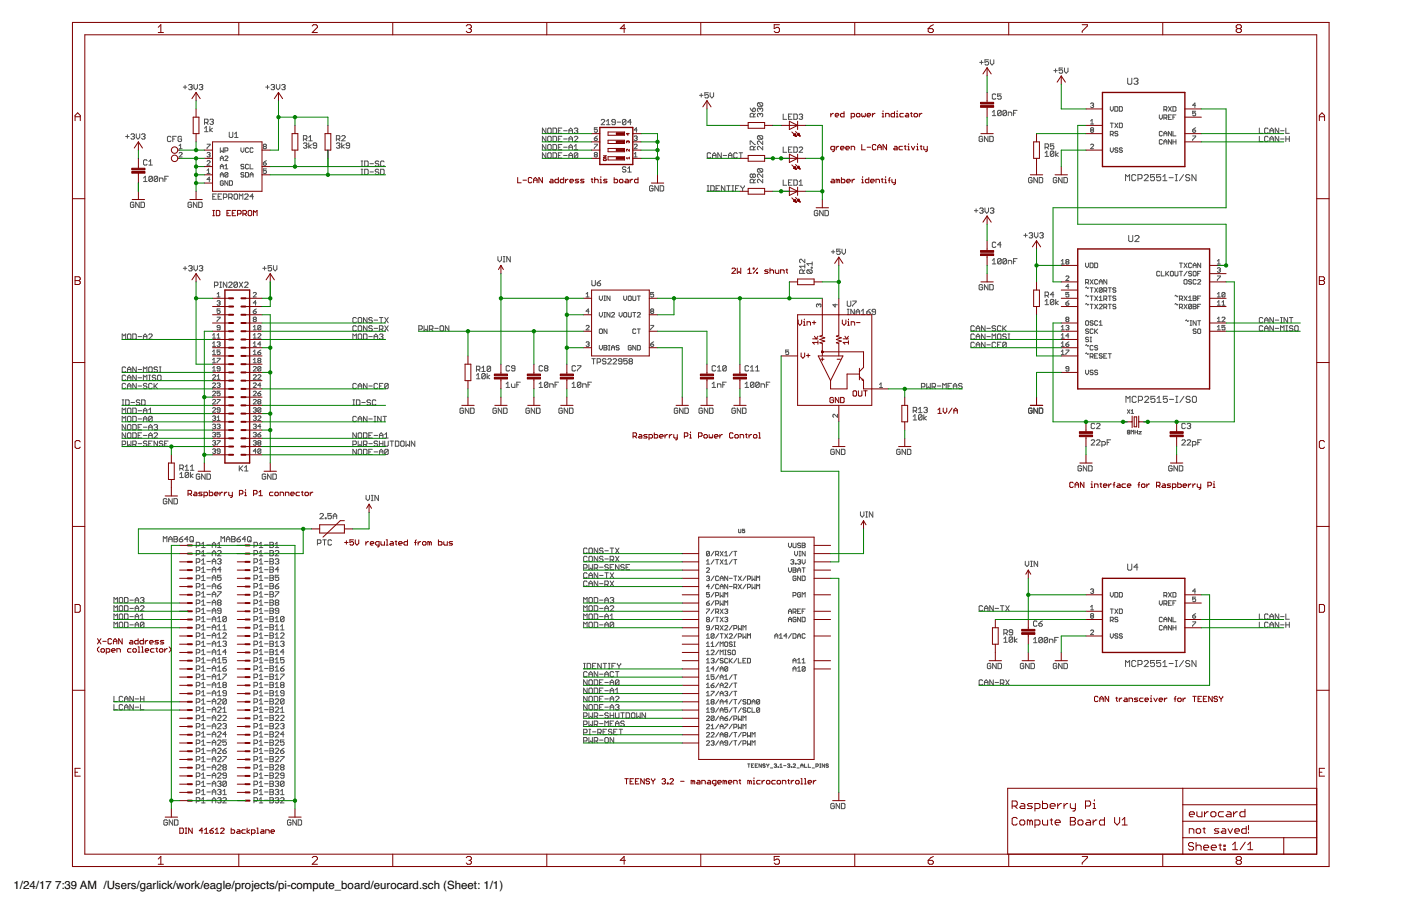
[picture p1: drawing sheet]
<svg xmlns="http://www.w3.org/2000/svg" width="432mm" height="279mm" viewBox="0 0 432 279" stroke-linecap="round" stroke-linejoin="round" font-family="sans-serif">
<defs><g id="words">
<g font-size="3.5">
<text x="4.2" y="274.2">1/24/17</text>
<text x="17" y="274.2">7:39 AM /Users/garlick/work/eagle/projects/pi-compute_board/eurocard.sch (Sheet: 1/1)</text>
</g>
</g></defs>
<g fill="none" stroke="#505050" stroke-width=".31">
<path d="M301.9 19.2h1.1M302.5 18.7v1.1M304.7 18.4h-1.1v.8l.5-.2 .6 .2v.6l-.3 .2h-.6l-.2-.2M305.2 18.4v1.1l.6 .5 .5-.5v-1.1M56.5 26.9h1.1M57 26.3v1.1M58.1 26.3l.3-.2h.5l.3 .2-.3 .6M58.7 26.9h.2M58.9 26.9l.3 .2-.3 .6h-.5l-.3-.3M59.8 26.1v1l.5 .6 .6-.6v-1M61.4 26.3l.3-.2h.5l.3 .2-.3 .6M62 26.9h.2"/>
<path d="M62.2 26.9l.3 .2-.3 .6h-.5l-.3-.3M63 39.5l.6-.5v1.6M63 37.8h.9l.2-.3v-.5l-.2-.3h-.9v1.7M63.6 37.8l.5 .6M64.7 39v1.6M64.7 37l.3-.3h.5l.3 .3-.3 .5M65.2 37.5h.3M65.5 39.5l-.8 .6 .8 .5M65.5 37.5l.3 .3-.3 .6h-.5l-.3-.3M81.9 26.9h1.1M82.4 26.3v1.1M83.5 26.3l.3-.2h.5l.3 .2-.3 .6"/>
<path d="M84.1 26.9h.2M84.3 26.9l.3 .2-.3 .6h-.5l-.3-.3M85.2 26.1v1l.5 .6 .6-.6v-1M86.8 26.3l.3-.2h.5l.3 .2-.3 .6M87.4 26.9h.2M87.6 26.9l.3 .2-.3 .6h-.5l-.3-.3M168.3 39.5v1.6l-1.1-1.6v1.6M168.8 39.8l.3-.3h.5l.3 .3v1.1l-.3 .2h-.5l-.3-.2zM170.4 39.5h.9l.2 .3v1.1l-.2 .2h-.9zM173.2 39.5h-1.1v1.6h1.1M177 39.8l.3-.3h.5l.3 .3-.3 .5M184.1 39.4h-.9v.7l.4-.2 .5 .2-.2 .7-.7-.2"/>
<path d="M185.3 37.1l.2-.3h.6l.3 .3v.3l-1.1 1.1h1.1M186.9 38.5h1.1M186.9 37.4l.6-.6v1.7M189.7 37.7h-.9l-.2-.3 .2-.6h.6l.3 .3v1.1l-.3 .3h-.6l-.2-.3M190.2 37.7h1.1M192.9 37.1v1.1l-.3 .3h-.5l-.3-.3M192.9 37.1l-.3-.3h-.5l-.3 .3v1.1M192.9 37.1l-1.1 1.1M194.6 37.7h-1.1l.8-.9v1.7M215.6 29.4h1.1M216.1 28.9v1.1M218.3 28.6h-1.1v.8l.6-.3 .5 .3v.6l-.3 .2h-.5l-.3-.2"/>
<path d="M218.9 28.6v1.1l.5 .5 .5-.5v-1.1M231.2 33.3l.8 1.1M232 33.6l.3-.3 .5 .3v.5l-.2 .3h-.6zM232.3 36v-.8l-.3-.2h-.5l-.3 .2v.8h1.6M232.8 35l-.5 .5M233.7 31.7l-.3 .3v.5l.3 .3h1.1M233.7 31.7h1.1l.3 .3v.5l-.3 .3M233.7 31.7l1.1 1.1M234.3 35.2l-.3-.2-.6 .2v.6l.3 .2M234.3 33.6l-.3-.3-.6 .3v.5l.3 .3M234.3 35.2l.2-.2 .6 .2v.6l-.3 .2M234.3 33.6v.3"/>
<path d="M234.3 35.2v.3M234.3 33.6l.2-.3 .6 .3v.5l-.3 .3M241.4 35.2v1.6h1.1M243 36h.6M244.1 35.2h-1.1v1.6h1.1M244.7 35.2h.8l.2 .3v1.1l-.2 .2h-.8zM246.3 35.5l.3-.3h.5l.3 .3-.3 .5M246.8 36h.3M247.1 36l.3 .3-.3 .5h-.5l-.3-.2M305.8 34.6l.6-.6v1.7M305.8 35.7h1.1M306.9 29.2l-.3-.2h-.5l-.3 .2v1.1l.3 .3h.5l.3-.3"/>
<path d="M308.6 29h-1.1v.8l.8-.3 .3 .3v.5l-.3 .3h-.6l-.2-.3M308.6 34.3l-.3-.3h-.6l-.2 .3v1.1M308.6 34.3v1.1l-.3 .3h-.6l-.2-.3M308.6 34.3l-1.1 1.1M310.2 34.3l-.3-.3h-.5l-.3 .3v1.1M310.2 34.3v1.1l-.3 .3h-.5l-.3-.3M310.2 34.3l-1.1 1.1M310.7 35.7v-1.1h.9l.2 .3v.8M312.4 34.9h.5M313.5 34h-1.1v1.7M324.8 21.8h1.1M325.3 21.2v1.1"/>
<path d="M327.5 21h-1.1v.8l.6-.3 .5 .3v.5l-.2 .3h-.6l-.3-.3M328.1 21v1.1l.5 .5 .6-.5v-1.1M336.1 32l.7-.2 .3 .2-.3 .5M336.1 37.3l.5-.4v1.3M336.1 38.2h1M336.6 32.5h.2M336.8 32.5l.3 .2-.3 .5-.7-.3M342.2 32.9v.9l.5 .5 .4-.5v-.9M342.2 38h.9M342.7 38v1.4M343.6 32.9h.7l.2 .2v1l-.2 .2h-.7zM343.6 38l.9 1.4"/>
<path d="M344.5 38l-.9 1.4M345 38h.7l.2 .2v.9l-.2 .3h-.7zM345 32.9h.7l.2 .2v1l-.2 .2h-.7zM347.6 24.1v1.6l.3 .3h.6l.3-.3v-1.6M349.5 24.4l.3-.3h.6l.3 .3-.3 .7M350.1 25.1h.3M350.4 25.1l.3 .3-.3 .6h-.6l-.3-.3M357.3 35.4v1l.5 .4 .4-.4v-1M358.7 33.8h.7l.2-.2-.2-.7h-.7v1.4M358.7 36.4h.7l.2-.3-.2-.7h-.7v1.4M359.2 33.8l.4 .5M359.2 36.4l.4 .4"/>
<path d="M360.1 32.9l.9 1.4M360.1 36.1h.5M361 35.4h-.9v1.4h.9M361 32.9l-.9 1.4M361.5 32.9h.7l.2 .2v1l-.2 .2h-.7zM361.5 36.1h.5M362.4 35.4h-.9v1.4M368.5 34.3h-.9v.7l.7-.2 .2 .7-.2 .2-.7-.2M368.5 32.5h-.9l.7-.7v1.4M368.5 39.4l-.9 .7M388.1 39.5v1.6h1.1M390.8 39.8l-.2-.3h-.6l-.2 .3v1.1l.2 .2h.6l.2-.2"/>
<path d="M394.1 39.5v1.6l-1.1-1.6v1.6M396.3 39.5v1.6h1.1M38.7 42.1h1.1M39.3 41.6v1M40.3 41.6l.3-.3h.6l.2 .3-.2 .5M40.9 42.1h.3M41.2 42.1l.2 .3-.2 .5h-.6l-.3-.3M42 41.3v1.1l.5 .5 .6-.5v-1.1M43.6 41.6l.3-.3h.5l.3 .3-.3 .5M44.2 42.1h.2M44.2 54.9l.6-.5v1.6M44.2 56h1.1"/>
<path d="M44.4 42.1l.3 .3-.3 .5h-.5l-.3-.3M45.3 49.6l-.2-.3h-.6l-.3 .3v1l.3 .3h.6l.2-.3M45.9 50.9h1.1M45.9 49.8l.5-.5v1.6M47 54.6v1.1l-.3 .3h-.5l-.3-.3M47 54.6l-.3-.2h-.5l-.3 .2v1.1M47 54.6l-1.1 1.1M48.6 54.6v1.1l-.3 .3h-.5l-.3-.3M48.6 54.6l-.3-.2h-.5l-.3 .2v1.1M48.6 54.6l-1.1 1.1M49.1 56v-1.1h.9l.2 .3v.8M50.8 55.2h.5"/>
<path d="M51.9 54.4h-1.1v1.6M52.7 42.3l-.3-.3h-.5l-.3 .3v1.1l.3 .3h.5l.3-.3M53.3 42.9h.5M54.3 42h-1v1.7M55.2 47.2l.2-.2 .7 .2-.9 1.2h.9M55.2 45.9h.9M55.2 44.9l.5-.4v1.4M56 42.3l-.3-.3h-.5l-.3 .3v1.1l.3 .3h.5l.3-.3v-.5h-.6M63 40.6h1.1M63.8 44.5h.9l-.9 1.4M63.8 47.2l.7-.2 .2 .2-.2 .5M63.8 49.8l.3-.2 .6 .2-.9 1.1h.9"/>
<path d="M63.8 53.5h.9M63.8 52.6l.5-.5v1.4M64.3 47.7h.2M64.5 47.7l.2 .2-.2 .5-.7-.2M64.7 55.3h-.9l.7-.7v1.4M66.7 59.8h-1.1v1.6h1.1M67.9 45.6v1.4l.5-.5 .4 .5v-1.4M67.9 49.5v-.9l.5-.5 .4 .5v.9M67.9 52.1v-1l.5-.4 .4 .4v1M67.9 54.6v-.9l.5-.5 .4 .5v.9M67.9 51.4h.9M67.9 53.9h.9"/>
<path d="M67.9 48.8h.9M68.3 59.8h-1.1v1.6h1.1M68.8 56l-.2-.2-.7 .2v.9l.2 .2 .7-.2v-.4h-.4M69.3 51.1l.5-.4v1.4M69.3 46.5h.7l.2-.7-.2-.2h-.7v1.4M69.3 48.4l.2-.3 .7 .3-.9 1.1h.9M69.3 52.1h.9M70.2 53.4l-.7-.2-.2 .2v1M70.2 55.8v1.3l-.9-1.3v1.3M70.2 53.4v1l-.2 .2-.7-.2M70.2 53.4l-.9 1M70.7 40.8v1.3l.2 .3h.6l.3-.3v-1.3"/>
<path d="M70.7 55.8h.7l.2 .2v.9l-.2 .2h-.7zM72.3 42.4h1.1M72.3 41.3l.5-.5v1.6M72.4 59.8h.5l.3 .3v1.1l-.3 .2h-.5l-.3-.2v-1.1zM74.3 45.6v.9l.4 .5 .5-.5v-.9M75.2 50.9l-.7-.2-.2 .4 .7 .3 .2 .4-.2 .3-.7-.3M75.2 53.4l-.7-.2-.2 .5 .7 .2 .2 .5-.2 .2-.7-.2M75.7 53.2h.7l.2 .2v1l-.2 .2h-.7zM76.6 45.8l-.2-.2-.7 .2v1l.2 .2 .7-.2M76.6 50.9l-.2-.2-.7 .2v.9l.2 .3 .7-.3M77.1 50.7v1.4h.9M77.1 54.6v-.9l.4-.5 .5 .5v.9"/>
<path d="M77.1 53.9h.9M78 45.8l-.2-.2-.7 .2v1l.2 .2 .7-.2M81.2 50.2h.7l.2 .5-.7 .2zM81.4 45.2h.5M81.4 45.2l-.2-.3 .2-.4 .7 .2-.2 .5M81.4 45.2l-.2 .2 .2 .5 .7-.3-.2-.4M82.1 52.1h-.9v.7l.4-.2 .5 .2v.5l-.2 .2-.7-.2M82.1 49.6l-.9 .6M93.5 44.3l.3-.2h.5l.3 .2-.3 .6M93.5 42.9h.8l.3-.3v-.5l-.3-.3h-.8v1.6M94.1 44.9h.2M94.1 42.9l.5 .5"/>
<path d="M94.3 44.9l.3 .3-.3 .5h-.5l-.3-.3M95.2 44.1v1.6M95.2 42.4l.5-.6v1.6M95.2 43.4h1M96 44.6l-.8 .6 .8 .5M97.6 44.9h-.8l-.3-.3 .3-.5h.5l.3 .2v1.1l-.3 .3h-.5l-.3-.3M103.7 44.3l.2-.2h.6l.3 .2-.3 .6M103.7 42.9h.8l.3-.3v-.5l-.3-.3h-.8v1.6M104.2 44.9h.3M104.2 42.9l.6 .5M104.5 44.9l.3 .3-.3 .5h-.6l-.2-.3M105.3 44.1v1.6"/>
<path d="M105.3 42.1l.3-.3h.5l.3 .3v.3l-1.1 1h1.1M106.1 44.6l-.8 .6 .8 .5M107.8 44.9h-.8l-.3-.3 .3-.5h.5l.3 .2v1.1l-.3 .3h-.5l-.3-.3M111.3 53.8h.5M111.3 51.3h.5M111.3 49.7h.5M111.3 52.2h.5M111.6 49.7v1.6M111.6 52.2v1.6M112.4 52.2h.8l.3 .3v1.1l-.3 .2h-.8zM112.4 49.7h.8l.3 .2v1.1l-.3 .3h-.8zM114 50.5h1.1"/>
<path d="M114 53h1.1M116.8 52.5l-.3-.3h-.6l-.2 .5 .2 .3h.6l.3 .6-.3 .2h-.6l-.2-.2M116.8 49.9l-.3-.2h-.6l-.2 .5 .2 .3h.6l.3 .5-.3 .3h-.6l-.2-.3M117.3 52.2h.8l.3 .3v1.1l-.3 .2h-.8zM118.4 49.9l-.3-.2h-.5l-.3 .2v1.1l.3 .3h.5l.3-.3M168.3 42v1.7l-1.1-1.7v1.7M168.3 44.6v1.6l-1.1-1.6v1.6M168.3 47.1v1.6l-1.1-1.6v1.6M168.8 44.9l.3-.3h.5l.3 .3v1l-.3 .3h-.5l-.3-.3zM169.1 42h.5l.3 .3v1.1l-.3 .3h-.5l-.3-.3v-1.1zM169.1 47.1h.5l.3 .3v1.1l-.3 .2h-.5l-.3-.2v-1.1zM170.4 42h.9l.2 .3v1.1l-.2 .3h-.9z"/>
<path d="M170.4 44.6h.9l.2 .3v1l-.2 .3h-.9zM170.4 47.1h.9l.2 .3v1.1l-.2 .2h-.9zM172.1 42.9h.5M172.1 40.3h.5M172.1 45.4h.5M172.1 47.9h.5M173.2 42h-1.1v1.7h1.1M173.2 44.6h-1.1v1.6h1.1M173.2 47.1h-1.1v1.6h1.1M173.7 42.9h1.1M173.7 40.3h1.1M173.7 45.4h1.1"/>
<path d="M173.7 47.9h1.1M175.3 42.9h1.1M175.3 40.3h1.1M175.3 41.1v-1.1l.6-.5 .5 .5v1.1M175.3 43.7v-1.1l.6-.6 .5 .6v1.1M175.3 46.2v-1.1l.6-.5 .5 .5v1.1M175.3 48.7v-1l.6-.6 .5 .6v1M175.3 45.4h1.1M175.3 47.9h1.1M177 42.3l.3-.3h.5l.3 .3v.3l-1.1 1.1h1.1M177 46.2h1.1M177 45.1l.5-.5v1.6"/>
<path d="M177.5 40.3h.3M177.8 40.3l.3 .3-.3 .5h-.5l-.3-.2M178.1 47.4l-.3-.3h-.5l-.3 .3v1.1M178.1 47.4l-1.1 1.1M178.1 47.4v1.1l-.3 .2h-.5l-.3-.2M183.2 42.6h.7l.2 .5-.7 .2zM183.2 44.5h.9l-.9 1.4M183.4 47.7l-.2 .2 .2 .5 .7-.2-.2-.5M183.4 47.7l-.2-.2 .2-.5 .7 .2-.2 .5M183.4 47.7h.5M184.1 41.9l-.9 .7M192.9 51.7l-.3-.3h-.5l-.3 .3 .3 .6h.5l.3 .2-.3 .6h-.5l-.3-.3"/>
<path d="M193.5 53.1h1.1M193.5 52l.5-.6v1.7M195.5 44.7l.2-.2 .7 .2-.9 1.2h.9M195.5 48.4h.9M195.5 42.2l.7-.3 .2 .3-.2 .4M195.5 47.5l.4-.5v1.4M195.9 42.6h.3M196.2 42.6l.2 .3-.2 .4-.7-.2M196.4 40.1h-.9l.7-.7v1.4M201.3 57.6l-.3-.3h-.6l-.2 .3v1l.2 .3h.6l.3-.3v-.5h-.6M202.9 57.3v1.6l-1.1-1.6v1.6M203.5 57.3h.8l.3 .3v1l-.3 .3h-.8z"/>
<path d="M218 57.3h.5M218 58.9h.5M218.2 57.3v1.6M219.1 57.3h.8l.2 .3v1l-.2 .3h-.8zM219.1 47.4l-.3-.3h-.6l-.2 .3v1.1l.2 .2h.6l.3-.2M219.6 48.7v-1l.5-.6 .6 .6v1M219.6 47.9h1.1M220.7 58.1h.5M221.8 57.3h-1.1v1.6h1.1M222.3 47.1v1.6l-1.1-1.6v1.6M222.9 47.9h1.1M223.4 57.3v1.6l-1.1-1.6v1.6"/>
<path d="M224 57.3h1M224.5 48.7v-1l.5-.6 .6 .6v1M224.5 47.9h1.1M224.5 57.3v1.6M225.6 57.3h.5M225.6 58.9h.5M225.9 57.3v1.6M226.7 58.1h.5M227.2 47.4l-.2-.3h-.6l-.3 .3v1.1l.3 .2h.6l.2-.2M227.8 57.3h-1.1v1.6M227.8 47.1h1.1M228.3 47.1v1.6"/>
<path d="M228.3 57.3l.6 .8M228.9 58.1v.8M229.4 57.3l-.5 .8M231.2 44.6v-1.1l1.6 1.1M232 53.9l-.3-.2-.5 .2v.6l.3 .2 .5-.2M232 53.9l.3-.2 .5 .2v.6l-.2 .2-.6-.2M232 53.9v.6M232.3 56.4v-.8l-.3-.3h-.5l-.3 .3v.8h1.6M232.3 46.2v-.8l-.3-.3h-.5l-.3 .3v.8h1.6M232.8 45.1l-.5 .6M232.8 55.3l-.5 .5M233.7 41.8l-.3 .3v.6l.3 .2h1.1"/>
<path d="M233.7 52l-.3 .3v.5l.3 .3h1.1M233.7 41.8h1.1l.3 .3v.6l-.3 .2M233.7 52h1.1l.3 .3v.5l-.3 .3M233.7 41.8l1.1 1.1M233.7 52l1.1 1.1M235.1 43.5v1.1l-1.1-1.1-.6 .3v.5l.3 .3M235.1 45.1v1.1l-1.1-1.1-.6 .3v.5l.3 .3M235.1 53.7v1l-1.1-1-.6 .2v.6l.3 .2M235.1 55.3v1.1l-1.1-1.1-.6 .3v.5l.3 .3M241.4 45.3v1.7h1.1M241.4 55.5v1.6h1.1M243 56.3h.6"/>
<path d="M243 46.2h.6M244.1 45.3h-1.1v1.7h1.1M244.1 55.5h-1.1v1.6h1.1M244.7 45.3h.8l.2 .3v1.1l-.2 .3h-.8zM244.7 55.5h.8l.2 .3v1.1l-.2 .2h-.8zM246.3 45.6l.3-.3h.5l.3 .3v.3l-1.1 1.1h1.1M246.3 57.1h1.1M246.3 56l.5-.5v1.6M302.9 42.3l-.3-.3h-.6l-.2 .3v1.1l.2 .3h.6l.3-.3v-.5h-.6M304.5 42v1.7l-1.1-1.7v1.7M305.1 42h.8l.2 .3v1.1l-.2 .3h-.8zM318.1 55l-.3-.3h-.5l-.3 .3v1.1l.3 .3h.5l.3-.3v-.5h-.5"/>
<path d="M319.7 54.7v1.7l-1.1-1.7v1.7M320.3 54.7h.8l.3 .3v1.1l-.3 .3h-.8zM322.1 47.2l.5-.6v1.6M322.1 48.2h1.1M322.1 45.4h.8l.3-.2v-.6l-.3-.2h-.8v1.6M322.6 45.4l.6 .6M324.8 44.4h-1.1v.8l.8-.3 .3 .3v.5l-.3 .3h-.5l-.3-.3M324.8 46.9l-.3-.3h-.5l-.3 .3v1.1M324.8 46.9v1.1l-.3 .2h-.5l-.3-.2M324.8 46.9l-1.1 1.1M325.4 46.6v1.6M325.7 55l-.3-.3h-.5l-.3 .3v1.1l.3 .3h.5l.3-.3v-.5h-.5"/>
<path d="M326.2 47.2l-.8 .5 .8 .5M327.3 54.7v1.7l-1-1.7v1.7M327.9 54.7h.8l.3 .3v1.1l-.3 .3h-.8zM336.1 44.7l.3-.2 .7 .2-1 1.2h1M336.4 40.1l-.3-.2 .3-.5 .7 .2-.3 .5M336.4 40.1l-.3 .2 .3 .5 .7-.2-.3-.5M336.4 40.1h.4M342.2 45.6v.9l.5 .5 .4-.5v-.9M342.2 41.4h.7l.2-.2-.2-.7h-.7v1.4M342.7 41.4l.4 .5M344.5 45.8l-.2-.2-.7 .2 .2 .5 .7 .2-.2 .5-.7-.2M344.5 40.7l-.2-.2-.7 .2 .2 .5 .7 .2-.2 .5-.7-.2"/>
<path d="M345.9 45.8l-.2-.2-.7 .2 .2 .5 .7 .2-.2 .5-.7-.2M346.9 55.7v-1.9l.6 .7 .6-.7v1.9M350.1 54.2l-.3-.4h-.7l-.3 .4v1.2l.3 .3h.7l.3-.3M350.7 55.1h1l.3-.3v-.6l-.3-.4h-1v1.9M352.7 54.2l.3-.4h.6l.3 .4v.3l-1.2 1.2h1.2M355.8 53.8h-1.2v1l.9-.3 .3 .3v.6l-.3 .3h-.6l-.3-.3M357.7 53.8h-1.2v1l.9-.3 .3 .3v.6l-.3 .3h-.6l-.3-.3M358.2 43.3l-.2-.2-.7 .2v.9l.2 .2 .7-.2M358.2 40.7l-.2-.2-.7 .2v1l.2 .2 .7-.2M358.4 55.7h1.3M358.4 54.5l.6-.7v1.9M358.7 41.2h.9"/>
<path d="M358.7 41.9v-.9l.5-.5 .4 .5v.9M358.7 44.4v-.9l.5-.4 .4 .4v.9M358.7 43.8h.9M360.3 54.8h1.3M361 40.5v1.4l-.9-1.4v1.4M361 43.1v1.3l-.9-1.3v1.3M361.5 40.5v1.4h.9M361.5 43.1v1.3M361.5 43.8h.9M362.2 53.8h.7M362.2 55.7h.7M362.4 43.1v1.3"/>
<path d="M362.6 53.8v1.9M364.8 53.8l-1.3 1.9M366.7 54.2l-.3-.4h-.6l-.4 .7 .4 .3h.6l.3 .6-.3 .3h-.6l-.4-.3M367.6 41.9h.9l-.9 1.4M367.6 40.1h.7l.2 .5-.7 .2zM368.6 53.8v1.9l-1.2-1.9v1.9M388.1 42v1.7h1.1M390.8 42.3l-.2-.3h-.6l-.2 .3v1.1l.2 .3h.6l.2-.3M391.4 42.9h1.1M391.4 43.7v-1.1l.5-.6 .6 .6v1.1M391.4 41.1v-1.1l.5-.5 .6 .5v1.1M391.4 40.3h1.1"/>
<path d="M394.1 42v1.7l-1.1-1.7v1.7M394.7 42.9h1.1M394.7 40.3h1.1M396.3 42.9h1.1M396.3 42v1.7M397.4 42v1.7M41.3 62.6l-.3-.2h-.6l-.2 .2v1.1l.2 .3h.6l.3-.3v-.5h-.6M42.9 62.4v1.6l-1.1-1.6v1.6M43.5 62.4h.8l.2 .2v1.1l-.2 .3h-.8zM59.1 62.6l-.3-.2h-.6l-.2 .2v1.1l.2 .3h.6l.3-.3v-.5h-.6M60.7 62.4v1.6l-1.1-1.6v1.6M61.2 62.4h.9l.2 .2v1.1l-.2 .3h-.9z"/>
<path d="M65.6 60.6h.5M67.2 60.6h.6M68.9 60.9h.8l.2-.3v-.5l-.2-.3h-.8v1.6M70.5 60.9h.8l.3-.3v-.5l-.3-.3h-.8v1.6M71 60.9l.6 .5M73.8 61.4v-1.6l.5 .6 .5-.6v1.6M75.4 60.1l.3-.3h.5l.3 .3v.3l-1.1 1h1.1M78.1 60.6h-1.1l.9-.8v1.6M153.5 79.1v1.1l.5 .6 .5-.6v-1.1M155.1 79.1h.5M155.4 79.1v1.7M157.3 79.1v1.7l-1.1-1.7v1.7"/>
<path d="M248.1 79.9v1.1l-1.1-1.1h-.3l-.3 .3v.6l.3 .2M252.1 65.2l-.3-.3h-.6l-.2 .3v1.1l.2 .2h.6l.3-.2v-.6h-.6M253.7 64.9v1.6l-1.1-1.6v1.6M254.3 64.9h.8l.2 .3v1.1l-.2 .2h-.8zM256.2 77.7h1.1M256.8 77.1v1.1M259 76.8h-1.1v.9l.5-.3 .6 .3v.5l-.3 .3h-.6l-.2-.3M259.5 76.8v1.1l.6 .6 .5-.6v-1.1M300.3 65h1.1M300.8 64.4v1.1M301.9 64.4l.3-.3h.5l.3 .3-.3 .6M302.5 65h.2"/>
<path d="M302.7 65l.3 .2-.3 .6h-.5l-.3-.3M303.6 64.1v1.1l.5 .6 .6-.6v-1.1M305.2 64.4l.3-.3h.5l.3 .3-.3 .6M305.8 65h.2M306 65l.3 .2-.3 .6h-.5l-.3-.3M306.9 75l-.3-.3h-.5l-.3 .3v1l.3 .3h.5l.3-.3M308.6 75.5h-1.1l.8-.8v1.6M313.5 79.8h-1.1v1.6M315.6 72.6h1M316.1 72v1.1M317.2 72l.3-.2h.5l.3 .2-.3 .6M317.7 72.6h.3"/>
<path d="M318 72.6l.3 .2-.3 .6h-.5l-.3-.3M318.8 71.8v1l.6 .6 .5-.6v-1M320.5 72l.2-.2h.6l.2 .2-.2 .6M321 72.6h.3M321.3 72.6l.2 .2-.2 .6h-.6l-.2-.3M347.9 72.6v1.6l.3 .3h.6l.3-.3v-1.6M349.8 72.9l.3-.3h.6l.3 .3v.4l-1.2 1.2h1.2M56.5 82.7h1.1M57 82.2v1.1M58.1 82.2l.3-.3h.5l.3 .3-.3 .5M58.7 82.7h.2M58.9 82.7l.3 .3-.3 .5h-.5l-.3-.2"/>
<path d="M59.8 81.9v1.1l.5 .5 .6-.5v-1.1M61.4 82.2l.3-.3h.5l.3 .3-.3 .5M62 82.7h.2M62.2 82.7l.3 .3-.3 .5h-.5l-.3-.2M66.1 88.1h.8l.3-.3v-.5l-.3-.3h-.8v1.6M66.9 93l.7-.3 .2 .3-.2 .4M66.9 90.7l.5-.5v1.4M66.9 91.6h.9M66.9 97.8h.9l-.9 1.4M67.4 93.4h.2M67.6 93.4l.2 .3-.2 .4-.7-.2M67.7 87h.6"/>
<path d="M67.7 88.6h.6M67.8 95.3h-.9v.7l.5-.3 .4 .3-.2 .7-.7-.3M68 87v1.6M69.9 87v1.6l-1.1-1.6v1.6M70.5 87.3l.2-.3h.6l.2 .3v.2l-1 1.1h1M73.2 87.3l-.3-.3h-.5l-.3 .3v1M73.2 87.3v1l-.3 .3h-.5l-.3-.3M73.2 87.3l-1.1 1M73.7 87l1.1 1.6M74.8 87l-1.1 1.6M75.4 87.3l.2-.3h.6l.3 .3v.2l-1.1 1.1h1.1M78.1 90.4l.2-.2 .7 .2-.9 1.2h.9"/>
<path d="M78.1 96h.7l.2 .4-.7 .3zM78.3 98.5l-.2-.2 .2-.5 .7 .2-.2 .5M78.3 98.5l-.2 .2 .2 .5 .7-.2-.2-.5M78.3 98.5h.5M79 93.4h-.9l.7-.7v1.4M79 95.3l-.9 .7M81 82.7h1.1M81.5 82.2v1.1M83.7 81.9h-1.1v.8l.6-.2 .5 .2v.6l-.3 .2h-.5l-.3-.2M84.3 81.9v1.1l.5 .5 .5-.5v-1.1M109.8 98.2l-.2-.3h-.6l-.2 .3v1.1l.2 .2h.6l.2-.2M110.4 98.2l.3-.3h.5l.3 .3v1.1l-.3 .2h-.5l-.3-.2z"/>
<path d="M113.1 97.9v1.6l-1.1-1.6v1.6M114.7 98.2l-.2-.3h-.6l-.2 .3 .2 .5h.6l.2 .3-.2 .5h-.6l-.2-.2M115.3 98.7h1.1M116.9 97.9h1.1M117.5 97.9v1.6M118.6 97.9l1.1 1.6M119.7 97.9l-1.1 1.6M155.1 80.8h.5M180.6 91.6h1M180.6 90.7l.5-.5v1.4M181.6 96h-1l.7-.7v1.4M182.4 86.5v1.3l.3 .3h.5l.3-.3v-1.3"/>
<path d="M184 87.3h.8l.3 .5-.3 .3h-.5l-.3-.3zM184.7 91.3v.9l.5 .5 .5-.5v-.9M184.7 96.4v.9l.5 .5 .5-.5v-.9M185.1 86.5l-1.1 .8M186.1 92.7h.5M186.1 97.8h.5M186.1 91.3h.5M186.1 96.4h.5M186.4 91.3v1.4M186.4 96.4v1.4M188 91.3v1.4l-.9-1.4v1.4M188 96.4v1.4l-.9-1.4v1.4"/>
<path d="M188.5 96.6l.2-.2 .7 .2-.9 1.2h.9M190.8 96.4v.9l.5 .5 .4-.5v-.9M192.2 91.3v.9l.5 .5 .4-.5v-.9M192.4 96.4l.7 .2v.9l-.2 .3-.7-.3v-.9zM193.6 91.5l.3-.2 .7 .2v1l-.3 .2-.7-.2zM193.6 96.4v1.1l.3 .3 .7-.3v-1.1M195 91.3v1.2l.3 .2 .7-.2v-1.2M195 96.4h1M195.5 96.4v1.4M196.4 96.6l.3-.2 .7 .2-1 1.2h1M196.4 91.3h1M196.9 91.3v1.4"/>
<path d="M200.8 96l-.3-.3 .3-.4 .7 .2-.3 .5M200.8 96l-.3 .2 .3 .5 .7-.3-.3-.4M200.8 96h.4M201.5 90.2h-1v.7l.7-.2 .3 .7-.3 .2-.7-.2M247.5 84.3v-.8l-.3-.3h-.5l-.3 .3v.8h1.7M248.1 83.2l-.6 .6M248.1 82.1h-1.7l.6 .6M248.1 81.6v1.1M249 83.2l-.3 .3v.5l.3 .3h1M249 83.2h1l.3 .3v.5l-.3 .3M249 83.2l1 1.1M250 82.4h.3v.3h-.3z"/>
<path d="M250.3 80.8v1.1M250.3 81.3h-1.6l.5 .6M252.3 94l.3-.3 .4 .3-.2 .7M252.3 94l-.2-.3-.5 .3 .3 .7M252.3 94v.2M257.4 93.7v1l-.7-.7h1.4M261.1 97h.6M261.1 95.4h.6M261.1 92.8v1.4l.3 .3h.6l.2-.3v-1.4M261.4 95.4v1.6M262.8 92.8h1.1l-1.1 1.7M263.3 95.4v1.6l-1.1-1.6v1.6"/>
<path d="M263.9 97v-1.1l.5-.5 .5 .5v1.1M263.9 96.2h1M265.5 97h1.1M265.5 95.9l.5-.5v1.6M267.1 96.2h.8l.3 .5-.3 .3h-.5l-.3-.3zM268.2 95.4l-1.1 .8M269.9 96.2h-.9l-.2-.3 .2-.5h.6l.3 .3v1l-.3 .3h-.6l-.2-.3M302.9 88l-.3-.2h-.6l-.2 .2v1.1l.2 .3h.6l.3-.3v-.5h-.6M304.5 87.8v1.6l-1.1-1.6v1.6M305.1 87.8h.8l.2 .2v1.1l-.2 .3h-.8zM305.8 80.3l.6-.5v1.6M305.8 81.4h1.1"/>
<path d="M308.6 80v1.1l-.3 .3h-.6l-.2-.3M308.6 80l-.3-.2h-.6l-.2 .2v1.1M308.6 80l-1.1 1.1M310.2 80v1.1l-.3 .3h-.5l-.3-.3M310.2 80l-.3-.2h-.5l-.3 .2v1.1M310.2 80l-1.1 1.1M310.7 81.4v-1.1h.9l.2 .3v.8M312.4 80.6h.5M322.1 92.9l.5-.6v1.7M322.1 94h1.1M322.1 91.1h.8l.3-.2v-.6l-.3-.2h-.8v1.6M322.6 91.1l.6 .6"/>
<path d="M324.8 92.6v1.1l-.3 .3h-.5l-.3-.3M324.8 92.6l-.3-.3h-.5l-.3 .3v1.1M324.8 92.6l-1.1 1.1M324.8 90.9h-1.1l.8-.8v1.6M325.4 92.3v1.7M326.2 92.9l-.8 .5 .8 .6M327.1 80.5l.5-.5v1.4M327.1 81.4h.9M328.5 93.4h.7l.2 .5-.7 .2zM328.5 85.3l.2-.2 .7 .2-.9 1.2h.9M328.7 98.5l-.2 .2 .2 .5 .7-.2-.2-.5M328.7 98.5l-.2-.2 .2-.5 .7 .2-.2 .5"/>
<path d="M328.7 80.7h.5M328.7 98.5h.5M328.7 80.7l-.2 .3 .2 .4 .7-.2-.2-.5M328.7 80.7l-.2-.2 .2-.5 .7 .3-.2 .4M329.4 90.2h-.9v.7l.7-.2 .2 .7-.2 .2-.7-.2M329.4 88.3h-.9l.7-.6v1.3M329.4 92.7l-.9 .7M334.6 88.8l.2-.3 .5 .5 .2-.2M334.6 81.1v1l.4 .4 .5-.4v-1M334.6 87.1h.7l.2-.2-.2-.7h-.7v1.4M334.6 91.3l.2-.2 .5 .4 .2-.2M334.6 93.8l.2-.2 .5 .5 .2-.3"/>
<path d="M334.8 98.9l.7 .2v1l-.2 .2-.7-.2v-1zM335 87.1l.5 .5M336 81.1h.7l.2 .3v.9l-.2 .2h-.7zM336 86.2l.9 1.4M336 88.8h.9M336 91.3h.9M336 93.8h.9M336.4 88.8v1.3M336.4 91.3v1.4M336.4 93.8v1.4M336.9 99.1l-.2-.2-.7 .2 .2 .5 .7 .2-.2 .5-.7-.2M336.9 86.2l-.9 1.4"/>
<path d="M337.4 81.1h.7l.2 .3v.9l-.2 .2h-.7zM337.4 88.8l.9 1.3M337.4 91.3l.9 1.4M337.4 93.8l.9 1.4M338.3 86.4l-.2-.2-.7 .2v1l.2 .2 .7-.2M338.3 99.1l-.2-.2-.7 .2v1l.2 .2 .7-.2M338.3 88.8l-.9 1.3M338.3 91.3l-.9 1.4M338.3 93.8l-.9 1.4M338.8 92.7h.9M338.8 94.1l.2-.3 .7 .3-.9 1.1h.9M338.8 87.6v-.9l.5-.5 .4 .5v.9"/>
<path d="M338.8 86.9h.9M338.8 91.8l.5-.5v1.4M338.8 99.4l.5-.5v1.4M339.7 89l-.2-.2-.7 .2v.9M339.7 89v.9l-.2 .2-.7-.2M339.7 89l-.9 .9M340.2 92.2h.7l.2-.7-.2-.2h-.7v1.4M340.2 89.7h.7l.2-.7-.2-.2h-.7v1.3M340.2 94.8h.7l.2-.7-.2-.3h-.7v1.4M340.7 89.7l.4 .4M340.7 92.2l.4 .5M340.7 94.8l.4 .4"/>
<path d="M341.1 86.2v1.4l-.9-1.4v1.4M341.6 88.8h.9M341.6 91.3h.9M341.6 93.8h.9M342.1 88.8v1.3M342.1 91.3v1.4M342.1 93.8v1.4M343.9 91.5l-.2-.2-.7 .2 .2 .5 .7 .2-.2 .5-.7-.2M343.9 94.1l-.2-.3-.7 .3 .2 .4 .7 .3-.2 .4-.7-.2M343.9 89l-.2-.2-.7 .2 .2 .5 .7 .2-.2 .4-.7-.2M357.4 83.9l-.2-.2-.7 .2v1l.2 .2 .7-.2M357.9 83.7v1.4h.9"/>
<path d="M359.3 83.7v1.4M359.5 84.4l.7 .7M360.2 83.7l-.9 .9M360.7 83.9l.3-.2 .7 .2v1l-.3 .2-.7-.2zM362.1 93.8l.3-.2 .4 .5 .3-.3M362.1 83.7v1.2l.3 .2 .7-.2v-1.2M362.1 91.3l.3-.2 .4 .4 .3-.2M363.5 81.1h.9M363.5 92.2h.7l.2-.7-.2-.2h-.7v1.4M363.5 94.8h.7l.2-.7-.2-.3h-.7v1.4M363.5 83.7h.9M364 81.1v1.4"/>
<path d="M364 83.7v1.4M364 92.2l.4 .5M364 94.8l.4 .4M364.9 86.4l.3-.2 .7 .2v1l-.3 .2-.7-.2zM364.9 81.1l1 1.4M364.9 91.3l1 1.4M364.9 93.8l1 1.4M365.4 98.9l.2-.2 .5 .4 .2-.2M365.9 81.1l-1 1.4M365.9 83.7l-1 1.4M365.9 91.3l-1 1.4M365.9 93.8l-1 1.4"/>
<path d="M366.3 92.7h1M366.3 91.8l.5-.5v1.4M366.8 98.9h.5M367 98.9v1.4M367.3 81.4l-.3-.3-.7 .3v.9l.3 .2 .7-.2M367.3 94.1v.9l-.3 .2-.7-.2M367.3 86.4l-.7-.2-.3 .5 .7 .2 .3 .5-.3 .2-.7-.2M367.3 94.1l-.7-.3-.3 .3v.9M367.3 83.9l-.3-.2-.7 .2 .3 .5h.4l.3 .5-.3 .2-.7-.2M367.3 94.1l-1 .9M367.7 91.3h.7l.3 .2-.3 .5 .3 .5-.3 .2h-.7zM367.7 93.8h.7l.3 .3-.3 .4 .3 .5-.3 .2h-.7z"/>
<path d="M367.7 92h.7M367.7 94.5h.7M367.7 82.5v-.9l.5-.5 .5 .5v.9M367.7 83.9l.3-.2 .7 .2v1l-.3 .2-.7-.2zM367.7 81.9h1M368.7 86.4l-.3-.2-.7 .2v1l.3 .2 .7-.2M368.7 98.9v1.4l-1-1.4v1.4M369.1 86.4l.3-.2 .7 .2-1 1.2h1M369.1 92h.5M369.1 94.5h.5M369.1 98.9h1M369.1 84.4h.5"/>
<path d="M369.6 98.9v1.4M370.1 81.1v1.4l-1-1.4v1.4M370.1 83.7h-1v1.4M370.1 91.3h-1v1.4M370.1 93.8h-1v1.4M375.2 98.3l.5-.5v1.4M375.2 91.6h.9M375.2 94.1h.9M375.2 99.2h.9M375.2 81.4h.9M375.2 85.1h.9l-.9 1.4M375.2 80.5l.5-.5v1.4"/>
<path d="M375.2 90.7l.5-.5v1.4M375.2 93.2l.5-.5v1.4M375.2 82.8l.7-.2 .2 .2-.2 .5M375.7 83.3h.2M375.9 83.3l.2 .2-.2 .5-.7-.3M376.6 94.1h.9M376.6 98l.3-.2 .6 .2-.9 1.2h.9M376.6 93.2l.5-.5v1.4M377.5 90.4v1l-.2 .2-.7-.2M377.5 90.4l-.2-.2-.7 .2v1M377.5 90.4l-.9 1M389.2 98.2l-.3-.3h-.5l-.3 .3v1.1l.3 .2h.5l.3-.2"/>
<path d="M389.8 99.5v-1l.5-.6 .5 .6v1M389.8 98.7h1M392.5 97.9v1.6l-1.1-1.6v1.6M393 98.7h1.1M394.7 97.9h.5M394.7 99.5h.5M394.9 97.9v1.6M396.9 97.9v1.6l-1.1-1.6v1.6M397.4 97.9h1.1M397.9 97.9v1.6M37.7 104.6v-1.6l.5 .5 .5-.5v1.6M38.7 113.4l-.2-.2h-.6l-.2 .2v1.1l.2 .3h.6l.2-.3"/>
<path d="M38.7 118.5l-.2-.3h-.6l-.2 .3v1.1l.2 .3h.6l.2-.3M38.7 116l-.2-.3h-.6l-.2 .3v1.1l.2 .2h.6l.2-.2M39.3 103.3l.3-.3h.5l.3 .3v1.1l-.3 .2h-.5l-.3-.2zM39.3 114.8v-1.1l.5-.5 .6 .5v1.1M39.3 117.3v-1.1l.5-.5 .6 .5v1.1M39.3 119.9v-1.1l.5-.6 .6 .6v1.1M39.3 119h1.1M39.3 114h1.1M39.3 116.5h1.1M40.9 103h.8l.3 .3v1.1l-.3 .2h-.8zM42 113.2v1.6l-1.1-1.6v1.6M42 115.7v1.6l-1.1-1.6v1.6"/>
<path d="M42 118.2v1.7l-1.1-1.7v1.7M42.6 119h1M42.6 103.8h1M42.6 114h1M42.6 116.5h1M44.2 104.6v-1.1l.5-.5 .6 .5v1.1M44.2 114.8v-1.6l.5 .5 .6-.5v1.6M44.2 117.3v-1.6l.5 .5 .6-.5v1.6M44.2 103.8h1.1M45.3 118.5l-.3-.3h-.5l-.3 .3 .3 .5h.5l.3 .3-.3 .6h-.5l-.3-.3M45.8 103.3l.3-.3h.6l.2 .3v.2l-1.1 1.1h1.1M45.8 115.7h.6"/>
<path d="M45.8 117.3h.6M46.1 113.2h.6l.2 .2v1.1l-.2 .3h-.6l-.3-.3v-1.1zM46.1 115.7v1.6M46.9 118.5l-.2-.3h-.6l-.3 .3v1.1l.3 .3h.6l.2-.3M47.5 118.2v1.7M47.7 119l.9 .9M48 116l-.3-.3h-.5l-.3 .5 .3 .3h.5l.3 .6-.3 .2h-.5l-.3-.2M48.6 116l.2-.3h.6l.2 .3v1.1l-.2 .2h-.6l-.2-.2zM48.6 113.4l-.3-.2h-.6l-.2 .5 .2 .3h.6l.3 .5-.3 .3h-.6l-.2-.3M48.6 118.2l-1.1 1.1M49.1 113.2h.5M49.1 114.8h.5"/>
<path d="M49.4 113.2v1.6M65.5 118.3l.2-.2 .7 .2-.9 1.2h.9M65.5 103.4l.5-.5v1.4M65.5 105.9l.5-.5v1.4M65.5 108.4l.5-.5v1.5M65.5 111l.5-.5v1.4M65.5 113.5l.5-.5v1.4M65.5 104.3h.9M65.5 106.8h.9M65.5 109.4h.9M65.5 111.9h.9M65.5 114.4h.9"/>
<path d="M65.5 115.8l.2-.2 .7 .2-.9 1.2h.9M66.9 103.4l.5-.5v1.4M66.9 116l.5-.4v1.4M66.9 105.6l.7-.2 .2 .2-.2 .5M66.9 110.5h.9l-.9 1.4M66.9 118.3l.7-.2 .2 .2-.2 .5M66.9 104.3h.9M66.9 117h.9M67.4 106.1h.2M67.4 118.8h.2M67.6 118.8l.2 .2-.2 .5-.7-.2M67.6 106.1l.2 .3-.2 .4-.7-.2"/>
<path d="M67.8 101h-.7l-.2-.2 .2-.4 .7 .2v.9l-.2 .2-.7-.2M67.8 107.9h-.9v.7l.5-.2 .4 .2-.2 .8-.7-.3M67.8 113.7h-.7l-.2-.2 .2-.5 .7 .3v.9l-.2 .2-.7-.2M78.1 118.3l.2-.2 .7 .2-.9 1.2h.9M78.1 113.3l.2-.3 .7 .3-.9 1.1h.9M78.1 115.8l.2-.2 .7 .2-.9 1.2h.9M78.1 101.7h.9M78.1 100.8l.4-.4v1.3M78.1 103.4l.4-.5v1.4M78.1 105.9l.4-.5v1.4M78.1 108.4l.4-.5v1.5M78.1 111l.4-.5v1.4"/>
<path d="M78.1 104.3h.9M78.1 106.8h.9M78.1 109.4h.9M78.1 111.9h.9M79.5 108.6h.7l.2 .5-.7 .3zM79.5 103.1l.2-.2 .7 .2-.9 1.2h.9M79.5 115.8l.2-.2 .7 .2-.9 1.2h.9M79.7 111.2l-.2-.2 .2-.5 .7 .2-.2 .5M79.7 111.2l-.2 .2 .2 .5 .7-.2-.2-.5M79.7 111.2h.5M80.4 100.6v.9l-.2 .2-.7-.2M80.4 100.6l-.7-.2-.2 .2v.9"/>
<path d="M80.4 113.3l-.7-.3-.2 .3v.9M80.4 113.3v.9l-.2 .2-.7-.2M80.4 100.6l-.9 .9M80.4 106.1h-.9l.7-.7v1.4M80.4 118.8h-.9l.7-.7v1.4M80.4 107.9l-.9 .7M80.4 113.3l-.9 .9M108.8 104.6v-1.6l.5 .5 .5-.5v1.6M109.8 118.5l-.2-.3h-.6l-.2 .3v1.1l.2 .3h.6l.2-.3M109.8 100.7l-.2-.2h-.6l-.2 .2v1.1l.2 .3h.6l.2-.3M110.4 103.3l.3-.3h.5l.3 .3v1.1l-.3 .2h-.5l-.3-.2zM110.4 119.9v-1.1l.5-.6 .6 .6v1.1"/>
<path d="M110.4 119h1.1M110.7 100.5h.5l.3 .2v1.1l-.3 .3h-.5l-.3-.3v-1.1zM112 103h.8l.3 .3v1.1l-.3 .2h-.8zM113.1 100.5v1.6l-1.1-1.6v1.6M113.1 118.2v1.7l-1.1-1.7v1.7M113.7 119h1M113.7 103.8h1M114.7 100.7l-.2-.2h-.6l-.2 .2 .2 .6h.6l.2 .2-.2 .6h-.6l-.2-.3M115.3 104.6v-1.1l.5-.5 .6 .5v1.1M115.3 101.3h1.1M115.3 103.8h1.1M116.4 118.5l-.3-.3h-.5l-.3 .3v1.1l.3 .3h.5l.3-.3"/>
<path d="M116.9 119h.6M116.9 101.5h.9l.2-.2v-.6l-.2-.2h-.9v1.6M116.9 103.3l.3-.3h.6l.2 .3-.2 .5M117.5 103.8h.3M117.5 101.5l.5 .6M117.8 103.8l.2 .3-.2 .5h-.6l-.3-.2M118 118.2h-1.1v1.7h1.1M118.6 100.5l1.1 1.6M119.7 118.5l-.3-.3h-.5l-.3 .3v1.1M119.7 118.5l-1.1 1.1M119.7 118.5v1.1l-.3 .3h-.5l-.3-.3M119.7 100.5l-1.1 1.6"/>
<path d="M129.1 101.5h.8l.3-.2v-.6l-.3-.2h-.8v1.6M130.7 100.5v1.6l.6-.6 .5 .6v-1.6M132.4 101.5h.8l.2-.2v-.6l-.2-.2h-.8v1.6M132.9 101.5l.5 .6M134 101.3h1.1M135.6 100.7l.3-.2h.5l.3 .2v1.1l-.3 .3h-.5l-.3-.3zM138.3 100.5v1.6l-1-1.6v1.6M146.9 115.7l.5-.5v1.6M146.9 116.8h1M146.9 114h.8l.2-.3v-.5l-.2-.3h-.8v1.7M147.4 114l.5 .6M148.5 113.5l.5-.6v1.7"/>
<path d="M148.5 114.6h1.1M149.6 115.5v1l-.3 .3h-.5l-.3-.3M149.6 115.5l-.3-.3h-.5l-.3 .3v1M149.6 115.5l-1.1 1M150.1 115.2v1.6M150.9 115.7l-.8 .6 .8 .5M151.2 113.2v1.1l-.3 .3h-.5l-.3-.3M151.2 113.2l-.3-.3h-.5l-.3 .3v1.1M151.2 113.2l-1.1 1.1M156 119.5h1.1M156 118.4l.5-.5v1.6M157.1 113.1l-.3-.3h-.5l-.3 .3v1l.3 .3h.5l.3-.3"/>
<path d="M157.6 118.4v.8l.3 .3h.8v-1.1M158.7 113.6h-.8l-.3-.3 .3-.5h.6l.2 .3v1l-.2 .3h-.6l-.3-.3M159.3 118.7h.5M160.4 117.9h-1.1v1.6M166.2 119.5h1M166.2 118.4l.5-.5v1.6M167.2 113.1l-.2-.3h-.6l-.2 .3v1l.2 .3h.6l.2-.3M168.1 113.6l-.3-.3 .3-.5h.5l.3 .3-.3 .5M168.1 113.6l-.3 .3 .3 .5h.5l.3-.3-.3-.5M168.1 113.6h.5M168.9 118.1l-.3-.2h-.5l-.3 .2v1.1M168.9 118.1v1.1l-.3 .3h-.5l-.3-.3"/>
<path d="M168.9 118.1l-1.1 1.1M169.4 119.5v-1.1h.8l.3 .3v.8M171.1 118.7h.5M172.1 117.9h-1v1.6M176.3 118.4l.5-.5v1.6M176.3 119.5h1.1M177.4 113.1l-.3-.3h-.5l-.3 .3v1l.3 .3h.5l.3-.3M177.9 112.8h1.1l-1.1 1.6M179 118.1v1.1l-.2 .3h-.6l-.3-.3M179 118.1l-.2-.2h-.6l-.3 .2v1.1M179 118.1l-1.1 1.1M179.6 119.5v-1.1h.8l.3 .3v.8"/>
<path d="M180.6 105.6l.7-.2 .3 .2-.3 .5M180.6 100.6l.3-.2 .7 .2-1 1.1h1M181.1 106.1h.2M181.2 118.7h.6M181.3 106.1l.3 .3-.3 .4-.7-.2M182.3 117.9h-1.1v1.6M182.4 110.6h1.1M182.9 110.6v1.6M184 111.7h.8l.3-.3v-.5l-.3-.3h-.8v1.6M184.7 101.7l.3-.2 .7 .2v.9l-.3 .2-.7-.2zM184.7 106.5v1l.5 .4 .5-.4v-1M186.1 106.5h.7l.3 .3-.3 .4 .3 .5-.3 .2h-.7z"/>
<path d="M186.1 107.2h.7M186.8 110.9l-.3-.3h-.6l-.2 .3 .2 .5h.6l.3 .3-.3 .5h-.6l-.2-.2M187.1 101.5v1.3l-1-1.3v1.3M187.3 110.9l.3-.3h.5l.3 .3v.2l-1.1 1.1h1.1M187.5 107.9h.5M187.5 106.5h.5M187.8 106.5v1.4M188.5 107.2h.9M188.5 107.9v-.9l.4-.5 .5 .5v.9M189 110.9l.2-.3h.6l.2 .3v.2l-1 1.1h1M190.8 106.8l-.7-.3-.2 .5 .7 .2 .2 .5-.2 .2-.7-.2M191.7 111.4h-.8l-.3-.3 .3-.5h.5l.3 .3v1.1l-.3 .2h-.5l-.3-.2"/>
<path d="M193.3 110.6h-1.1v.8l.6-.3 .5 .3v.6l-.3 .2h-.5l-.3-.2M194.1 111.4l-.2-.3 .2-.5h.6l.2 .3-.2 .5M194.1 111.4h.6M194.1 111.4l-.2 .3 .2 .5h.6l.2-.2-.2-.6M194.6 106.8l-.3-.3-.7 .3v.9l.7 .2 .3-.7h-.5M196 101.7l-.3-.2-.7 .2v.9l.3 .2 .7-.2M196 106.5v1.4l-1-1.4v1.4M196.4 106.5h.7l.3 .3v.9l-.3 .2h-.7zM196.4 101.5h1M196.9 101.5v1.3M200.5 100.4h1l-1 1.3M200.5 106.1h.7l.3 .5-.7 .2z"/>
<path d="M201.5 105.4l-1 .7M219.5 119.5h1.1M219.5 118.4l.5-.5v1.6M220.6 113.1l-.3-.3h-.5l-.3 .3v1l.3 .3h.5l.3-.3M221.1 119.5v-1.1h.8l.3 .3v.8M221.1 113.3l.6-.5v1.6M221.1 114.4h1.1M222.8 118.7h.5M223.8 117.9h-1v1.6M223.8 113.1l-.2-.3h-.6l-.2 .3v1M223.8 113.1v1l-.2 .3h-.6l-.2-.3M223.8 113.1l-1 1"/>
<path d="M229.6 119.5h1.1M229.6 118.4l.6-.5v1.6M230.7 113.1l-.2-.3h-.6l-.3 .3v1l.3 .3h.6l.2-.3M231.3 114.4h1.1M231.3 113.3l.5-.5v1.6M232.4 118.1v1.1l-.3 .3h-.5l-.3-.3M232.4 118.1l-.3-.2h-.5l-.3 .2v1.1M232.4 118.1l-1.1 1.1M232.9 113.3l.6-.5v1.6M232.9 114.4h1.1M234 118.1v1.1l-.3 .3h-.5l-.3-.3M234 118.1l-.3-.2h-.5l-.3 .2v1.1"/>
<path d="M234 118.1l-1.1 1.1M234.5 119.5v-1.1h.9l.2 .3v.8M236.2 118.7h.5M237.3 117.9h-1.1v1.6M243.1 107.9h-1v.7l.5-.2 .5 .2-.3 .8-.7-.3M271.1 118.6l.4-.5v1.4M271.1 119.5h.9M284 119.3h.8l.3-.3v-.5l-.3-.3h-.8v1.7M285.6 118.2v1.7l.6-.6 .5 .6v-1.7M287.3 119.3h.8l.3-.3v-.5l-.3-.3h-.8v1.7M287.8 119.3l.6 .6M288.9 119h1.1"/>
<path d="M290.5 119.9v-1.7l.6 .6 .5-.6v1.7M292.2 119h.5M293.3 118.2h-1.1v1.7h1.1M293.8 119h1.1M293.8 119.9v-1.1l.6-.6 .5 .6v1.1M296.5 118.5l-.2-.3h-.6l-.3 .6 .3 .2h.6l.2 .6-.2 .3h-.6l-.3-.3M300.3 100.7l-.3-.2h-.5l-.3 .2v1.1l.3 .3h.5l.3-.3M300.3 103.3l-.3-.3h-.5l-.3 .3v1.1l.3 .2h.5l.3-.2M300.3 105.8l-.3-.3h-.5l-.3 .3v1.1l.3 .3h.5l.3-.3M300.9 104.6v-1.1l.5-.5 .6 .5v1.1M300.9 102.1v-1.1l.5-.5 .6 .5v1.1M300.9 107.2v-1.1l.5-.6 .6 .6v1.1"/>
<path d="M300.9 101.3h1.1M300.9 106.3h1.1M300.9 103.8h1.1M303.6 100.5v1.6l-1.1-1.6v1.6M303.6 103v1.6l-1.1-1.6v1.6M303.6 105.5v1.7l-1.1-1.7v1.7M304.1 101.3h1.1M304.1 106.3h1.1M304.1 103.8h1.1M305.8 104.6v-1.6l.5 .5 .6-.5v1.6M306.9 100.7l-.3-.2h-.6l-.2 .5 .2 .3h.6l.3 .5-.3 .3h-.6l-.2-.3M306.9 105.8l-.3-.3h-.6l-.2 .3v1.1l.2 .3h.6l.3-.3"/>
<path d="M307.4 103.3l.3-.3h.5l.3 .3v1.1l-.3 .2h-.5l-.3-.2zM307.4 106.3h.6M308.5 100.7l-.3-.2h-.5l-.3 .2v1.1l.3 .3h.5l.3-.3M308.5 105.5h-1.1v1.7h1.1M309.1 100.5v1.6M309.3 101.3l.8 .8M310.1 105.8l-.2-.3h-.6l-.2 .3v1.1M310.1 103.3l-.2-.3h-.6l-.2 .5 .2 .3h.6l.2 .6-.2 .2h-.6l-.2-.2M310.1 100.5l-1 1M310.1 105.8v1.1l-.2 .3h-.6l-.2-.3M310.1 105.8l-1 1.1M310.7 103h.5"/>
<path d="M310.7 104.6h.5M311 103v1.6M327.1 100.8l.5-.4v1.3M327.1 103.4l.5-.5v1.4M327.1 105.9l.5-.5v1.4M327.1 108.4l.5-.5v1.5M327.1 101.7h.9M327.1 104.3h.9M327.1 106.8h.9M327.1 109.4h.9M328.5 100.6l.7-.2 .2 .2-.2 .4M328.5 106.1h.7l.2 .5-.7 .2z"/>
<path d="M328.5 107.9h.9l-.9 1.5M329 101h.2M329.2 101l.2 .3-.2 .4-.7-.2M329.4 113.7h-.7l-.2-.2 .2-.5 .7 .3v.9l-.2 .2-.7-.2M329.4 103.6h-.9l.7-.7v1.4M329.4 105.4l-.9 .7M334.6 114.2v.9l.4 .4 .5-.4v-.9M334.6 106.5l.2-.2 .5 .5 .2-.3M334.6 109.1l.2-.3 .5 .5 .2-.2M335.5 101.7l-.7-.2-.2 .4 .7 .3 .2 .4-.2 .2-.7-.2M335.5 104.2l-.7-.2-.2 .5 .7 .2 .2 .5-.2 .2-.7-.2M336 110h.7l.2-.7-.2-.2h-.7v1.4"/>
<path d="M336 105.4h.4M336 104h.4M336.2 104v1.4M336.4 110l.5 .5M336.9 106.8l-.2-.3-.7 .3v.9l.2 .2 .7-.2M336.9 101.7l-.2-.2-.7 .2v.9l.2 .2 .7-.2M336.9 114.4l-.2-.2-.7 .2 .2 .5 .7 .2-.2 .4-.7-.2M337.4 101.5v1.3M337.4 109.8h.4M337.6 102.2l.7 .6M338.3 106.8l-.2-.3-.7 .3 .2 .4 .7 .3-.2 .4-.7-.2M338.3 109.1h-.9v1.4h.9"/>
<path d="M338.3 114.4l-.2-.2-.7 .2 .2 .5 .7 .2-.2 .4-.7-.2M338.3 101.5l-.9 .9M338.8 100.3h.9M339.7 109.3l-.2-.2-.7 .2 .2 .5 .7 .2-.2 .5-.7-.3M340.2 109.8h.5M341.1 109.1h-.9v1.4h.9M341.6 109.1h.9M342.1 109.1v1.4M366.8 100.3h.5M368.7 101.7l-.3-.2-.7 .2 .3 .5 .7 .2-.3 .4-.7-.2M369.1 101.7l.3-.2 .7 .2v.9l-.3 .2-.7-.2zM375.2 101.7h.9"/>
<path d="M375.2 100.8l.5-.4v1.3M377.5 100.4h-.9v.6l.7-.2 .2 .7-.2 .2-.7-.2M389.2 100.7l-.3-.2h-.5l-.3 .2v1.1l.3 .3h.5l.3-.3M389.8 102.1v-1.1l.5-.5 .5 .5v1.1M389.8 101.3h1M392.5 100.5v1.6l-1.1-1.6v1.6M393 101.3h1.1M394.7 102.1v-1.6l.5 .5 .6-.5v1.6M396.3 100.5h.6M396.3 102.1h.6M396.6 100.5v1.6M398.5 100.7l-.3-.2h-.5l-.3 .5 .3 .3h.5l.3 .5-.3 .3h-.5l-.3-.3"/>
<path d="M399.3 100.5h.6l.2 .2v1.1l-.2 .3h-.6l-.3-.3v-1.1zM37.7 127.5v-1.6l.5 .5 .5-.5v1.6M37.7 130v-1.6l.5 .5 .5-.5v1.6M37.7 124.9h.5M37.7 123.3h.5M37.7 137.1h.8l.2-.3v-.5l-.2-.3h-.8v1.6M37.9 123.3v1.6M38.7 123.3h.9l.2 .3v1.1l-.2 .2h-.9zM38.7 130.9v1.7l-1-1.7v1.7M38.7 133.5v1.6l-1-1.6v1.6M39.3 128.7l.3-.3h.5l.3 .3v1.1l-.3 .2h-.5l-.3-.2zM39.3 131.2l.3-.3h.5l.3 .3v1.1l-.3 .3h-.5l-.3-.3z"/>
<path d="M39.3 133.7l.3-.2h.5l.3 .2v1.1l-.3 .3h-.5l-.3-.3zM39.3 136v1.6l.5-.5 .6 .5v-1.6M39.6 125.9h.5l.3 .2v1.1l-.3 .3h-.5l-.3-.3v-1.1zM40.4 124.1h1.1M40.9 125.9h.8l.3 .2v1.1l-.3 .3h-.8zM40.9 128.4h.8l.3 .3v1.1l-.3 .2h-.8zM40.9 130.9h.8l.3 .3v1.1l-.3 .3h-.8zM40.9 133.5h.8l.3 .2v1.1l-.3 .3h-.8zM40.9 137.1h.8l.3-.3v-.5l-.3-.3h-.8v1.6M41.5 137.1l.5 .5M42.6 126.7h1M42.6 129.2h1"/>
<path d="M42.6 131.7h.5M42.6 134.3h.5M42.6 136.8h1M43.1 123.6l-.3-.3h-.5l-.3 .3 .3 .5h.5l.3 .3-.3 .5h-.5l-.3-.2M43.6 123.3h.9l.2 .3v1.1l-.2 .2h-.9zM43.6 130.9h-1v1.7h1M43.6 133.5h-1v1.6h1M44.2 126.7h1.1M44.2 127.5v-1.1l.5-.5 .6 .5v1.1M44.2 130v-1.1l.5-.5 .6 .5v1.1M44.2 129.2h1.1M44.2 131.7h1.1"/>
<path d="M44.2 134.3h1.1M45.3 136.3l-.3-.3h-.5l-.3 .3 .3 .5h.5l.3 .3-.3 .5h-.5l-.3-.2M45.8 127.5h1.1M45.8 126.4l.6-.5v1.6M45.8 135.1v-1.1l.6-.5 .5 .5v1.1M45.8 132.6v-1.1l.6-.6 .5 .6v1.1M45.8 131.7h1.1M45.8 134.3h1.1M45.8 136.8h.6M46.9 128.7l-.2-.3h-.6l-.3 .3v1.1M46.9 128.7v1.1l-.2 .2h-.6l-.3-.2M46.9 136h-1.1v1.6h1.1"/>
<path d="M46.9 128.7l-1.1 1.1M47.5 131.2l.2-.3h.6l.3 .3-.3 .5M47.5 133.7l.2-.2h.6l.3 .2v.3l-1.1 1.1h1.1M48 131.7h.3M48.3 131.7l.3 .3-.3 .6h-.6l-.2-.3M48.6 136v1.6l-1.1-1.6v1.6M50.2 136.3l-.3-.3h-.5l-.3 .3 .3 .5h.5l.3 .3-.3 .5h-.5l-.3-.2M50.7 136.8h.6M51.8 136h-1.1v1.6h1.1M65.5 123.4l.2-.2 .7 .2-.9 1.2h.9M65.5 120.9l.2-.3 .7 .3-.9 1.1h.9M65.5 126l.2-.3 .7 .3-.9 1.1h.9"/>
<path d="M65.5 128.5l.7-.2 .2 .2-.2 .5M65.5 131l.7-.2 .2 .2-.2 .5M65.5 133.6l.7-.3 .2 .3-.2 .4M65.5 136.1l.7-.2 .2 .2-.2 .5M65.5 138.7l.7-.3 .2 .3-.2 .4M66 129h.2M66 131.5h.2M66 134h.2M66 136.6h.2M66 139.1h.2M66.2 129l.2 .2-.2 .5-.7-.3M66.2 131.5l.2 .2-.2 .5-.7-.2"/>
<path d="M66.2 134l.2 .3-.2 .4-.7-.2M66.2 136.6l.2 .2-.2 .5-.7-.2M66.2 139.1l.2 .3-.2 .4-.7-.2M66.9 123.2h.9l-.9 1.4M66.9 128.7l.5-.4v1.4M66.9 131l.7-.2 .2 .2-.2 .5M66.9 135.9h.9l-.9 1.4M66.9 129.7h.9M67.4 131.5h.2M67.6 131.5l.2 .2-.2 .5-.7-.2M67.8 133.3h-.9v.7l.5-.2 .4 .2-.2 .7-.7-.2M67.8 120.6h-.9v.7l.5-.2 .4 .2-.2 .7-.7-.2"/>
<path d="M67.8 126.4h-.7l-.2-.2 .2-.5 .7 .3v.9l-.2 .2-.7-.2M67.8 139.1h-.7l-.2-.2 .2-.5 .7 .3v.9l-.2 .2-.7-.2M78.1 123.4l.2-.2 .7 .2-.9 1.2h.9M78.1 120.9l.2-.3 .7 .3-.9 1.1h.9M78.1 126l.7-.3 .2 .3-.2 .4M78.1 128.5l.7-.2 .2 .2-.2 .5M78.1 131l.7-.2 .2 .2-.2 .5M78.1 133.6l.7-.3 .2 .3-.2 .4M78.1 136.1l.7-.2 .2 .2-.2 .5M78.5 126.4h.3M78.5 129h.3M78.5 131.5h.3"/>
<path d="M78.5 134h.3M78.5 136.6h.3M78.8 126.4l.2 .3-.2 .4-.7-.2M78.8 129l.2 .2-.2 .5-.7-.3M78.8 131.5l.2 .2-.2 .5-.7-.2M78.8 134l.2 .3-.2 .4-.7-.2M78.8 136.6l.2 .2-.2 .5-.7-.2M79 139.1h-.9l.7-.7v1.4M79.5 121.3h.7l.2 .5-.7 .2zM79.5 134h.7l.2 .5-.7 .2zM79.5 128.5l.2-.2 .7 .2-.9 1.2h.9M79.7 123.9l-.2-.2 .2-.5 .7 .2-.2 .5"/>
<path d="M79.7 123.9l-.2 .2 .2 .5 .7-.2-.2-.5M79.7 136.6l-.2-.2 .2-.5 .7 .2-.2 .5M79.7 136.6l-.2 .2 .2 .5 .7-.2-.2-.5M79.7 123.9h.5M79.7 136.6h.5M80.4 126l-.7-.3-.2 .3v.9M80.4 138.7l-.2-.3-.7 .3v.9M80.4 126v.9l-.2 .2-.7-.2M80.4 138.7v.9l-.2 .2-.7-.2M80.4 131.5h-.9l.7-.7v1.4M80.4 120.6l-.9 .7M80.4 126l-.9 .9"/>
<path d="M80.4 133.3l-.9 .7M80.4 138.7l-.9 .9M108.8 124.9h.5M108.8 123.3h.5M108.8 137.1h.8l.2-.3v-.5l-.2-.3h-.8v1.6M109 123.3v1.6M109.8 128.7l-.2-.3h-.6l-.2 .3v1.1l.2 .2h.6l.2-.2M109.8 133.5v1.6l-1-1.6v1.6M109.8 138.6v1.6l-1-1.6v1.6M109.9 123.3h.8l.2 .3v1.1l-.2 .2h-.8zM110.4 138.8l.3-.2h.5l.3 .2v1.1l-.3 .3h-.5l-.3-.3zM110.4 130v-1.1l.5-.5 .6 .5v1.1"/>
<path d="M110.4 133.7l.3-.2h.5l.3 .2v1.1l-.3 .3h-.5l-.3-.3zM110.4 136v1.6l.5-.5 .6 .5v-1.6M110.4 129.2h1.1M111.5 124.1h1.1M112 138.6h.8l.3 .2v1.1l-.3 .3h-.8zM112 137.1h.8l.3-.3v-.5l-.3-.3h-.8v1.6M112 133.5h.8l.3 .2v1.1l-.3 .3h-.8zM112.6 137.1l.5 .5M113.1 128.4v1.6l-1.1-1.6v1.6M113.7 139.4h.5M113.7 129.2h1M113.7 134.3h.5"/>
<path d="M113.7 136.8h1M114.2 123.6l-.3-.3h-.5l-.3 .5 .3 .3h.5l.3 .6-.3 .2h-.5l-.3-.2M114.7 138.6h-1v1.6h1M114.7 133.5h-1v1.6h1M115.3 139.4h1.1M115.3 128.4h.5M115.3 130h.5M115.3 134.3h1.1M115.6 128.4v1.6M115.8 123.6l-.2-.3h-.6l-.2 .3v1.1l.2 .2h.6l.2-.2M116.4 136.3l-.3-.3h-.5l-.3 .3 .3 .5h.5l.3 .3-.3 .5h-.5l-.3-.2M116.9 139.4h1.1"/>
<path d="M116.9 135.1v-1.1l.6-.5 .5 .5v1.1M116.9 136v1.6M116.9 134.3h1.1M116.9 136.8h1.1M117.5 128.4v1.6l-1.1-1.6v1.6M118 128.4h1.1M118 136v1.6M118.6 136v1.4l.3 .2h.5l.3-.2v-1.4M118.6 128.4v1.6M118.6 135.1h1.1M118.6 134l.5-.5v1.6M119.7 138.8l-.3-.2h-.5l-.3 .2v1.1"/>
<path d="M119.7 138.8v1.1l-.3 .3h-.5l-.3-.3M119.7 138.8l-1.1 1.1M120.2 136h1.1M120.8 136v1.6M121.9 136h.8l.2 .3v1.1l-.2 .2h-.8zM123.5 136.3l.3-.3h.5l.3 .3v1.1l-.3 .2h-.5l-.3-.2zM125.1 136v1.6l.6-.5 .5 .5v-1.6M127.8 136v1.6l-1-1.6v1.6M142.9 126.1l-.3-.2h-.6l-.2 .2v1.1l.2 .3h.6l.3-.3v-.5h-.6M144.5 125.9v1.6l-1.1-1.6v1.6M145.1 125.9h.8l.2 .2v1.1l-.2 .3h-.8zM153 126.1l-.3-.2h-.5l-.3 .2v1.1l.3 .3h.5l.3-.3v-.5h-.5"/>
<path d="M154.6 125.9v1.6l-1-1.6v1.6M155.2 125.9h.8l.3 .2v1.1l-.3 .3h-.8zM163.2 126.1l-.3-.2h-.5l-.3 .2v1.1l.3 .3h.5l.3-.3v-.5h-.6M164.8 125.9v1.6l-1.1-1.6v1.6M165.4 125.9h.8l.3 .2v1.1l-.3 .3h-.8zM173.3 126.1l-.2-.2h-.6l-.2 .2v1.1l.2 .3h.6l.2-.3v-.5h-.5M175 125.9v1.6l-1.1-1.6v1.6M175.5 125.9h.8l.3 .2v1.1l-.3 .3h-.8zM208.9 126.1l-.3-.2h-.5l-.3 .2v1.1l.3 .3h.5l.3-.3v-.5h-.6M210.5 125.9v1.6l-1.1-1.6v1.6M211.1 125.9h.8l.3 .2v1.1l-.3 .3h-.8zM216.5 126.1l-.3-.2h-.5l-.3 .2v1.1l.3 .3h.5l.3-.3v-.5h-.5"/>
<path d="M218.1 125.9v1.6l-1-1.6v1.6M218.7 125.9h.8l.3 .2v1.1l-.3 .3h-.8zM226.7 126.1l-.3-.2h-.6l-.2 .2v1.1l.2 .3h.6l.3-.3v-.5h-.6M228.3 125.9v1.6l-1.1-1.6v1.6M228.9 125.9h.8l.2 .2v1.1l-.2 .3h-.8zM257.2 138.8l-.3-.2h-.6l-.2 .2v1.1l.2 .3h.6l.3-.3v-.5h-.6M258.1 127.8v.9l-.9-.9-.5 .2 .2 .7M258.8 138.6v1.6l-1.1-1.6v1.6M259.3 138.6h.8l.3 .2v1.1l-.3 .3h-.8zM277.5 138.8l-.3-.2h-.6l-.2 .2v1.1l.2 .3h.6l.3-.3v-.5h-.6M279.1 138.6v1.6l-1.1-1.6v1.6M279.7 138.6h.8l.2 .2v1.1l-.2 .3h-.8z"/>
<path d="M281.5 126.7h.8l.2-.3v-.5l-.2-.3h-.8v1.7M281.5 128.4l.5-.5v1.6M281.5 129.5h1M282 126.7l.5 .6M283.1 126.2l.5-.6v1.7M283.1 127.3h1.1M284.2 128.2l-.3-.3h-.5l-.3 .3v1M284.2 128.2v1l-.3 .3h-.5l-.3-.3M284.2 128.2l-1.1 1M284.7 127.9v1.6M284.7 125.9l.3-.3h.5l.3 .3-.3 .5M285.3 126.4h.2"/>
<path d="M285.5 128.4l-.8 .6 .8 .5M285.5 126.4l.3 .3-.3 .6h-.5l-.3-.3M318.1 126.1l-.3-.2h-.5l-.3 .2v1.1l.3 .3h.5l.3-.3v-.5h-.5M319.7 125.9v1.6l-1.1-1.6v1.6M320.3 125.9h.8l.3 .2v1.1l-.3 .3h-.8zM336.3 135.9l.3-.3h.5l.3 .3v.3l-1.1 1h1.1M337.4 130.8l-.3-.2h-.5l-.3 .2v1.1l.3 .3h.5l.3-.3M337.9 135.9l.3-.3h.6l.2 .3v.3l-1.1 1h1.1M337.9 130.8l.3-.2h.6l.2 .2v.3l-1.1 1.1h1.1M339.6 137.2h.8l.3-.2v-.6l-.3-.2h-.8v1.6M341.2 136.4h.6M342.3 135.6h-1.1v1.6"/>
<path d="M347 124.1v-1.9l.7 .7 .6-.7v1.9M347.5 126.3l.7 1.2M347.7 133.3l-.2-.2 .2-.4 .5 .2-.2 .4M347.7 133.3l-.2 .2 .2 .3 .5-.2-.2-.3M347.7 133.3h.3M348.2 126.3l-.7 1.2M348.6 127.5h.8M348.6 133.8v-1.1l.4 .4 .4-.4v1.1M348.6 126.7l.4-.4v1.2M349.8 133.3h.8M349.8 132.7v1.1M350.2 122.5l-.3-.3h-.6l-.3 .3v1.3l.3 .3h.6l.3-.3"/>
<path d="M350.6 132.7v1.1M350.9 123.5h.9l.3-.3v-.7l-.3-.3h-.9v1.9M351 133.1h.7l-.7 .7h.7M352.8 122.5l.3-.3h.6l.3 .3v.4l-1.2 1.2h1.2M356 122.2h-1.3v1l.6-.3 .7 .3v.6l-.4 .3h-.6l-.3-.3M356.6 124.1h1.3M356.6 122.9l.7-.7v1.9M359.8 122.2h-1.3v1l.7-.3 .6 .3v.6l-.3 .3h-.6l-.4-.3M360.4 123.2h1.3M362.4 122.2h.6M362.4 124.1h.6M362.7 122.2v1.9"/>
<path d="M364.3 135.9l.2-.3h.6l.2 .3v.3l-1 1h1M364.9 122.2l-1.3 1.9M365.3 130.8l-.2-.2h-.6l-.2 .2v1.1l.2 .3h.6l.2-.3M365.9 135.9l.3-.3h.5l.3 .3v.3l-1.1 1h1.1M365.9 130.8l.3-.2h.5l.3 .2-.3 .6M366.4 131.4h.3M366.7 131.4l.3 .2-.3 .6h-.5l-.3-.3M366.8 122.5l-.3-.3h-.6l-.3 .7 .3 .3h.6l.3 .6-.3 .3h-.6l-.3-.3M367.5 137.2h.8l.3-.2v-.6l-.3-.2h-.8v1.6M367.8 122.2h.6l.3 .3v1.3l-.3 .3h-.6l-.3-.3v-1.3zM369.2 136.4h.5M370.2 135.6h-1v1.6"/>
<path d="M51.4 154.1l-.2-.3h-.6l-.3 .3v1.1l.3 .2h.6l.2-.2v-.6h-.5M53.1 153.8v1.6l-1.1-1.6v1.6M53.6 153.8h.8l.3 .3v1.1l-.3 .2h-.8zM55.4 144.5h.8l.3-.3v-.5l-.3-.3h-.8v1.6M55.4 146.2l.6-.5v1.6M55.4 147.3h1.1M56 144.5l.5 .5M57.1 143.9l.5-.5v1.6M57.1 145h1M58.1 145.9v1.1l-.2 .3h-.6l-.2-.3M58.1 145.9l-.2-.2h-.6l-.2 .2v1.1M58.1 145.9l-1 1.1"/>
<path d="M58.7 143.9l.5-.5v1.6M58.7 145.7v1.6M58.7 145h1.1M59.5 146.2l-.8 .5 .8 .6M61.6 146.4l-.3-.2h-.5l-.3 .2v1.1l.3 .3h.5l.3-.3v-.5h-.6M63.2 146.2v1.6l-1.1-1.6v1.6M63.8 146.2h.8l.3 .2v1.1l-.3 .3h-.8zM73.7 143.6v1.6M74 144.4l.8 .8M74.8 143.6l-1.1 1.1M75.4 145.2h1.1M75.4 144.2l.5-.6v1.6"/>
<path d="M81.9 146.4l-.3-.2h-.5l-.3 .2v1.1l.3 .3h.5l.3-.3v-.5h-.5M83.5 146.2v1.6l-1-1.6v1.6M84.1 146.2h.8l.3 .2v1.1l-.3 .3h-.8zM98.6 158.6l.3-.3h.5l.3 .3v.3l-1.1 1.1h1.1M100.2 159.7h.3v.3h-.3zM102.1 158.3h-1.1v.9l.9-.3 .2 .3v.5l-.2 .3h-.6l-.3-.3M102.7 160v-1.1l.5-.6 .6 .6v1.1M102.7 159.2h1.1M112.8 152.8v1.1l.6 .5 .5-.5v-1.1M114.4 154.4h.6M114.4 152.8h.6M114.7 152.8v1.6"/>
<path d="M116.6 152.8v1.6l-1.1-1.6v1.6M116.9 140.2v-1.1l.6-.5 .5 .5v1.1M265.2 157.8v1.1l.5 .6 .6-.6v-1.1M266.8 159.5h.6M266.8 157.8h.6M267.1 157.8v1.7M269 157.8v1.7l-1.1-1.7v1.7M333.3 143.9l-.2-.3h-.6l-.2 .3v1.1l.2 .2h.6l.2-.2v-.6h-.5M335 143.6v1.6l-1.1-1.6v1.6M335.5 143.6h.8l.3 .3v1.1l-.3 .2h-.8zM361.3 143.9l-.3-.3h-.5l-.3 .3v1.1l.3 .2h.5l.3-.2v-.6h-.6M362.9 143.6v1.6l-1.1-1.6v1.6"/>
<path d="M363.5 143.6h.8l.3 .3v1.1l-.3 .2h-.8zM50.3 167.1v-1.6l.6 .5 .5-.5v1.6M52 167.1v-1.1l.5-.5 .6 .5v1.1M52 166.3h1.1M53.6 166.3h.8M53.6 165.5h.8l.3 .2-.3 .6 .3 .5-.3 .3h-.8zM55.2 166.3h.9l.2 .5-.2 .3h-.6l-.3-.3zM56.3 165.5l-1.1 .8M58 166.3h-1.1l.8-.8v1.6M58.5 165.7l.3-.2h.6l.2 .2v1.1l-.2 .3h-.6l-.3-.3zM59.1 166.6l.5 .5M60.5 168.3h.8l.3-.2v-.6l-.3-.3h-.8v1.7"/>
<path d="M60.5 170.9h.8l.3-.3v-.5l-.3-.3h-.8v1.6M60.5 173.4h.8l.3-.3v-.5l-.3-.3h-.8v1.6M60.5 176h.8l.3-.3v-.6l-.3-.2h-.8v1.6M60.5 178.5h.8l.3-.3v-.5l-.3-.3h-.8v1.6M62.1 167.8l.6-.6v1.7M62.1 170.3l.6-.5v1.6M62.1 172.9l.6-.6v1.6M62.1 175.4l.6-.5v1.6M62.1 177.9l.6-.5v1.6M62.1 168.9h1.1M62.1 171.4h1.1M62.1 173.9h1.1"/>
<path d="M62.1 176.5h1.1M62.1 179h1.1M63.8 168.1h1.1M63.8 170.6h1.1M63.8 173.1h1.1M63.8 175.7h1.1M63.8 178.2h1.1M65.4 168.1h1.1M65.4 168.9v-1.1l.6-.6 .5 .6v1.1M65.4 171.4v-1.1l.6-.5 .5 .5v1.1M65.4 173.9v-1l.6-.6 .5 .6v1M65.4 176.5v-1.1l.6-.5 .5 .5v1.1"/>
<path d="M65.4 179v-1.1l.6-.5 .5 .5v1.1M65.4 170.6h1.1M65.4 173.1h1.1M65.4 175.7h1.1M65.4 178.2h1.1M67.1 170.1l.2-.3h.6l.2 .3v.2l-1 1.1h1M67.1 172.6l.2-.3h.6l.2 .3-.2 .5M67.1 168.9h1M67.1 167.8l.5-.6v1.7M67.6 173.1h.3M67.9 173.1l.2 .3-.2 .5h-.6l-.2-.2M68.1 167.1v-1.6l.6 .5 .5-.5v1.6"/>
<path d="M68.1 177.4h-1v.8l.8-.3 .2 .3v.6l-.2 .2h-.6l-.2-.2M68.1 175.7h-1l.8-.8v1.6M68.1 179.9l-1 .9M69.8 166.3h1M69.8 167.1v-1.1l.5-.5 .5 .5v1.1M71.4 166.3h.8M71.4 165.5h.8l.3 .2-.3 .6 .3 .5-.3 .3h-.8zM73 166.3h.9l.2 .5-.2 .3h-.6l-.3-.3zM74.1 165.5l-1.1 .8M75.8 166.3h-1.1l.8-.8v1.6M76.6 165.5h.5l.3 .2v1.1l-.3 .3h-.5l-.3-.3v-1.1zM76.9 166.6l.5 .5"/>
<path d="M78.3 173.4h.8l.3-.3v-.5l-.3-.3h-.8v1.6M78.3 168.3h.8l.3-.2v-.6l-.3-.3h-.8v1.7M78.3 170.9h.8l.3-.3v-.5l-.3-.3h-.8v1.6M78.3 176h.8l.3-.3v-.6l-.3-.2h-.8v1.6M78.3 178.5h.8l.3-.3v-.5l-.3-.3h-.8v1.6M79.9 168.9h1.1M79.9 171.4h1.1M79.9 173.9h1.1M79.9 176.5h1.1M79.9 179h1.1M79.9 167.8l.6-.6v1.7M79.9 170.3l.6-.5v1.6"/>
<path d="M79.9 172.9l.6-.6v1.6M79.9 175.4l.6-.5v1.6M79.9 177.9l.6-.5v1.6M81.6 168.1h1M81.6 170.6h1M81.6 173.1h1M81.6 175.7h1M81.6 178.2h1M83.2 167.2h.8l.3 .3-.3 .6 .3 .5-.3 .3h-.8zM83.2 169.8h.8l.3 .3-.3 .5 .3 .5-.3 .3h-.8zM83.2 172.3h.8l.3 .3-.3 .5 .3 .6-.3 .2h-.8zM83.2 174.9h.8l.3 .2-.3 .6 .3 .5-.3 .3h-.8z"/>
<path d="M83.2 177.4h.8l.3 .3-.3 .5 .3 .6-.3 .2h-.8zM83.2 179.9h.8l.3 .3-.3 .6 .3 .5-.3 .3h-.8zM83.2 168.1h.8M83.2 170.6h.8M83.2 173.1h.8M83.2 175.7h.8M83.2 178.2h.8M84.8 167.8l.6-.6v1.7M84.8 168.9h1.1M84.8 170.1l.3-.3h.5l.3 .3v.2l-1.1 1.1h1.1M84.8 172.6l.3-.3h.5l.3 .3-.3 .5M85.4 173.1h.2"/>
<path d="M85.6 173.1l.3 .3-.3 .5h-.5l-.3-.2M85.9 175.7h-1.1l.8-.8v1.6M85.9 177.4h-1.1v.8l.8-.3 .3 .3v.6l-.3 .2h-.5l-.3-.2M85.9 179.9l-1.1 .9M97.8 167.6h.9l.2-.3v-.5l-.2-.3h-.9v1.6M99.5 166.5h1.1M100 166.5v1.6M102.2 166.8l-.3-.3h-.5l-.3 .3v1l.3 .3h.5l.3-.3M179.9 175.2h.8l.3-.3v-.5l-.3-.3h-.8v1.6M181 171.8l-.3-.2h-.6l-.2 .2v1.1l.2 .3h.6l.3-.3M181 179.5l-.3-.3h-.6l-.2 .3v1l.2 .3h.6l.3-.3M181 169.3l-.3-.3h-.6l-.2 .3v1.1l.2 .2h.6l.3-.2"/>
<path d="M181 176.9l-.3-.3h-.6l-.2 .3v1.1l.2 .3h.6l.3-.3M181.5 171.8l.3-.2h.5l.3 .2v1.1l-.3 .3h-.5l-.3-.3zM181.5 169.3l.3-.3h.5l.3 .3v1.1l-.3 .2h-.5l-.3-.2zM181.5 174.1v1.6l.6-.5 .5 .5v-1.6M181.5 178.3v-1.1l.6-.6 .5 .6v1.1M181.5 177.5h1.1M183.1 175.2h.9l.2-.3v-.5l-.2-.3h-.9v1.6M183.7 175.2l.5 .5M184.2 169v1.6l-1.1-1.6v1.6M184.2 171.6v1.6l-1.1-1.6v1.6M184.2 176.6v1.7l-1.1-1.7v1.7M184.2 179.2v1.6l-1.1-1.6v1.6"/>
<path d="M184.8 174.9h1.1M184.8 177.5h1.1M185.9 171.8l-.3-.2h-.5l-.3 .5 .3 .3h.5l.3 .5-.3 .3h-.5l-.3-.3M185.9 169.3l-.3-.3h-.5l-.3 .6 .3 .2h.5l.3 .6-.3 .2h-.5l-.3-.2M186.4 169.8h1.1M186.4 172.4h1.1M186.4 176.6h1.1M187 176.6v1.7M187.5 174.4l-.3-.3h-.5l-.3 .5 .3 .3h.5l.3 .6-.3 .2h-.5l-.3-.2M188 174.9h.6M188 172.7h.9l.2-.3v-.6l-.2-.2h-.9v1.6M188 169h1.1"/>
<path d="M188 176.6l1.1 1.7M188 179.2l1.1 1.6M188.6 169v1.6M188.6 172.7l.5 .5M189.1 174.1h-1.1v1.6h1.1M189.1 176.6l-1.1 1.7M189.1 179.2l-1.1 1.6M189.7 169l1.1 1.6M189.7 171.6l1.1 1.6M190.8 174.1v1.6l-1.1-1.6v1.6M190.8 169l-1.1 1.6M190.8 171.6l-1.1 1.6"/>
<path d="M192.4 174.4l-.2-.3h-.6l-.3 .3 .3 .5h.6l.2 .3-.2 .5h-.6l-.3-.2M193 174.9h.5M194.1 174.1h-1.1v1.6h1.1M217.7 175.3l.3-.2 .7 .2-1 1.2h1M217.7 177.9l.7-.2 .3 .2-.3 .5M217.7 174h1M217.7 173l.5-.4v1.4M218.2 178.4h.2M218.4 178.4l.3 .2-.3 .4-.7-.2M218.7 170.3v.9l-.3 .2-.7-.2M218.7 170.3l-.3-.3-.7 .3v.9M218.7 170.3l-1 .9"/>
<path d="M220.1 177.7l-.9 1.3M220.1 172.6l-.9 1.4M220.1 170l-.9 1.4M220.6 171h.7l.2-.7-.2-.3h-.7v1.4M220.6 172.6h.9M221 172.6v1.4M221 171l.5 .4M221.5 177.9l-.2-.2-.7 .2v.9l.2 .2 .7-.2M222 179v-.9l.4-.4 .5 .4v.9M222 178.4h.9M222 172.6l.9 1.4M222 170l.9 1.4"/>
<path d="M222.9 172.6l-.9 1.4M222.9 170l-.9 1.4M223.4 171.4h.9M223.4 174h.9M223.4 173l.4-.4v1.4M223.4 170.5l.4-.5v1.4M224.3 177.7v1.3l-.9-1.3v1.3M224.8 178.4h.9M225.7 172.6l-.9 1.4M225.7 170l-.9 1.4M226.2 177.7h.9M226.2 172.6h.9"/>
<path d="M226.2 170h.9M226.6 170v1.4M226.6 172.6v1.4M226.6 177.7v1.3M227.6 177.7l.9 1.3M227.6 163.2l.2 1.1 .5-.2v-.9M228.5 177.7l-.9 1.3M229.5 163.2h-.7v.5l.4-.1 .3 .1-.2 .6-.5-.2M229.9 177.7l-.9 1.3M230.4 178.6h.7l.2-.7-.2-.2h-.7v1.3M231.8 177.7v1.3l.4-.4 .5 .4v-1.3M233.2 179v-1.3l.4 .4 .5-.4v1.3"/>
<path d="M243 167.5v.9l.5 .5 .4-.5v-.9M243 175.1v.9l.5 .5 .4-.5v-.9M243.7 172.8l.7-.2 .2 .2-.2 .5M244.2 173.3h.2M244.4 167.5v1.2l.2 .2 .7-.2v-1.2M244.4 173.3l.2 .2-.2 .5-.7-.3M244.4 175.8h.7M244.4 175.1h.7l.2 .2-.2 .5 .2 .5-.2 .2h-.7zM244.9 170v1l.5 .4 .4-.4v-1M245.1 173.7h.3v.3h-.3zM245.3 177.9l-.2-.2-.7 .2v.9l.7 .2 .2-.6h-.4M245.8 172.8l.7-.2 .3 .2-.3 .5"/>
<path d="M245.8 176.5v-.9l.5-.5 .5 .5v.9M245.8 175.8h1M246.3 171.4h.5M246.3 170h.5M246.3 173.3h.2M246.5 173.3l.3 .2-.3 .5-.7-.3M246.5 170v1.4M246.8 167.7l-.3-.2-.7 .2 .3 .5 .7 .2-.3 .5-.7-.2M246.8 177.7v1.3l-1-1.3v1.3M247.2 167.5h.7l.3 .2-.3 .5 .3 .5-.3 .2h-.7zM247.2 177.7h.7l.3 .2v.9l-.3 .2h-.7zM247.2 175.1h1"/>
<path d="M247.2 172.6v.9l.5 .5 .5-.5v-.9M247.2 168.2h.7M247.7 175.1v1.4M248.2 170v1.4l-1-1.4v1.4M316 173.1v1.1l.5 .5 .6-.5v-1.1M317.6 174.7h.6M317.6 173.1h.6M317.9 173.1v1.6M319.8 173.1v1.6l-1.1-1.6v1.6M347.6 173.9v1.6l.3 .3h.6l.3-.3v-1.6M350.7 174.9h-1.2l.9-1v1.9M35.1 185.9v-1.6l.5 .5 .6-.5v1.6"/>
<path d="M35.1 188.4v-1.6l.5 .5 .6-.5v1.6M35.1 191v-1.7l.5 .6 .6-.6v1.7M35.1 193.5v-1.6l.5 .5 .6-.5v1.6M37 186.8h.5l.3 .3v1.1l-.3 .2h-.5l-.3-.2v-1.1zM37 184.3h.5l.3 .2v1.1l-.3 .3h-.5l-.3-.3v-1.1zM37 189.3h.5l.3 .3v1.1l-.3 .3h-.5l-.3-.3v-1.1zM37 191.9h.5l.3 .3v1l-.3 .3h-.5l-.3-.3v-1zM38.4 184.3h.8l.3 .2v1.1l-.3 .3h-.8zM38.4 186.8h.8l.3 .3v1.1l-.3 .2h-.8zM38.4 189.3h.8l.3 .3v1.1l-.3 .3h-.8zM38.4 191.9h.8l.3 .3v1l-.3 .3h-.8zM40 192.7h1.1"/>
<path d="M40 190.2h1.1M40 185.1h1.1M40 187.6h1.1M41.7 191v-1.1l.5-.6 .5 .6v1.1M41.7 192.7h1M41.7 190.2h1M41.7 185.1h1M41.7 185.9v-1.1l.5-.5 .5 .5v1.1M41.7 188.4v-1.1l.5-.5 .5 .5v1.1M41.7 193.5v-1.1l.5-.5 .5 .5v1.1M41.7 187.6h1M43.3 189.9l.5-.6v1.7"/>
<path d="M43.3 187.1l.3-.3h.5l.3 .3v.2l-1.1 1.1h1.1M43.3 191h1.1M43.3 184.5l.3-.2h.5l.3 .2-.3 .6M43.8 185.1h.3M44.1 185.1l.3 .2-.3 .6h-.5l-.3-.3M44.4 192.2v1l-.3 .3h-.5l-.3-.3M44.4 192.2l-.3-.3h-.5l-.3 .3v1M44.4 192.2l-1.1 1M60.5 181h.8l.3-.2v-.6l-.3-.3h-.8v1.7M60.5 183.6h.8l.3-.3v-.5l-.3-.3h-.8v1.6M60.5 186.1h.8l.3-.3v-.5l-.3-.3h-.8v1.6M60.5 188.6h.8l.3-.2v-.6l-.3-.2h-.8v1.6"/>
<path d="M60.5 191.2h.8l.3-.3v-.5l-.3-.3h-.8v1.6M60.5 193.7h.8l.3-.2v-.6l-.3-.3h-.8v1.7M60.5 196.3h.8l.3-.3v-.5l-.3-.3h-.8v1.6M60.5 198.8h.8l.3-.3v-.5l-.3-.3h-.8v1.6M62.1 180.5l.6-.6v1.7M62.1 183l.6-.5v1.6M62.1 185.6l.6-.6v1.6M62.1 188.1l.6-.5v1.6M62.1 190.6l.6-.5v1.6M62.1 193.2l.6-.6v1.7M62.1 195.7l.6-.5v1.6M62.1 198.3l.6-.6v1.6"/>
<path d="M62.1 181.6h1.1M62.1 184.1h1.1M62.1 186.6h1.1M62.1 189.2h1.1M62.1 191.7h1.1M62.1 194.3h1.1M62.1 196.8h1.1M62.1 199.3h1.1M63.8 180.8h1.1M63.8 183.3h1.1M63.8 185.8h1.1M63.8 188.4h1.1"/>
<path d="M63.8 190.9h1.1M63.8 193.5h1.1M63.8 196h1.1M63.8 198.5h1.1M65.4 181.6v-1.1l.6-.6 .5 .6v1.1M65.4 184.1v-1.1l.6-.5 .5 .5v1.1M65.4 186.6v-1l.6-.6 .5 .6v1M65.4 189.2v-1.1l.6-.5 .5 .5v1.1M65.4 191.7v-1.1l.6-.5 .5 .5v1.1M65.4 194.3v-1.1l.6-.6 .5 .6v1.1M65.4 196.8v-1.1l.6-.5 .5 .5v1.1M65.4 199.3v-1l.6-.6 .5 .6v1"/>
<path d="M65.4 180.8h1.1M65.4 183.3h1.1M65.4 185.8h1.1M65.4 188.4h1.1M65.4 190.9h1.1M65.4 193.5h1.1M65.4 196h1.1M65.4 198.5h1.1M67.1 180.8h.8l.2 .5-.2 .3h-.6l-.2-.3zM67.1 182.5h1l-1 1.6M67.1 190.6l.5-.5v1.6M67.1 193.2l.5-.6v1.7"/>
<path d="M67.1 195.7l.5-.5v1.6M67.1 198.3l.5-.6v1.6M67.1 191.7h1M67.1 194.3h1M67.1 196.8h1M67.1 199.3h1M67.3 185.8l-.2-.2 .2-.6h.6l.2 .3-.2 .5M67.3 185.8l-.2 .3 .2 .5h.6l.2-.2-.2-.6M67.3 185.8h.6M68.1 188.4h-.8l-.2-.3 .2-.5h.6l.2 .2v1.1l-.2 .3h-.6l-.2-.3M68.7 195.5l.3-.3h.5l.3 .3v.2l-1.1 1.1h1.1M68.7 198l.3-.3h.5l.3 .3-.3 .5"/>
<path d="M68.7 193.2l.5-.6v1.7M68.7 194.3h1.1M69.2 198.5h.3M69.5 198.5l.3 .3-.3 .5h-.5l-.3-.2M69.8 190.4v1.1l-.3 .2h-.5l-.3-.2M69.8 190.4l-.3-.3h-.5l-.3 .3v1.1M69.8 190.4l-1.1 1.1M78.3 186.1h.8l.3-.3v-.5l-.3-.3h-.8v1.6M78.3 191.2h.8l.3-.3v-.5l-.3-.3h-.8v1.6M78.3 193.7h.8l.3-.2v-.6l-.3-.3h-.8v1.7M78.3 181h.8l.3-.2v-.6l-.3-.3h-.8v1.7M78.3 198.8h.8l.3-.3v-.5l-.3-.3h-.8v1.6"/>
<path d="M78.3 183.6h.8l.3-.3v-.5l-.3-.3h-.8v1.6M78.3 188.6h.8l.3-.2v-.6l-.3-.2h-.8v1.6M78.3 196.3h.8l.3-.3v-.5l-.3-.3h-.8v1.6M79.9 181.6h1.1M79.9 184.1h1.1M79.9 186.6h1.1M79.9 189.2h1.1M79.9 191.7h1.1M79.9 194.3h1.1M79.9 196.8h1.1M79.9 199.3h1.1M79.9 180.5l.6-.6v1.7"/>
<path d="M79.9 183l.6-.5v1.6M79.9 185.6l.6-.6v1.6M79.9 188.1l.6-.5v1.6M79.9 190.6l.6-.5v1.6M79.9 193.2l.6-.6v1.7M79.9 195.7l.6-.5v1.6M79.9 198.3l.6-.6v1.6M81.6 180.8h1M81.6 183.3h1M81.6 185.8h1M81.6 188.4h1M81.6 190.9h1"/>
<path d="M81.6 193.5h1M81.6 196h1M81.6 198.5h1M83.2 182.5h.8l.3 .3-.3 .5 .3 .5-.3 .3h-.8zM83.2 185h.8l.3 .3-.3 .5 .3 .6-.3 .2h-.8zM83.2 187.6h.8l.3 .2-.3 .6 .3 .5-.3 .3h-.8zM83.2 190.1h.8l.3 .3-.3 .5 .3 .6-.3 .2h-.8zM83.2 192.6h.8l.3 .3-.3 .6 .3 .5-.3 .3h-.8zM83.2 195.2h.8l.3 .3-.3 .5 .3 .5-.3 .3h-.8zM83.2 197.7h.8l.3 .3-.3 .5 .3 .6-.3 .2h-.8zM83.2 180.8h.8M83.2 183.3h.8"/>
<path d="M83.2 185.8h.8M83.2 188.4h.8M83.2 190.9h.8M83.2 193.5h.8M83.2 196h.8M83.2 198.5h.8M84.8 190.6l.6-.5v1.6M84.8 193.2l.6-.6v1.7M84.8 195.7l.6-.5v1.6M84.8 198.3l.6-.6v1.6M84.8 180.8h.8l.3 .5-.3 .3h-.5l-.3-.3zM84.8 182.5h1.1l-1.1 1.6"/>
<path d="M84.8 191.7h1.1M84.8 194.3h1.1M84.8 196.8h1.1M84.8 199.3h1.1M85.1 185.8l-.3-.2 .3-.6h.5l.3 .3-.3 .5M85.1 185.8l-.3 .3 .3 .5h.5l.3-.2-.3-.6M85.1 185.8h.5M85.9 188.4h-.8l-.3-.3 .3-.5h.5l.3 .2v1.1l-.3 .3h-.5l-.3-.3M86.5 194.3h1M86.5 195.5l.2-.3h.6l.2 .3v.2l-1 1.1h1M86.5 198l.2-.3h.6l.2 .3-.2 .5M86.5 193.2l.5-.6v1.7"/>
<path d="M87 198.5h.3M87.3 198.5l.2 .3-.2 .5h-.6l-.2-.2M87.5 190.4l-.2-.3h-.6l-.2 .3v1.1M87.5 190.4v1.1l-.2 .2h-.6l-.2-.2M87.5 190.4l-1 1.1M179.9 188.4v-1.6l.5 .5 .6-.5v1.6M179.9 185.9v-1.6l.5 .5 .6-.5v1.6M179.9 191v-1.7l.5 .6 .6-.6v1.7M179.9 193.5v-1.6l.5 .5 .6-.5v1.6M181.5 187.1l.3-.3h.5l.3 .3v1.1l-.3 .2h-.5l-.3-.2zM181.5 184.5l.3-.2h.5l.3 .2v1.1l-.3 .3h-.5l-.3-.3zM181.5 192.2l.3-.3h.5l.3 .3v1l-.3 .3h-.5l-.3-.3z"/>
<path d="M181.5 189.6l.3-.3h.5l.3 .3v1.1l-.3 .3h-.5l-.3-.3zM181.5 180.8v-1.1l.6-.5 .5 .5v1.1M181.5 180h1.1M183.1 189.3h.9l.2 .3v1.1l-.2 .3h-.9zM183.1 191.9h.9l.2 .3v1l-.2 .3h-.9zM183.1 184.3h.9l.2 .2v1.1l-.2 .3h-.9zM183.1 186.8h.9l.2 .3v1.1l-.2 .2h-.9zM184.8 192.7h1.1M184.8 190.2h1.1M184.8 185.1h1.1M184.8 187.6h1.1M184.8 180h1.1"/>
<path d="M186.4 180.3h.8l.3-.3v-.5l-.3-.3h-.8v1.6M186.4 185.9v-1.1l.6-.5 .5 .5v1.1M186.4 188.4v-1.1l.6-.5 .5 .5v1.1M186.4 191v-1.1l.6-.6 .5 .6v1.1M186.4 193.5v-1.1l.6-.5 .5 .5v1.1M186.4 192.7h1.1M186.4 190.2h1.1M186.4 185.1h1.1M186.4 187.6h1.1M187 180.3l.5 .5M188 184.5l.3-.2h.6l.2 .2-.2 .6M188 187.1l.3-.3h.6l.2 .3v.2l-1.1 1.1h1.1"/>
<path d="M188 191h1.1M188 189.9l.6-.6v1.7M188.6 185.1h.3M188.9 185.1l.2 .2-.2 .6h-.6l-.3-.3M189.1 192.2v1l-.2 .3h-.6l-.3-.3M189.1 192.2l-.2-.3h-.6l-.3 .3v1M189.1 192.2l-1.1 1M217.7 186h.7l.3 .4-.7 .3zM217.7 187.8h1l-1 1.4M217.7 196.8h1M217.7 199.4h1M217.7 195.9l.5-.5v1.4"/>
<path d="M217.7 198.4l.5-.4v1.4M218 191.1l-.3-.3 .3-.4 .7 .2-.3 .5M218 191.1l-.3 .2 .3 .4 .7-.2-.3-.4M218 191.1h.4M218.7 182.7h-1v.7l.5-.2 .5 .2-.3 .7-.7-.2M218.7 193.6h-.7l-.3-.2 .3-.5 .7 .2v1l-.3 .2-.7-.2M218.7 185.3l-1 .7M218.7 180.9h-1l.7-.7v1.4M219.2 199.4h.9M219.2 198.4l.4-.4v1.4M220.1 195.7v.9l-.2 .2-.7-.2M220.1 195.7l-.2-.3-.7 .3v.9"/>
<path d="M220.1 195.7l-.9 .9M220.1 192.9l-.9 1.4M220.1 190.4l-.9 1.3M220.1 187.8l-.9 1.4M220.1 185.3l-.9 1.4M220.1 182.7l-.9 1.4M220.1 180.2l-.9 1.4M220.6 193.8h.7l.2-.7-.2-.2h-.7v1.4M220.6 183.7h.7l.2-.7-.2-.3h-.7v1.4M220.6 188.7h.7l.2-.7-.2-.2h-.7v1.4M220.6 190.4h.9M220.6 186.2h.7l.2-.7-.2-.2h-.7v1.4"/>
<path d="M221 193.8l.5 .5M221 190.4v1.3M221 188.7l.5 .5M221.5 180.4l-.2-.2-.7 .2v1l.2 .2 .7-.2M221.5 198l-.9 1.4M221.5 195.4l-.9 1.4M222 199.4v-1.4l.4 .4 .5-.4v1.4M222 195.4h.9M222 181.6v-.9l.4-.5 .5 .5v.9M222 182.7v1.4l.4-.4 .5 .4v-1.4M222 185.3v1.4l.4-.5 .5 .5v-1.4M222 192.9l.9 1.4"/>
<path d="M222 190.4l.9 1.3M222 187.8l.9 1.4M222 180.9h.9M222.4 195.4v1.4M222.9 192.9l-.9 1.4M222.9 190.4l-.9 1.3M222.9 187.8l-.9 1.4M223.4 188l.6-.2 .3 .2-.3 .5M223.4 190.6l.6-.2 .3 .2-.3 .5M223.4 193.1l.2-.2 .7 .2-.9 1.2h.9M223.4 198.2l.2-.2 .7 .2v.9l-.3 .3-.6-.3zM223.4 184.1v-1.4l.4 .5 .5-.5v1.4"/>
<path d="M223.4 186.7v-1.4l.4 .4 .5-.4v1.4M223.4 195.4l.9 1.4M223.8 191.1h.2M223.8 188.5h.2M224 191.1l.3 .2-.3 .4-.6-.2M224 188.5l.3 .2-.3 .5-.6-.2M224.3 180.2v1.4l-.9-1.4v1.4M224.3 195.4l-.9 1.4M224.8 195.7l.2-.3 .7 .3-.9 1.1h.9M224.8 180.9h.9M225.7 198.2l-.2-.2-.7 .2 .2 .5 .7 .2-.2 .5-.7-.3M225.7 192.9l-.9 1.4"/>
<path d="M226.2 193.8h.7l.2-.7-.2-.2h-.7v1.4M226.2 199.4h.4M226.2 198h.4M226.2 181.1h.7l.2-.7-.2-.2h-.7v1.4M226.4 198v1.4M226.6 181.1l.5 .5M227.1 195.4l-.9 1.4M227.6 196.4h.7l.2-.7-.2-.3h-.7v1.4M227.6 192.9v1.4l.4-.5 .5 .5v-1.4M227.6 180.2l.9 1.4M228.5 180.2l-.9 1.4M229 195.4v1.4l.4-.4 .5 .4v-1.4"/>
<path d="M229 194.3v-1.4l.4 .5 .5-.5v1.4M229.9 180.2l-.9 1.4M230.4 181.1h.7l.2-.7-.2-.2h-.7v1.4M230.4 196.8v-1.4l.4 .5 .5-.5v1.4M231.8 180.2v1.4l.4-.5 .5 .5v-1.4M233.2 181.6v-1.4l.4 .5 .5-.5v1.4M238.8 196.1h.9M238.8 196.8v-.9l.5-.5 .4 .5v.9M240.2 195.9l.5-.5v1.4M240.2 196.8h1M242.5 196.1h-.9l.7-.7v1.4M243 191.7v-.9l.5-.4 .4 .4v.9"/>
<path d="M243 189.2v-.9l.5-.5 .4 .5v.9M243 191.1h.9M243 188.5h.9M243.9 195.4l-.9 1.4M244.4 183.7h.7l.2-.7-.2-.3h-.7v1.4M244.4 188.7h.7l.2-.7-.2-.2h-.7v1.4M244.4 195.4h.7l.2 .3v.9l-.2 .2h-.7zM244.9 188.7l.4 .5M245.3 190.6l-.2-.2-.7 .2v.9l.7 .2 .2-.6h-.4M245.8 196.8v-.9l.5-.5 .5 .5v.9M245.8 196.1h1M245.8 188.5h.5"/>
<path d="M246.8 183l-.3-.3-.7 .3v.9l.7 .2 .3-.7h-.5M246.8 190.4v1.3l-1-1.3v1.3M246.8 187.8h-1v1.4h1M247.2 190.4h.7l.3 .2v.9l-.3 .2h-.7zM247.2 188.5h.5M247.2 184.1v-1.4l.5 .5 .5-.5v1.4M248.2 195.7l-.3-.3-.7 .3v.9l.3 .2 .7-.2M248.2 187.8h-1v1.4M302.9 187.1l-.3-.3h-.6l-.2 .3v1.1l.2 .2h.6l.3-.2M303.4 188.4v-1.1l.6-.5 .5 .5v1.1M303.4 187.6h1.1M306.1 186.8v1.6l-1-1.6v1.6"/>
<path d="M306.7 187.6h1.1M308.3 186.8h1.1M308.9 186.8v1.6M309.4 197l.5-.6v1.7M309.4 198.1h1.1M309.4 195.3h.8l.3-.3v-.5l-.3-.3h-.8v1.6M309.9 195.3l.6 .5M310 186.8l1 1.6M311 186.8l-1 1.6M312.1 196.7v1.1l-.3 .3h-.5l-.3-.3M312.1 195h-.8l-.3-.3 .3-.5h.5l.3 .3v1l-.3 .3h-.5l-.3-.3M312.1 196.7l-.3-.3h-.5l-.3 .3v1.1"/>
<path d="M312.1 196.7l-1.1 1.1M312.7 196.4v1.7M313.5 197l-.8 .5 .8 .6M318.5 197.1l.6-.5v1.6M318.5 198.2h1.1M319.6 191.8l-.3-.3h-.5l-.3 .3v1l.3 .3h.5l.3-.3M320.2 192.3h.8l.3 .5-.3 .3h-.6l-.2-.3zM321.3 196.8v1.1l-.3 .3h-.6l-.2-.3M321.3 196.8l-.3-.2h-.6l-.2 .2v1.1M321.3 196.8l-1.1 1.1M321.3 191.5l-1.1 .8M322.9 196.8v1.1l-.3 .3h-.5l-.3-.3"/>
<path d="M322.9 196.8l-.3-.2h-.5l-.3 .2v1.1M322.9 196.8l-1.1 1.1M323.4 198.2v-1.1h.9l.2 .3v.8M325.1 197.4h.5M326.2 196.6h-1.1v1.6M336.1 181.8l.7-.2 .3 .2-.3 .5M336.1 194.5l.3-.2 .7 .2-1 1.2h1M336.1 187.2l.5-.5v1.4M336.1 188.1h1M336.4 189.9l-.3-.2 .3-.5 .7 .3-.3 .4M336.4 189.9l-.3 .3 .3 .4 .7-.2-.3-.5M336.4 189.9h.4"/>
<path d="M336.6 182.3h.2M336.8 182.3l.3 .2-.3 .5-.7-.2M342.2 182.7v1l.5 .4 .4-.4v-1M342.2 191.3h.7l.2-.2-.2-.7h-.7v1.3M342.2 195.4v1l.5 .4 .4-.4v-1M342.2 187.8h.9M342.7 187.8v1.4M342.7 191.3l.4 .4M343.6 182.7h.7l.2 .3v.9l-.2 .2h-.7zM343.6 187.8l.9 1.4M344.5 190.6l-.2-.2-.7 .2 .2 .5 .7 .2-.2 .4-.7-.2M344.5 195.7l-.2-.3-.7 .3 .2 .4 .7 .3-.2 .4-.7-.2"/>
<path d="M344.5 187.8l-.9 1.4M345 187.8h.7l.2 .2v1l-.2 .2h-.7zM345 182.7h.7l.2 .3v.9l-.2 .2h-.7zM345.9 195.7l-.2-.3-.7 .3 .2 .4 .7 .3-.2 .4-.7-.2M357.3 185.3v.9l.5 .5 .4-.5v-.9M358.2 190.6l-.2-.2-.7 .2v.9l.2 .2 .7-.2M358.2 193.1l-.2-.2-.7 .2v1l.2 .2 .7-.2M358.7 183.7h.7l.2-.3-.2-.7h-.7v1.4M358.7 186.2h.7l.2-.2-.2-.7h-.7v1.4M358.7 191.7v-.9l.5-.4 .4 .4v.9M358.7 194.3v-.9l.5-.5 .4 .5v.9M358.7 191.1h.9"/>
<path d="M358.7 193.6h.9M359.2 183.7l.4 .4M359.2 186.2l.4 .5M360.1 182.7l.9 1.4M360.1 186h.5M361 185.3h-.9v1.4h.9M361 190.4v1.3l-.9-1.3v1.3M361 192.9v1.4l-.9-1.4v1.4M361 182.7l-.9 1.4M361.5 182.7h.7l.2 .3v.9l-.2 .2h-.7zM361.5 190.4v1.3h.9M361.5 192.9v1.4"/>
<path d="M361.5 186h.5M361.5 193.6h.9M362.4 185.3h-.9v1.4M362.4 192.9v1.4M367.6 189.9h.7l.2 .5-.7 .2zM367.6 191.8h.9l-.9 1.4M368.5 182.3h-.9l.7-.7v1.4M368.5 184.1h-.9v.7l.4-.2 .5 .2-.2 .7-.7-.2M368.5 189.2l-.9 .7M388.1 189.3v1.7h1.1M388.1 191.9v1.6h1.1M390.8 189.6l-.2-.3h-.6l-.2 .3v1.1l.2 .3h.6l.2-.3"/>
<path d="M390.8 192.2l-.2-.3h-.6l-.2 .3v1l.2 .3h.6l.2-.3M391.4 191v-1.1l.5-.6 .6 .6v1.1M391.4 193.5v-1.1l.5-.5 .6 .5v1.1M391.4 192.7h1.1M391.4 190.2h1.1M394.1 189.3v1.7l-1.1-1.7v1.7M394.1 191.9v1.6l-1.1-1.6v1.6M394.7 192.7h1.1M394.7 190.2h1.1M396.3 189.3v1.7h1.1M396.3 191.9v1.6M396.3 192.7h1.1"/>
<path d="M397.4 191.9v1.6M35.1 214.7v1.7h1.1M35.1 217.3v1.6h1.1M37.8 215l-.3-.3h-.5l-.3 .3v1.1l.3 .3h.5l.3-.3M37.8 217.6l-.3-.3h-.5l-.3 .3v1l.3 .3h.5l.3-.3M38.4 216.4v-1.1l.5-.6 .6 .6v1.1M38.4 215.5h1.1M38.4 218.1h1.1M38.4 218.9v-1.1l.5-.5 .6 .5v1.1M41.1 214.7v1.7l-1.1-1.7v1.7M41.1 217.3v1.6l-1.1-1.6v1.6M41.7 215.5h1"/>
<path d="M41.7 218.1h1M43.3 215.5h1.1M43.3 214.7v1.7M43.3 217.3v1.6h1.1M44.4 214.7v1.7M60.5 201.3h.8l.3-.2v-.6l-.3-.2h-.8v1.6M60.5 203.9h.8l.3-.3v-.5l-.3-.3h-.8v1.6M60.5 206.4h.8l.3-.3v-.5l-.3-.3h-.8v1.7M60.5 209h.8l.3-.3v-.5l-.3-.3h-.8v1.6M60.5 211.5h.8l.3-.3v-.5l-.3-.3h-.8v1.6M60.5 214h.8l.3-.2v-.6l-.3-.2h-.8v1.6M60.5 216.6h.8l.3-.3v-.5l-.3-.3h-.8v1.6"/>
<path d="M60.5 219.1h.8l.3-.3v-.5l-.3-.3h-.8v1.7M62.1 200.8l.6-.5v1.6M62.1 203.3l.6-.5v1.6M62.1 205.9l.6-.6v1.7M62.1 208.4l.6-.5v1.6M62.1 211l.6-.6v1.6M62.1 213.5l.6-.5v1.6M62.1 216l.6-.5v1.6M62.1 218.6l.6-.6v1.7M62.1 201.9h1.1M62.1 204.4h1.1M62.1 207h1.1"/>
<path d="M62.1 209.5h1.1M62.1 212h1.1M62.1 214.6h1.1M62.1 217.1h1.1M62.1 219.7h1.1M63.8 201.1h1.1M63.8 203.6h1.1M63.8 206.1h1.1M63.8 208.7h1.1M63.8 211.2h1.1M63.8 213.8h1.1M63.8 216.3h1.1"/>
<path d="M63.8 218.8h1.1M65.4 204.4v-1.1l.6-.5 .5 .5v1.1M65.4 214.6v-1.1l.6-.5 .5 .5v1.1M65.4 201.9v-1.1l.6-.5 .5 .5v1.1M65.4 207v-1.1l.6-.6 .5 .6v1.1M65.4 209.5v-1.1l.6-.5 .5 .5v1.1M65.4 212v-1l.6-.6 .5 .6v1M65.4 217.1v-1.1l.6-.5 .5 .5v1.1M65.4 219.7v-1.1l.6-.6 .5 .6v1.1M65.4 201.1h1.1M65.4 203.6h1.1M65.4 206.1h1.1"/>
<path d="M65.4 208.7h1.1M65.4 211.2h1.1M65.4 213.8h1.1M65.4 216.3h1.1M65.4 218.8h1.1M67.1 215.8l.2-.3h.6l.2 .3v.2l-1 1.1h1M67.1 218.3l.2-.3h.6l.2 .3v.3l-1 1.1h1M67.1 200.8l.5-.5v1.6M67.1 203.3l.5-.5v1.6M67.1 205.9l.5-.6v1.7M67.1 208.4l.5-.5v1.6M67.1 211l.5-.6v1.6"/>
<path d="M67.1 213.5l.5-.5v1.6M67.1 201.9h1M67.1 204.4h1M67.1 207h1M67.1 209.5h1M67.1 212h1M67.1 214.6h1M68.7 206.1h.8l.3 .6-.3 .3h-.5l-.3-.3zM68.7 207.9h1.1l-1.1 1.6M68.7 218.6l.5-.6v1.7M68.7 219.7h1.1M69 211.2l-.3-.2 .3-.6h.5l.3 .3-.3 .5"/>
<path d="M69 211.2l-.3 .3 .3 .5h.5l.3-.2-.3-.6M69 211.2h.5M69.8 202.8h-1.1v.8l.5-.3 .6 .3v.6l-.3 .2h-.5l-.3-.2M69.8 213.8h-.8l-.3-.3 .3-.5h.5l.3 .2v1.1l-.3 .3h-.5l-.3-.3M69.8 215.8v1.1l-.3 .2h-.5l-.3-.2M69.8 215.8l-.3-.3h-.5l-.3 .3v1.1M69.8 201.1h-1.1l.8-.8v1.6M69.8 205.3l-1.1 .8M69.8 215.8l-1.1 1.1M78.3 206.4h.8l.3-.3v-.5l-.3-.3h-.8v1.7M78.3 201.3h.8l.3-.2v-.6l-.3-.2h-.8v1.6M78.3 209h.8l.3-.3v-.5l-.3-.3h-.8v1.6"/>
<path d="M78.3 214h.8l.3-.2v-.6l-.3-.2h-.8v1.6M78.3 203.9h.8l.3-.3v-.5l-.3-.3h-.8v1.6M78.3 211.5h.8l.3-.3v-.5l-.3-.3h-.8v1.6M78.3 216.6h.8l.3-.3v-.5l-.3-.3h-.8v1.6M78.3 219.1h.8l.3-.3v-.5l-.3-.3h-.8v1.7M79.9 201.9h1.1M79.9 204.4h1.1M79.9 207h1.1M79.9 209.5h1.1M79.9 212h1.1M79.9 214.6h1.1M79.9 217.1h1.1"/>
<path d="M79.9 219.7h1.1M79.9 200.8l.6-.5v1.6M79.9 203.3l.6-.5v1.6M79.9 205.9l.6-.6v1.7M79.9 208.4l.6-.5v1.6M79.9 211l.6-.6v1.6M79.9 213.5l.6-.5v1.6M79.9 216l.6-.5v1.6M79.9 218.6l.6-.6v1.7M81.6 201.1h1M81.6 203.6h1M81.6 206.1h1"/>
<path d="M81.6 208.7h1M81.6 211.2h1M81.6 213.8h1M81.6 216.3h1M81.6 218.8h1M83.2 200.3h.8l.3 .2-.3 .6 .3 .5-.3 .3h-.8zM83.2 202.8h.8l.3 .3-.3 .5 .3 .6-.3 .2h-.8zM83.2 205.3h.8l.3 .3-.3 .5 .3 .6-.3 .3h-.8zM83.2 207.9h.8l.3 .3-.3 .5 .3 .5-.3 .3h-.8zM83.2 210.4h.8l.3 .3-.3 .5 .3 .6-.3 .2h-.8zM83.2 213h.8l.3 .2-.3 .6 .3 .5-.3 .3h-.8zM83.2 215.5h.8l.3 .3-.3 .5 .3 .6-.3 .2h-.8z"/>
<path d="M83.2 218h.8l.3 .3-.3 .5 .3 .6-.3 .3h-.8zM83.2 201.1h.8M83.2 203.6h.8M83.2 206.1h.8M83.2 208.7h.8M83.2 211.2h.8M83.2 213.8h.8M83.2 216.3h.8M83.2 218.8h.8M84.8 200.8l.6-.5v1.6M84.8 203.3l.6-.5v1.6M84.8 205.9l.6-.6v1.7"/>
<path d="M84.8 208.4l.6-.5v1.6M84.8 211l.6-.6v1.6M84.8 213.5l.6-.5v1.6M84.8 201.9h1.1M84.8 204.4h1.1M84.8 207h1.1M84.8 209.5h1.1M84.8 212h1.1M84.8 214.6h1.1M84.8 215.8l.3-.3h.5l.3 .3v.2l-1.1 1.1h1.1M84.8 218.3l.3-.3h.5l.3 .3v.3l-1.1 1.1h1.1M86.5 206.1h.8l.2 .6-.2 .3h-.6l-.2-.3z"/>
<path d="M86.5 207.9h1l-1 1.6M86.5 219.7h1M86.5 218.6l.5-.6v1.7M86.7 211.2l-.2-.2 .2-.6h.6l.2 .3-.2 .5M86.7 211.2l-.2 .3 .2 .5h.6l.2-.2-.2-.6M86.7 211.2h.6M87.5 213.8h-.8l-.2-.3 .2-.5h.6l.2 .2v1.1l-.2 .3h-.6l-.2-.3M87.5 215.8v1.1l-.2 .2h-.6l-.2-.2M87.5 201.1h-1l.8-.8v1.6M87.5 202.8h-1v.8l.5-.3 .5 .3v.6l-.2 .2h-.6l-.2-.2M87.5 215.8l-.2-.3h-.6l-.2 .3v1.1M87.5 215.8l-1 1.1"/>
<path d="M87.5 205.3l-1 .8M179.9 204.6h.5M179.9 206.2h.5M180.1 204.6v1.6M181 204.6h.8l.3 .3v1l-.3 .3h-.8zM181 207.4l-.3-.3h-.6l-.2 .3v1.1l.2 .2h.6l.3-.2M181 209.7v1.6l-1.1-1.6v1.6M181 212.2v1.6l-1.1-1.6v1.6M181 214.7v1.7l-1.1-1.7v1.7M181 217.3v1.6l-1.1-1.6v1.6M181.5 209.9l.3-.2h.5l.3 .2v1.1l-.3 .3h-.5l-.3-.3zM181.5 212.5l.3-.3h.5l.3 .3v1.1l-.3 .2h-.5l-.3-.2z"/>
<path d="M181.5 215l.3-.3h.5l.3 .3v1.1l-.3 .3h-.5l-.3-.3zM181.5 207.9h1.1M181.5 208.7v-1l.6-.6 .5 .6v1M181.5 219.8v1.6l.6-.5 .5 .5v-1.6M181.8 217.3h.5l.3 .3v1l-.3 .3h-.5l-.3-.3v-1zM182.6 205.4h.5M183.1 212.2h.9l.2 .3v1.1l-.2 .2h-.9zM183.1 209.7h.9l.2 .2v1.1l-.2 .3h-.9zM183.1 214.7h.9l.2 .3v1.1l-.2 .3h-.9zM183.1 217.3h.9l.2 .3v1l-.2 .3h-.9zM183.7 204.6h-1.1v1.6h1.1M184.2 207.1v1.6l-1.1-1.6v1.6"/>
<path d="M184.8 207.9h1.1M184.8 210.5h.5M184.8 213h.5M184.8 215.5h.5M184.8 218.1h.5M185.3 204.6v1.6l-1.1-1.6v1.6M185.9 204.6h1.1M185.9 214.7h-1.1v1.7h1.1M185.9 217.3h-1.1v1.6h1.1M185.9 209.7h-1.1v1.6h1.1M185.9 212.2h-1.1v1.6h1.1M186.4 204.6v1.6"/>
<path d="M186.4 208.7v-1l.6-.6 .5 .6v1M186.4 207.9h1.1M186.4 210.5h1.1M186.4 213h1.1M186.4 215.5h1.1M186.4 218.1h1.1M187.5 204.6h.5M187.5 206.2h.5M187.8 204.6v1.6M188 210.5h1.1M188 213h1.1M188 215.5h1.1"/>
<path d="M188 218.1h1.1M188 211.3v-1.1l.6-.5 .5 .5v1.1M188 213.8v-1.1l.6-.5 .5 .5v1.1M188 216.4v-1.1l.6-.6 .5 .6v1.1M188 218.9v-1.1l.6-.5 .5 .5v1.1M188 219.8v1.6M188.6 205.4h.5M189.1 207.4l-.2-.3h-.6l-.3 .3v1.1l.3 .2h.6l.2-.2M189.1 219.8v1.6M189.7 204.6h-1.1v1.6M189.7 217.6l.3-.3h.5l.3 .3-.3 .5M189.7 215l.3-.3h.5l.3 .3v.3l-1.1 1.1h1.1"/>
<path d="M189.7 219.8v1.4l.3 .2h.5l.3-.2v-1.4M189.7 213.8h1.1M189.7 212.7l.5-.5v1.6M189.7 207.1h1.1M190.2 218.1h.3M190.2 207.1v1.6M190.2 204.6l.6 .8M190.5 218.1l.3 .3-.3 .5h-.5l-.3-.3M190.8 209.9l-1.1 1.1M190.8 205.4v.8M190.8 209.9v1.1l-.3 .3h-.5l-.3-.3M190.8 209.9l-.3-.2h-.5l-.3 .2v1.1"/>
<path d="M191.3 204.6v.3l-.5 .5M191.3 219.8h1.1M191.9 219.8v1.6M193 219.8h.8l.3 .3v1.1l-.3 .2h-.8zM196.2 219.8v1.6l.6-.5 .5 .5v-1.6M199 219.8v1.6l-1.1-1.6v1.6M217.7 216.2l.5-.5v1.4M217.7 218.7l.5-.4v1.4M217.7 201.9h1M217.7 204.4h1M217.7 207h1M217.7 209.5h1"/>
<path d="M217.7 212h1M217.7 214.6h1M217.7 217.1h1M217.7 219.7h1M217.7 201l.5-.5v1.4M217.7 203.5l.5-.5v1.4M217.7 206l.5-.4v1.4M217.7 208.6l.5-.5v1.4M217.7 211.1l.5-.4v1.3M217.7 213.7l.5-.5v1.4M219.2 203.3l.7-.3 .2 .3-.2 .5M219.2 200.7l.2-.2h.5l.2 .2-.9 1.2h.9"/>
<path d="M219.2 211.3h.7l.2 .5-.7 .2zM219.2 213.2h.9l-.9 1.4M219.4 216.4l-.2-.2 .2-.5 .7 .3-.2 .4M219.4 216.4l-.2 .3 .2 .4 .7-.2-.2-.5M219.4 216.4h.5M219.6 203.8h.3M219.9 203.8l.2 .2-.2 .4-.7-.2M220.1 219h-.7l-.2-.3 .2-.4 .7 .2v.9l-.2 .3-.7-.3M220.1 208.1h-.9v.7l.4-.2 .5 .2-.2 .7-.7-.2M220.1 210.7l-.9 .6M220.1 206.3h-.9l.7-.7v1.4M221.5 200.5l-.9 1.4"/>
<path d="M221.5 218.3l-.9 1.4M221.5 215.7l-.9 1.4M221.5 213.2l-.9 1.4M221.5 210.7l-.9 1.3M221.5 208.1l-.9 1.4M221.5 205.6l-.9 1.4M221.5 203l-.9 1.4M222 209.5v-.9l.4-.5 .5 .5v.9M222 207v-1l.4-.4 .5 .4v1M222 214.6v-.9l.4-.5 .5 .5v.9M222 217.1v-.9l.4-.5 .5 .5v.9M222 219.7v-1l.4-.4 .5 .4v1"/>
<path d="M222 201.9v-1.4l.4 .5 .5-.5v1.4M222 212v-.9l.4-.4 .5 .4v.9M222 219h.9M222 216.4h.9M222 213.9h.9M222 211.3h.9M222 208.8h.9M222 206.3h.9M222.9 203.3l-.2-.3-.7 .3 .2 .5 .7 .2-.2 .4-.7-.2M223.4 213.4l.6-.2 .3 .2-.3 .5M223.4 201.9h.4M223.4 209.5h.9"/>
<path d="M223.4 210.9l.2-.2 .7 .2-.9 1.1h.9M223.4 200.5h.4M223.4 208.6l.4-.5v1.4M223.6 200.5v1.4M223.8 213.9h.2M224 213.9l.3 .2-.3 .5-.6-.2M224.3 205.8l-.3-.2-.6 .2v.9M224.3 203.3l-.3-.3-.6 .3v.9l.2 .2 .7-.2M224.3 216.4h-.9l.6-.7v1.4M224.3 218.3h-.9v.7l.4-.3 .5 .3-.3 .7-.6-.3M224.3 205.8v.9l-.3 .3h-.4l-.2-.3M224.3 205.8l-.9 .9"/>
<path d="M224.8 203v1.4M225 203.8l.7 .6M225.2 200.7l-.2-.2h-.5l-.2 .5 .7 .2 .2 .5-.2 .2-.7-.2M225.7 215.7l-.9 1.4M225.7 218.3l-.9 1.4M225.7 213.2l-.9 1.4M225.7 210.7l-.9 1.3M225.7 208.1l-.9 1.4M225.7 203l-.9 1M225.9 200.5h.5l.2 .2v1l-.2 .2-.7-.2v-1zM226.2 218.3h.9M226.2 215.7h.9"/>
<path d="M226.2 213.2h.9M226.2 210.7h.9M226.2 208.1h.9M226.6 208.1v1.4M226.6 210.7v1.3M226.6 213.2v1.4M226.6 215.7v1.4M226.6 218.3v1.4M227.1 203l-.9 1.4M227.6 203v1.4h.9M228.5 218.3l-.9 1.4M228.5 215.7l-.9 1.4"/>
<path d="M229 203.8h.4M229.9 218.5l-.2-.2-.7 .2 .2 .5 .7 .2-.2 .5-.7-.3M229.9 216l-.2-.3-.7 .3 .2 .4 .7 .3-.2 .4-.7-.2M229.9 203h-.9v1.4h.9M230.4 203h.7l.2 .3v.9l-.2 .2h-.7zM230.4 215.7h.7l.2 .3v.9l-.2 .2h-.7zM231.3 218.5l-.2-.2-.7 .2v.9l.2 .3 .7-.3M231.8 217.1v-.9l.4-.5 .5 .5v.9M231.8 218.3v1.4h.9M231.8 216.4h.9M234.1 218.5l-.7-.2-.2 .2v.9M234.1 216l-.7-.3-.2 .3v.9"/>
<path d="M234.1 218.5v.9l-.2 .3-.7-.3M234.1 216v.9l-.2 .2-.7-.2M234.1 218.5l-.9 .9M234.1 216l-.9 .9M244.4 204.4v-.9l.5-.5 .4 .5v.9M244.4 207v-1l.5-.4 .4 .4v1M244.4 206.3h.9M244.4 203.8h.9M245.8 204.4h1M245.8 207h1M245.8 203.5l.5-.5v1.4M245.8 206l.5-.4v1.4"/>
<path d="M247.2 203.5l.5-.5v1.4M247.2 204.4h1M248.2 205.8l-.7-.2-.3 .2v.9M248.2 205.8v.9l-.3 .3h-.4l-.3-.3M248.2 205.8l-1 .9M302.9 209.9l-.3-.2h-.6l-.2 .2v1.1l.2 .3h.6l.3-.3M303.4 211.3v-1.1l.6-.5 .5 .5v1.1M303.4 210.5h1.1M305.4 204.9l-.3-.3h-.5l-.3 .3v1l.3 .3h.5l.3-.3v-.5h-.5M306.1 209.7v1.6l-1-1.6v1.6M306.7 210.5h1.1M307 204.6v1.6l-1.1-1.6v1.6"/>
<path d="M307.6 204.6h.8l.3 .3v1l-.3 .3h-.8zM308.3 210.7h.8l.3-.2v-.6l-.3-.2h-.8v1.6M308.9 210.7l.5 .6M310 209.7l1 1.6M311 209.7l-1 1.6M315.6 204.9l-.3-.3h-.6l-.2 .3v1l.2 .3h.6l.3-.3v-.5h-.6M317.2 204.6v1.6l-1.1-1.6v1.6M317.8 204.6h.8l.2 .3v1l-.2 .3h-.8zM325.7 204.9l-.3-.3h-.5l-.3 .3v1l.3 .3h.5l.3-.3v-.5h-.5M327.3 204.6v1.6l-1-1.6v1.6M327.9 204.6h.8l.3 .3v1l-.3 .3h-.8zM346.9 205.6v-1.9l.6 .6 .6-.6v1.9"/>
<path d="M350.1 204l-.3-.3h-.7l-.3 .3v1.3l.3 .3h.7l.3-.3M350.7 204.9h1l.3-.3v-.6l-.3-.3h-1v1.9M352.7 204l.3-.3h.6l.3 .3v.3l-1.2 1.3h1.2M355.8 203.7h-1.2v.9l.9-.3 .3 .3v.7l-.3 .3h-.6l-.3-.3M357.7 203.7h-1.2v.9l.9-.3 .3 .3v.7l-.3 .3h-.6l-.3-.3M358.4 204.3l.6-.6v1.9M358.4 205.6h1.3M360.3 204.6h1.3M362.2 203.7h.7M362.2 205.6h.7M362.6 203.7v1.9M364.8 203.7l-1.3 1.9"/>
<path d="M366.7 204l-.3-.3h-.6l-.4 .6 .4 .3h.6l.3 .7-.3 .3h-.6l-.4-.3M368.6 203.7v1.9l-1.2-1.9v1.9M60.5 221.7h.8l.3-.3v-.5l-.3-.3h-.8v1.6M60.5 224.2h.8l.3-.3v-.5l-.3-.3h-.8v1.6M60.5 226.7h.8l.3-.2v-.6l-.3-.2h-.8v1.6M60.5 229.3h.8l.3-.3v-.5l-.3-.3h-.8v1.6M60.5 231.8h.8l.3-.3v-.5l-.3-.3h-.8v1.7M60.5 234.4h.8l.3-.3v-.5l-.3-.3h-.8v1.6M60.5 236.9h.8l.3-.3v-.5l-.3-.3h-.8v1.6M60.5 239.4h.8l.3-.2v-.6l-.3-.2h-.8v1.6M62.1 221.1l.6-.5v1.6M62.1 223.7l.6-.6v1.6"/>
<path d="M62.1 226.2l.6-.5v1.6M62.1 228.7l.6-.5v1.6M62.1 231.3l.6-.6v1.7M62.1 233.8l.6-.5v1.6M62.1 236.3l.6-.5v1.6M62.1 238.9l.6-.5v1.6M62.1 222.2h1.1M62.1 224.7h1.1M62.1 227.3h1.1M62.1 229.8h1.1M62.1 232.4h1.1M62.1 234.9h1.1"/>
<path d="M62.1 237.4h1.1M62.1 240h1.1M63.8 236.6h1.1M63.8 221.4h1.1M63.8 223.9h1.1M63.8 226.5h1.1M63.8 229h1.1M63.8 231.5h1.1M63.8 234.1h1.1M63.8 239.2h1.1M65.4 224.7v-1l.6-.6 .5 .6v1M65.4 236.6h1.1"/>
<path d="M65.4 222.2v-1.1l.6-.5 .5 .5v1.1M65.4 227.3v-1.1l.6-.5 .5 .5v1.1M65.4 229.8v-1.1l.6-.5 .5 .5v1.1M65.4 232.4v-1.1l.6-.6 .5 .6v1.1M65.4 234.9v-1.1l.6-.5 .5 .5v1.1M65.4 237.4v-1.1l.6-.5 .5 .5v1.1M65.4 240v-1.1l.6-.5 .5 .5v1.1M65.4 221.4h1.1M65.4 223.9h1.1M65.4 226.5h1.1M65.4 229h1.1M65.4 231.5h1.1"/>
<path d="M65.4 234.1h1.1M65.4 239.2h1.1M67.1 220.9l.2-.3h.6l.2 .3v.2l-1 1.1h1M67.1 223.4l.2-.3h.6l.2 .3v.3l-1 1h1M67.1 225.9l.2-.2h.6l.2 .2v.3l-1 1.1h1M67.1 228.5l.2-.3h.6l.2 .3v.2l-1 1.1h1M67.1 231l.2-.3h.6l.2 .3v.3l-1 1.1h1M67.1 233.6l.2-.3h.6l.2 .3v.2l-1 1.1h1M67.1 236.1l.2-.3h.6l.2 .3v.2l-1 1.1h1M67.1 238.6l.2-.2h.6l.2 .2v.3l-1 1.1h1M68.7 220.9l.3-.3h.5l.3 .3v.2l-1.1 1.1h1.1M68.7 223.4l.3-.3h.5l.3 .3-.3 .5"/>
<path d="M68.7 231.5h.8l.3 .6-.3 .3h-.5l-.3-.3zM68.7 233.3h1.1l-1.1 1.6M69 236.6l-.3-.3 .3-.5h.5l.3 .3-.3 .5M69 236.6l-.3 .3 .3 .5h.5l.3-.2-.3-.6M69 236.6h.5M69.2 223.9h.3M69.5 223.9l.3 .3-.3 .5h-.5l-.3-.2M69.8 228.2h-1.1v.8l.5-.3 .6 .3v.6l-.3 .2h-.5l-.3-.2M69.8 239.2h-.8l-.3-.3 .3-.5h.5l.3 .2v1.1l-.3 .3h-.5l-.3-.3M69.8 226.5h-1.1l.8-.8v1.6M69.8 230.7l-1.1 .8M78.3 226.7h.8l.3-.2v-.6l-.3-.2h-.8v1.6"/>
<path d="M78.3 221.7h.8l.3-.3v-.5l-.3-.3h-.8v1.6M78.3 229.3h.8l.3-.3v-.5l-.3-.3h-.8v1.6M78.3 236.9h.8l.3-.3v-.5l-.3-.3h-.8v1.6M78.3 224.2h.8l.3-.3v-.5l-.3-.3h-.8v1.6M78.3 231.8h.8l.3-.3v-.5l-.3-.3h-.8v1.7M78.3 234.4h.8l.3-.3v-.5l-.3-.3h-.8v1.6M78.3 239.4h.8l.3-.2v-.6l-.3-.2h-.8v1.6M79.9 236.3l.6-.5v1.6M79.9 226.2l.6-.5v1.6M79.9 222.2h1.1M79.9 224.7h1.1M79.9 227.3h1.1"/>
<path d="M79.9 229.8h1.1M79.9 232.4h1.1M79.9 234.9h1.1M79.9 237.4h1.1M79.9 240h1.1M79.9 228.7l.6-.5v1.6M79.9 221.1l.6-.5v1.6M79.9 223.7l.6-.6v1.6M79.9 231.3l.6-.6v1.7M79.9 233.8l.6-.5v1.6M79.9 238.9l.6-.5v1.6M81.6 236.6h1"/>
<path d="M81.6 221.4h1M81.6 223.9h1M81.6 226.5h1M81.6 229h1M81.6 231.5h1M81.6 234.1h1M81.6 239.2h1M83.2 220.6h.8l.3 .3-.3 .5 .3 .5-.3 .3h-.8zM83.2 223.1h.8l.3 .3-.3 .5 .3 .6-.3 .2h-.8zM83.2 225.7h.8l.3 .2-.3 .6 .3 .5-.3 .3h-.8zM83.2 228.2h.8l.3 .3-.3 .5 .3 .6-.3 .2h-.8zM83.2 230.7h.8l.3 .3-.3 .5 .3 .6-.3 .3h-.8z"/>
<path d="M83.2 233.3h.8l.3 .3-.3 .5 .3 .5-.3 .3h-.8zM83.2 235.8h.8l.3 .3-.3 .5 .3 .6-.3 .2h-.8zM83.2 238.4h.8l.3 .2-.3 .6 .3 .5-.3 .3h-.8zM83.2 236.6h.8M83.2 221.4h.8M83.2 223.9h.8M83.2 226.5h.8M83.2 229h.8M83.2 231.5h.8M83.2 234.1h.8M83.2 239.2h.8M84.8 220.9l.3-.3h.5l.3 .3v.2l-1.1 1.1h1.1"/>
<path d="M84.8 233.6l.3-.3h.5l.3 .3v.2l-1.1 1.1h1.1M84.8 236.1l.3-.3h.5l.3 .3v.2l-1.1 1.1h1.1M84.8 223.4l.3-.3h.5l.3 .3v.3l-1.1 1h1.1M84.8 225.9l.3-.2h.5l.3 .2v.3l-1.1 1.1h1.1M84.8 228.5l.3-.3h.5l.3 .3v.2l-1.1 1.1h1.1M84.8 231l.3-.3h.5l.3 .3v.3l-1.1 1.1h1.1M84.8 238.6l.3-.2h.5l.3 .2v.3l-1.1 1.1h1.1M86.5 220.9l.2-.3h.6l.2 .3v.2l-1 1.1h1M86.5 223.4l.2-.3h.6l.2 .3-.2 .5M86.5 231.5h.8l.2 .6-.2 .3h-.6l-.2-.3zM86.5 233.3h1l-1 1.6M86.7 236.6h.6"/>
<path d="M86.7 236.6l-.2-.3 .2-.5h.6l.2 .3-.2 .5M86.7 236.6l-.2 .3 .2 .5h.6l.2-.2-.2-.6M87 223.9h.3M87.3 223.9l.2 .3-.2 .5h-.6l-.2-.2M87.5 228.2h-1v.8l.5-.3 .5 .3v.6l-.2 .2h-.6l-.2-.2M87.5 226.5h-1l.8-.8v1.6M87.5 239.2h-.8l-.2-.3 .2-.5h.6l.2 .2v1.1l-.2 .3h-.6l-.2-.3M87.5 230.7l-1 .8M179.9 220.9h.8l.3-.3v-.5l-.3-.3h-.8v1.6M179.9 228.5h.8l.3-.3v-.5l-.3-.3h-.8v1.7M179.9 223.4h.8l.3-.2v-.6l-.3-.2h-.8v1.6M179.9 226h.8l.3-.3v-.5l-.3-.3h-.8v1.6"/>
<path d="M181.5 222.4v1.6l.6-.6 .5 .6v-1.6M181.5 227.4v1.7l.6-.6 .5 .6v-1.7M181.5 224.9h.6M181.5 226.5h.6M181.8 224.9v1.6M182.6 225.7h1.1M183.1 228.5h.9l.2-.3v-.5l-.2-.3h-.9v1.7M183.1 220.9h.9l.2-.3v-.5l-.2-.3h-.9v1.6M183.1 223.4h.9l.2-.2v-.6l-.2-.2h-.9v1.6M183.7 220.9l.5 .5M183.7 228.5l.5 .6M183.7 223.4l.5 .6"/>
<path d="M184.2 226h.8l.3-.3v-.5l-.3-.3h-.8v1.6M184.8 220.6h1.1M184.8 223.2h1.1M184.8 228.2h1.1M184.8 226l.5 .5M185.9 225.7h.5M186.4 224v-1.6l.6 .5 .5-.5v1.6M186.7 227.4h.5l.3 .3v1.1l-.3 .3h-.5l-.3-.3v-1.1zM187 224.9h-1.1v1.6h1.1M187.5 220.1l-.3-.3h-.5l-.3 .6 .3 .2h.5l.3 .6-.3 .2h-.5l-.3-.2M188 220.6h1.1M188 223.2h.6"/>
<path d="M188.6 225.2l-.3-.3h-.5l-.3 .5 .3 .3h.5l.3 .6-.3 .2h-.5l-.3-.2M189.1 225.7h.6M189.1 222.4h-1.1v1.6h1.1M189.1 227.4v1.7l-1.1-1.7v1.7M189.7 223.2h1.1M189.7 224v-1.1l.5-.5 .6 .5v1.1M190.2 224.9h-1.1v1.6h1.1M190.8 224.9h1.1M191.3 224.9v1.6M192.4 222.6l-.2-.2h-.6l-.3 .2 .3 .6h.6l.2 .2-.2 .6h-.6l-.3-.3M194.6 220.1l.3-.3h.5l.3 .3v1.1l-.3 .2h-.5l-.3-.2zM217.7 221l.3-.2 .7 .2-1 1.2h1"/>
<path d="M217.7 223.6l.3-.2 .7 .2-1 1.1h1M217.7 226.1l.3-.2 .7 .2-1 1.2h1M217.7 228.7l.3-.3 .7 .3-1 1.1h1M219.2 226.1l.2-.2 .7 .2-.9 1.2h.9M219.2 228.7l.7-.3 .2 .3-.2 .4M219.2 224.7h.9M219.2 223.8l.4-.4v1.3M219.6 229.1h.3M219.9 229.1l.2 .3-.2 .4-.7-.2M220.1 221l-.2-.2-.7 .2v1M220.1 221v1l-.2 .2-.7-.2M220.1 221l-.9 1"/>
<path d="M221.5 228.4l-.9 1.4M221.5 225.9l-.9 1.4M221.5 223.4l-.9 1.3M221.5 220.8l-.9 1.4M222 224.7v-.9l.4-.4 .5 .4v.9M222 222.2v-.9l.4-.5 .5 .5v.9M222 227.3v-.9l.4-.5 .5 .5v.9M222 229.8v-.9l.4-.5 .5 .5v.9M222 229.1h.9M222 226.6h.9M222 224h.9M222 221.5h.9"/>
<path d="M223.4 221.5h.6l.3 .5-.7 .2zM223.4 223.4h.9l-.9 1.3M223.6 226.6l-.2 .2 .2 .5 .7-.2-.3-.5M223.6 226.6l-.2-.2 .2-.5 .7 .2-.3 .5M223.6 226.6h.4M224.3 229.1h-.7l-.2-.2 .2-.5 .7 .3v.9l-.3 .2-.6-.2M224.3 220.8l-.9 .7M225.7 228.4l-.9 1.4M225.7 225.9l-.9 1.4M225.7 223.4l-.9 1.3M225.7 220.8l-.9 1.4M226.2 221.7h.7l.2-.7-.2-.2h-.7v1.4"/>
<path d="M226.2 224.3h.7l.2-.7-.2-.2h-.7v1.3M226.2 228.4h.9M226.2 225.9h.9M226.6 225.9v1.4M226.6 228.4v1.4M227.6 220.8v1.4l.4-.5 .5 .5v-1.4M227.6 223.4v1.3l.4-.4 .5 .4v-1.3M228.5 228.4l-.9 1.4M228.5 225.9l-.9 1.4M229 222.2v-1.4l.4 .5 .5-.5v1.4M229 224.7v-1.3l.4 .4 .5-.4v1.3M229 226.8h.7l.2-.7-.2-.2h-.7v1.4"/>
<path d="M229 229.4h.7l.2-.7-.2-.3h-.7v1.4M230.4 228.4v1.4l.4-.4 .5 .4v-1.4M230.4 225.9v1.4l.4-.5 .5 .5v-1.4M230.4 235.6h.7M230.8 235.6v1M231.6 236.1h.4M231.8 229.8v-1.4l.4 .5 .5-.5v1.4M231.8 227.3v-1.4l.4 .5 .5-.5v1.4M232.3 235.6h-.7v1h.7M232.8 236.1h.3M233.5 235.6h-.7v1h.7M234.7 235.6v1l-.8-1v1"/>
<path d="M235.8 235.8l-.2-.2-.5 .2 .2 .3 .5 .2-.2 .3-.5-.1M236.3 235.6l.3 .5M236.6 236.1v.5M237 235.6l-.4 .5M237.4 236.8h.8M238.6 235.8l.6-.2 .1 .2-.1 .3M239 236.1h.2M239.2 236.1l.1 .2-.1 .3-.6-.1M239.8 236.5l.2 .1zM240.4 236.6h.7M240.4 235.9l.3-.3v1M241.5 236.1h.8"/>
<path d="M242.7 235.8l.5-.2 .2 .2-.2 .3M243.1 236.1h.1M243.2 236.1l.2 .2-.2 .3-.5-.1M243.9 236.5l.2 .1zM244.5 235.8l.1-.2 .6 .2-.7 .8h.7M245.6 236.8h.7M246.8 236.1h.7M246.8 236.6v-.7l.4-.3 .3 .3v.7M248 235.6v1h.7M249.1 235.6v1h.8M250.3 236.8h.7M251.5 236.3h.5l.2-.5-.7-.2v1"/>
<path d="M252.6 235.6h.4M252.6 236.6h.4M252.8 235.6v1M254.1 235.6v1l-.7-1v1M255.3 235.8l-.2-.2-.5 .2 .2 .3 .5 .2-.2 .3-.5-.1M51.6 253.1l-.3-.3h-.5l-.3 .3v1.1l.3 .3h.5l.3-.3v-.6h-.5M53.2 252.8v1.7l-1-1.7v1.7M53.8 252.8h.8l.3 .3v1.1l-.3 .3h-.8zM60.5 242h.8l.3-.3v-.5l-.3-.3h-.8v1.6M60.5 244.5h.8l.3-.3v-.5l-.3-.3h-.8v1.7M60.5 247.1h.8l.3-.3v-.5l-.3-.3h-.8v1.6M62.1 244l.6-.6v1.7"/>
<path d="M62.1 241.4l.6-.5v1.6M62.1 246.5l.6-.5v1.6M62.1 242.5h1.1M62.1 245.1h1.1M62.1 247.6h1.1M63.8 241.7h1.1M63.8 244.2h1.1M63.8 246.8h1.1M65.4 242.5v-1.1l.6-.5 .5 .5v1.1M65.4 245.1v-1.1l.6-.6 .5 .6v1.1M65.4 247.6v-1.1l.6-.5 .5 .5v1.1M65.4 241.7h1.1"/>
<path d="M65.4 244.2h1.1M65.4 246.8h1.1M67.1 241.2l.2-.3h.6l.2 .3-.2 .5M67.1 243.7l.2-.3h.6l.2 .3-.2 .5M67.1 246.3l.2-.3h.6l.2 .3-.2 .5M67.6 241.7h.3M67.6 244.2h.3M67.6 246.8h.3M67.9 241.7l.2 .3-.2 .5h-.6l-.2-.2M67.9 244.2l.2 .3-.2 .6h-.6l-.2-.3M67.9 246.8l.2 .3-.2 .5h-.6l-.2-.3M68.7 246.3l.3-.3h.5l.3 .3v.2l-1.1 1.1h1.1"/>
<path d="M68.7 244l.5-.6v1.7M68.7 245.1h1.1M69.8 241.2v1.1l-.3 .2h-.5l-.3-.2M69.8 241.2l-.3-.3h-.5l-.3 .3v1.1M69.8 241.2l-1.1 1.1M78.3 244.5h.8l.3-.3v-.5l-.3-.3h-.8v1.7M78.3 242h.8l.3-.3v-.5l-.3-.3h-.8v1.6M78.3 247.1h.8l.3-.3v-.5l-.3-.3h-.8v1.6M79.9 242.5h1.1M79.9 245.1h1.1M79.9 247.6h1.1M79.9 241.4l.6-.5v1.6"/>
<path d="M79.9 244l.6-.6v1.7M79.9 246.5l.6-.5v1.6M81.6 241.7h1M81.6 244.2h1M81.6 246.8h1M83.2 240.9h.8l.3 .3-.3 .5 .3 .6-.3 .2h-.8zM83.2 243.4h.8l.3 .3-.3 .5 .3 .6-.3 .3h-.8zM83.2 246h.8l.3 .3-.3 .5 .3 .5-.3 .3h-.8zM83.2 241.7h.8M83.2 244.2h.8M83.2 246.8h.8M84.8 241.2l.3-.3h.5l.3 .3-.3 .5"/>
<path d="M84.8 243.7l.3-.3h.5l.3 .3-.3 .5M84.8 246.3l.3-.3h.5l.3 .3-.3 .5M85.4 241.7h.2M85.4 244.2h.2M85.4 246.8h.2M85.6 241.7l.3 .3-.3 .5h-.5l-.3-.2M85.6 244.2l.3 .3-.3 .6h-.5l-.3-.3M85.6 246.8l.3 .3-.3 .5h-.5l-.3-.3M86.5 245.1h1M86.5 246.3l.2-.3h.6l.2 .3v.2l-1 1.1h1M86.5 244l.5-.6v1.7M87.5 241.2l-.2-.3h-.6l-.2 .3v1.1"/>
<path d="M87.5 241.2v1.1l-.2 .2h-.6l-.2-.2M87.5 241.2l-1 1.1M89.7 253.1l-.3-.3h-.5l-.3 .3v1.1l.3 .3h.5l.3-.3v-.6h-.5M91.3 252.8v1.7l-1-1.7v1.7M91.9 252.8h.8l.3 .3v1.1l-.3 .3h-.8zM257.2 248l-.3-.2h-.6l-.2 .2v1.1l.2 .3h.6l.3-.3v-.5h-.6M258.8 247.8v1.6l-1.1-1.6v1.6M259.3 247.8h.8l.3 .2v1.1l-.3 .3h-.8z"/>
</g>
<g fill="none" stroke="#800000" stroke-width=".31">
<path d="M26.1 10.7h379.7v252.7h-379.7zM48.8 8.4l.8-.8v2.4M48.8 10h1.6M73.6 6.9v3.8M96.2 8l.4-.4h.8l.4 .4v.4l-1.6 1.6h1.6M121.1 6.9v3.8M143.7 8l.4-.4h.8l.4 .4v.4l-.4 .4M144.5 8.8h.4M144.9 8.8l.4 .4v.4l-.4 .4h-.8l-.4-.4M168.5 6.9v3.8M192.8 8.8h-1.6l1.2-1.2v2.4M216 6.9v3.8"/>
<path d="M240.2 7.6h-1.6v1.2l.8-.4h.4l.4 .4v.8l-.4 .4h-.8l-.4-.4M263.4 6.9v3.8M286.1 8.8h1.2l.4 .4v.4l-.4 .4h-.8l-.4-.4zM287.7 7.6l-.8 .4-.8 .8M310.9 6.9v3.8M333.5 7.6h1.6v.4l-1.6 1.6v.4M358.4 6.9v3.8M381.4 8.8l-.4-.4v-.4l.4-.4h.8l.4 .4v.4l-.4 .4M381.4 8.8l-.4 .4v.4l.4 .4h.8l.4-.4v-.4l-.4-.4M381.4 8.8h.8M23.1 37.2v-1.6l.8-.8 .8 .8v1.6M23.1 36h1.6"/>
<path d="M59.5 36.1h1.8v5.1h-1.8zM60.4 28.5v2.6M60.4 33.6v2.5M60.4 28.5l1.3 1.9M60.4 28.5l-1.2 1.9M85.8 28.5l1.3 1.9M85.8 28.5l-1.2 1.9M85.8 28.5v2.6M90.9 38.7v2.5M101.1 38.7v2.5M217.9 31.1l1.3 1.9M217.9 31.1l-1.3 1.9"/>
<path d="M217.9 31.1v2.5M228 38.7h2.6M230.6 37.8h5.1v1.8h-5.1zM235.7 38.7h2.5M240.7 38.7h7.7M243.3 37.4l2.5 1.3-2.5 1.2zM245.8 37.4v2.5M256.1 35v1M256.9 35l-.8 .5M257.4 35.5h1.1l-.3-.5h-.5l-.3 .2v.6l.3 .2h.5M260.1 34.4v1.6h-.8l-.2-.2v-.6l.2-.2h.8M262.3 36h.8l.3-.2v-.6l-.3-.2h-.8v1.6"/>
<path d="M264.2 35h.6l.2 .2v.6l-.2 .2h-.6l-.2-.2v-.6zM265.6 35v.8l.3 .2 .2-.2 .3 .2 .3-.2v-.8M267.3 35.5h1l-.2-.5h-.6l-.2 .2v.6l.2 .2h.6M268.9 35v1M269.7 35l-.8 .5M271.9 35h.3v1M271.9 36h.5M272.2 34.2v.2M273 36v-1h.8l.3 .2v.8M275.7 34.4v1.6h-.8l-.3-.2v-.6l.3-.2h.8M276.2 35h.3v1M276.2 36h.6"/>
<path d="M276.5 34.2v.2M278.4 35h-.8l-.3 .2v.6l.3 .2h.8M279.3 35h.5l.3 .2v.8h-.8l-.3-.2 .3-.3h.8M280.6 35h.6M280.9 34.7v1.1l.3 .2M282 35h.5l.3 .2v.6l-.3 .2h-.5l-.3-.2v-.6zM283.3 35v1M284.2 35l-.9 .5M304.2 20.9v2.5M304.2 28.5v3.1M304.2 33.1v3M304.2 38.7v2.5"/>
<path d="M304.2 20.9l1.3 1.9M304.2 20.9l-1.2 1.9M327.1 23.4v2.6M327.1 23.4l1.3 1.9M327.1 23.4l-1.3 1.9M334.7 33.6h5.1M334.7 38.7h5.1M365.2 36.1h5.1M365.2 33.6h5.1M406.6 36h1.6M406.6 37.2v-1.6l.8-.8 .8 .8v1.6M42.7 43.8v2.5"/>
<path d="M42.7 48.8v3.1M42.7 53.4v3.1M42.7 59v2.5M42.7 43.8l1.2 1.9M42.7 43.8l-1.3 1.9M54.8 46.3h.6M54.8 48.8h.6M60.4 41.2v2.6M60.4 59v2.5M63 46.3h2.5M63 56.5h2.5M63 51.4h2.5"/>
<path d="M63 53.9h2.5M63 48.8h2.5M65.5 43.8h15.3v15.2h-15.3zM80.8 46.3h2.5M80.8 51.4h2.5M80.8 53.9h2.5M90 41.2h1.8v5.1h-1.8zM90.9 46.3v2.5M100.2 41.2h1.8v5.1h-1.8zM101.1 46.3v2.5M159.6 54.7v1.7h1M161.2 55.6h1.1"/>
<path d="M163.9 55l-.3-.3h-.5l-.3 .3v1.1l.3 .3h.5l.3-.3M164.5 55.6h1M164.5 56.4v-1.1l.5-.6 .5 .6v1.1M167.2 54.7v1.7l-1.1-1.7v1.7M169.7 55.3h.5l.3 .3v.8h-.8l-.3-.3 .3-.3h.8M172.1 54.7v1.7h-.8l-.3-.3v-.5l.3-.3h.8M173.7 54.7v1.7h-.8l-.2-.3v-.5l.2-.3h.8M174.3 55.3v1.1M175.1 55.3h-.3l-.5 .5M175.6 55.8h1.1l-.2-.5h-.6l-.3 .3v.5l.3 .3h.6M178.4 55.3h-.9l-.2 .3 .2 .2h.6l.3 .3-.3 .3h-.8M180 55.3h-.8l-.3 .3 1.1 .5-.3 .3h-.8"/>
<path d="M182.2 55.3h.5M182.3 43.8h2.6M182.3 46.3h2.6M182.3 48.8h2.6M182.3 41.2h2.6M182.5 55v1.1l.2 .3M183.3 55.6l.3-.3h.5l.3 .3v.8M183.3 54.7v1.7M184.9 55.3h.3v1.1M184.9 56.4h.6M185.2 54.5v.2M186 49.1l.7-.1 .1 .4-.7 .1z"/>
<path d="M186 48h.8l-.8 .6h.8M187.1 55.3h-.8l-.3 .3 .3 .2h.5l.3 .3-.3 .3h-.8M187.4 45.8h5.1v1h-5.1zM187.4 40.7h5.1v1h-5.1zM187.4 43.2h5.1v1.1h-5.1zM187.4 48.3h5.1v1h-5.1zM189.3 54.7v1.7h.8l.3-.3v-.5l-.3-.3h-.8M191.2 55.3h.5l.3 .3v.5l-.3 .3h-.5l-.3-.3v-.5zM192.8 55.3h.6l.3 .3v.8h-.9l-.2-.3 .2-.3h.9M193.5 43.6h-.4l.1 .5M193.5 41.1v.6l-.4-.5h.9M193.5 43.6h.5l-.2 .5"/>
<path d="M193.5 43.6v.2M194 46v.6l-.6-.6-.3 .2 .1 .4M194 48.7h-.9l.3 .3M194 48.5v.5M194.2 55.3v1.1M195 55.3h-.3l-.5 .5M195 43.8h2.6M195 46.3h2.6M195 48.8h2.6M195 41.2h2.6M196.6 54.7v1.7h-.8l-.2-.3v-.5l.2-.3h.8M200.7 56.5h3.9"/>
<path d="M202.6 53.9v2.6M228 59h2.6M228 48.8h2.6M230.6 47.9h5.1v1.8h-5.1zM230.6 58.1h5.1v1.8h-5.1zM235.7 59h2.5M235.7 48.8h2.5M240.7 59h7.7M240.7 48.8h7.7M243.3 57.7l2.5 1.3-2.5 1.3zM243.3 47.6l2.5 1.2-2.5 1.3zM244.1 50.9l1.3 1.4"/>
<path d="M244.1 40.7l1.3 1.4M244.6 51.9l.5-.5 .3 .9zM244.6 41.7l.5-.5 .3 .9zM244.6 41.7h.7M244.6 51.9h.7M244.6 51.8h.6M244.7 41.8h.6M244.7 41.5h.5M244.8 51.7h.4M244.9 41.4h.3M244.9 51.5h.2M244.9 52h.4"/>
<path d="M245 41.9h.4M245 41.3h.1M245 51.4h.1M245.2 50.7l1.4 1.4M245.2 52.2h.2M245.2 40.6l1.4 1.4M245.3 42h.1M245.7 51.8l.5-.6 .4 .9zM245.7 41.6l.5-.5 .4 .9zM245.7 41.5h.7M245.8 51.7h.6M245.8 51.8h.6"/>
<path d="M245.8 47.6v2.5M245.8 57.7v2.6M245.9 41.7h.5M245.9 41.4h.5M245.9 51.5h.4M246 41.3h.3M246 51.4h.3M246.1 51.9h.4M246.1 41.2h.2M246.1 51.3h.1M246.1 41.8h.4M246.4 52h.1"/>
<path d="M246.4 41.9h.1M256.3 55.3h.6l.3 .3v.8h-.9l-.2-.3 .2-.3h.9M257.2 46.2h-.9l-.2-.3v-.5l.2-.3h.9v1.4l-.6 .3M257.7 45.1v1.1M258.2 55.6l-.5-.3v1.1M258.2 55.6l.3-.3 .3 .3v.8M258.2 55.6v.8M258.5 45.1h-.3l-.5 .6M259.1 45.7h1l-.2-.6h-.6l-.2 .3v.5l.2 .3h.6M259.3 54.7v1.7h.8l.3-.3v-.5l-.3-.3h-.8M260.7 45.7h1.1l-.3-.6h-.5l-.3 .3v.5l.3 .3h.5M261 55.8h1.1l-.3-.5h-.6l-.2 .3v.5l.2 .3h.6"/>
<path d="M262.3 46.2v-1.1h.8l.3 .3v.8M262.6 55.3v1.1M263.4 55.3h-.3l-.5 .5M265.6 44.6v1.6h1.1M265.6 55.3h.3v1.1M265.6 56.4h.5M265.9 54.5v.2M267.3 45.4h1M267.8 54.7v1.7h-.8l-.3-.3v-.5l.3-.3h.8M268.3 55.8h1.1l-.2-.5h-.6l-.3 .3v.5l.3 .3h.6M270 44.9l-.3-.3h-.5l-.3 .3v1l.3 .3h.5l.3-.3M270 56.4v-1.1h.8l.3 .3v.8"/>
<path d="M270.5 45.4h1.1M270.5 46.2v-1.1l.6-.5 .5 .5v1.1M271.6 55.3h.6M271.9 55v1.1l.3 .3M272.7 55.3h.3v1.1M272.7 56.4h.5M273 54.5v.2M273.2 44.6v1.6l-1-1.6v1.6M273.8 55.6h.5M274.3 54.7l-.2 .3v1.4M274.9 55.3v.8l.2 .3h.9M275.7 45.1h.5l.3 .3v.8h-.8l-.3-.3 .3-.2h.8"/>
<path d="M276 55.3v1.3l-.6 .3M278.2 45.1h-.9l-.2 .3v.5l.2 .3h.9M278.7 45.1h.6M279 44.9v1l.3 .3M279.8 45.1h.3v1.1M279.8 46.2h.5M280.1 44.3v.3M280.9 45.1l.5 1.1 .6-1.1M282.5 45.1h.3v1.1M282.5 46.2h.6M282.8 44.3v.3M283.6 45.1h.6"/>
<path d="M283.9 44.9v1l.3 .3M284.7 45.1v.8l.3 .3h.8M285.8 45.1v1.4l-.6 .3M302.3 41.2h3.8M317.6 53.9h3.8M318.6 43.8h1.8v5h-1.8zM319.5 41.2v2.6M319.5 48.8v5.1M325.2 53.9h3.8M327.1 51.4v2.5M334.7 46.3h5.1M334.7 41.2h5.1"/>
<path d="M365.2 43.8h5.1M365.2 41.2h5.1M22.3 61.3h3.8M40.7 61.5h3.9M58.5 61.5h3.8M65.6 66.5h.5M65.6 64.9h.5M65.8 64.9v1.6M66.7 64.9h.8l.3 .3v1.1l-.3 .2h-.8zM70 65.7h.5M71 64.9h-1v1.6h1M71.6 65.7h.5"/>
<path d="M72.7 64.9h-1.1v1.6h1.1M73.2 66h.8l.3-.3v-.5l-.3-.3h-.8v1.6M74.9 66h.8l.2-.3v-.5l-.2-.3h-.8v1.6M75.4 66l.5 .5M76.5 65.2l.3-.3h.5l.3 .3v1.1l-.3 .2h-.5l-.3-.2zM78.1 66.5v-1.6l.6 .5 .5-.5v1.6M244.1 61l1.3 1.4M244.6 62l.8 .4M244.6 62h.7M244.7 61.9h.5M244.8 61.8h.4M244.9 62.2h.4"/>
<path d="M244.9 61.7h.2M245 61.6h.1M245.1 61.5l-.5 .5M245.1 61.5l.3 .9M245.2 62.3h.2M245.2 60.9l1.4 1.4M245.4 62.4h.1M245.7 61.9l.9 .4M245.7 61.9h.7M245.8 61.8h.6M245.9 61.7h.4M246 62h.5"/>
<path d="M246 61.6h.3M246.2 61.4h.1M246.2 61.4l-.5 .5M246.2 61.4l.4 .9M246.3 62.2h.2M246.6 62.3h.1M251.5 64.1h3.9M253.4 61.5v2.6M258.5 79.3v2.6M258.5 79.3l1.3 1.9M258.5 79.3l-1.2 1.9M304.2 66.6v2.6"/>
<path d="M304.2 74.2v3.1M304.2 78.8v3.1M304.2 66.6l1.3 1.9M304.2 66.6l-1.2 1.9M319.5 74.2l1.2 1.9M319.5 74.2l-1.3 1.9M319.5 74.2v2.6M405.8 61.3h3.8M23.1 85.3h1.2l.4 .4v.4l-.4 .4 .4 .4v.4l-.4 .4h-1.2zM23.1 86.5h1.2M60.4 84.4v2.5M60.4 84.4l1.3 1.9"/>
<path d="M60.4 84.4l-1.2 1.9M65.5 92h5.1M65.5 94.5h5.1M65.5 97.1h5.1M65.5 99.6h5.1M75.7 92h5.1M75.7 94.5h5.1M75.7 97.1h5.1M75.7 99.6h5.1M83.3 84.4v2.5M83.3 84.4l1.3 1.9M83.3 84.4l-1.3 1.9"/>
<path d="M154.4 81.9v2.5M154.4 81.9l.8 1.2M154.4 81.9l-.8 1.2M179.8 92h2.5M179.8 97.1h2.5M182.3 89.5h17.8v20.3h-17.8zM200.1 92h2.5M200.1 97.1h2.5M225.6 83l.2-.3h.6l.3 .3v.2l-1.1 1.1h1.1M227.2 82.7v1.6l.6-.5 .5 .5v-1.6M230.5 83.2l.5-.5v1.6M230.5 84.3h1.1"/>
<path d="M232.1 82.7h.3v.3h-.3zM233.2 84h.3v.3h-.3zM233.5 82.7l-1.4 1.6M236.8 83.2h-.9l-.2 .3 1.1 .5-.3 .3h-.8M237.3 82.7v1.6M237.3 83.5l.3-.3h.5l.3 .3v.8M239 83.2v.8l.2 .3h.8v-1.1M240.6 84.3v-1.1h.8l.3 .3v.8M242.2 83.2h.6M242.5 83v1l.3 .3M243.3 86.9h2.5M245.8 97.1h22.9v27.9h-22.9z"/>
<path d="M245.8 86h5.1v1.8h-5.1zM246 98.7v1.1l.5 .5 .6-.5v-1.1M247.6 99.2h.3v1.1M247.9 98.4v.3M250.4 99.5h1M250.9 86.9h2.5M250.9 99v1M253.4 92v11.4l-.7 .3 1.5 .5-1.5 .5 1.5 .5-1.5 .5 .7 .3v3.8M258.5 92v11.4l-.7 .3 1.5 .5-1.5 .5 1.5 .5-1.5 .5 .7 .3v3.8M259.6 98.7v1.1l.6 .5 .5-.5v-1.1M261.3 99.2h.2v1.1M261.5 98.4v.3"/>
<path d="M264 99.5h1.1M302.3 86.9h3.8M304.2 84.4v2.5M318.6 89.5h1.8v5h-1.8zM319.5 86.9v2.6M319.5 94.5v2.6M327.1 92h5.1M327.1 94.5h5.1M327.1 99.6h5.1M327.1 81.9h5.1M327.1 86.9h5.1M327.1 89.5h5.1"/>
<path d="M372.8 92h5.1M372.8 94.5h5.1M372.8 99.6h5.1M372.8 81.9h5.1M372.8 86.9h5.1M372.8 84.4h5.1M406.6 85.3h1.2l.4 .4v.4l-.4 .4 .4 .4v.4l-.4 .4h-1.2zM406.6 86.5h1.2M22.3 111.8h3.8M65.5 102.2h5.1M65.5 104.7h5.1M65.5 107.2h5.1"/>
<path d="M65.5 109.8h5.1M65.5 112.3h5.1M65.5 114.9h5.1M65.5 117.4h5.1M65.5 119.9h5.1M75.7 102.2h5.1M75.7 104.7h5.1M75.7 107.2h5.1M75.7 109.8h5.1M75.7 112.3h5.1M75.7 114.9h5.1M75.7 117.4h5.1"/>
<path d="M75.7 119.9h5.1M143.3 112.3h1.8v5.1h-1.8zM144.2 109.8v2.5M144.2 117.4v2.5M154.4 112.3v3.1M154.4 116.9v3M164.5 112.3v3.1M164.5 116.9v3M174.7 112.3v3.1M174.7 116.9v3M179.8 102.2h2.5M179.8 107.2h2.5"/>
<path d="M200.1 102.2h2.5M200.1 107.2h2.5M217.9 112.3v3.1M217.9 116.9v3M228 112.3v3.1M228 116.9v3M240.7 109.8h5.1M246.9 108.8v1.1l.6 .6 .5-.6v-1.1M247.6 100.3h.6M248.6 109.6h1M248.7 100.3v-1.1h.8l.3 .3v.8M249.1 109.1v1.1"/>
<path d="M250.5 104.5h1.6M251 103.7l.5 .8 .6-.8M252.1 105.6h-1.6l.5 .6M252.1 105.1v1.1M252.2 109.8h7.6l-3.8 7.6zM252.9 110.8h1.1M253.2 108.5h12.9v4.8l-1.2 1.3M253.2 108.6l.1 .1M253.2 108.6h.5M253.2 108.4h.5M253.3 108.3l-.1 .3M253.3 108.3l.4 .1"/>
<path d="M253.3 108.7h.3M253.3 108.7l.1 .1M253.4 110.3v1M253.6 108.7l-.1 .1M253.7 108.4v.2M253.7 108.6l-.1 .1M258 110.8h1M259.9 104.5h1.6M260.4 103.7l.5 .8 .6-.8M261.3 100.3h.5M261.5 105.6h-1.6l.5 .6M261.5 105.1v1.1"/>
<path d="M262.3 100.3v-1.1h.9l.2 .3v.8M264.9 115.4h-3.8v4.5h-5.1v-2.5M264.9 116.1l1.2 1.3M264.9 113.6v3.5M265.6 117.1l.5 .3M265.9 116.9l.2 .5M266.1 117.4v2.5h7.7M327.1 102.2h5.1M327.1 104.7h5.1M327.1 107.2h5.1M327.1 109.8h5.1M327.1 114.9h5.1"/>
<path d="M372.8 102.2h5.1M405.8 111.8h3.8M24.7 136.3l-.4-.4h-.8l-.4 .4v1.6l.4 .4h.8l.4-.4M65.5 127.6h5.1M65.5 122.5h5.1M65.5 125h5.1M65.5 130.1h5.1M65.5 132.6h5.1M65.5 135.2h5.1M65.5 137.7h5.1M75.7 127.6h5.1M75.7 122.5h5.1"/>
<path d="M75.7 125h5.1M75.7 130.1h5.1M75.7 132.6h5.1M75.7 135.2h5.1M75.7 137.7h5.1M142.3 125h3.8M144.2 122.5v2.5M152.5 125h3.8M154.4 122.5v2.5M162.6 125h3.9M164.5 122.5v2.5M172.8 125h3.8"/>
<path d="M174.7 122.5v2.5M195.1 134.6h.8l.3-.3v-.6l-.3-.2h-.8v1.6M195.6 134.6l.6 .5M197 134h.5l.3 .3v.8h-.8l-.3-.3 .3-.2h.8M199.5 134h-.9l-.2 .3 1.1 .5-.3 .3h-.8M200 135.1h.8l.3-.3v-.5l-.3-.3h-.8v1.6M201.7 133.5v1.6h.8l.2-.3v-.5l-.2-.3h-.8M203.3 134.6h1.1l-.3-.6h-.5l-.3 .3v.5l.3 .3h.5M204.9 134v1.1M205.7 134h-.2l-.6 .6M206.3 134v1.1M207.1 134l-.8 .6"/>
<path d="M207.7 134v.8l.2 .3h.8M208.4 125h3.8M208.7 134v1.4l-.5 .2M210.3 122.5v2.5M210.9 134.6h.9l.2-.3v-.6l-.2-.2h-.9v1.6M212.6 134h.2v1.1M212.6 135.1h.5M212.8 133.2v.3M215.3 134.6h.8l.3-.3v-.6l-.3-.2h-.8v1.6M216 125h3.8M217.2 134h.5l.3 .3v.5l-.3 .3h-.5l-.3-.3v-.5zM217.9 122.5v2.5"/>
<path d="M218.6 134v.8l.2 .3 .3-.3 .3 .3 .2-.3v-.8M220.2 134.6h1.1l-.3-.6h-.5l-.3 .3v.5l.3 .3h.5M221.8 134v1.1M222.7 134h-.3l-.6 .6M225.9 133.7l-.2-.2h-.6l-.2 .2v1.1l.2 .3h.6l.2-.3M226.1 125h3.9M226.8 134h.5l.3 .3v.5l-.3 .3h-.5l-.3-.3v-.5zM228 122.5v2.5M228.1 135.1v-1.1h.8l.3 .3v.8M229.8 134h.5M230 133.7v1.1l.3 .3M230.8 134v1.1"/>
<path d="M231.7 134l-.9 .6M232.5 134h.5l.3 .3v.5l-.3 .3h-.5l-.3-.3v-.5zM233.8 133.5h.3v1.6M233.8 135.1h.6M256.6 137.7h3.8M256.9 122.8l-.3-.2h-.5l-.3 .2v1.1l.3 .3h.5l.3-.3v-.5h-.6M258.5 122.6v1.6l-1-1.6v1.6M258.5 125v5.1M258.5 135.2v2.5M259.1 122.6h.8l.3 .2v1.1l-.3 .3h-.8zM262.9 120.8l.3-.3h.5l.3 .3v1.1l-.3 .3h-.5l-.3-.3zM264.6 120.5v1.4l.2 .3h.6l.2-.3v-1.4"/>
<path d="M266.2 120.5h1.1M266.7 120.5v1.7M276.9 137.7h3.9M278 125h1.7v5.1h-1.7zM278.8 122.5v2.5M278.8 130.1v2.5M278.8 135.2v2.5M289.1 126.4l.5-.5v1.6M289.1 127.5h1.1M290.7 125.9v1l.6 .6 .5-.6v-1M293.4 125.9l-1 1.6M294 127.5v-1.1l.5-.5 .6 .5v1.1"/>
<path d="M294 126.7h1.1M317.6 125h3.8M319.5 122.5v2.5M334.7 130.1v3M334.7 134.7v3M346.1 130.1h2.8M348.9 128.3v3.6M349.6 128.6h.7v3h-.7zM351 128.3v3.6M351 130.1h2.8M362.6 130.1v3M362.6 134.7v3"/>
<path d="M408.2 136.3l-.4-.4h-.8l-.4 .4v1.6l.4 .4h.8l.4-.4M50.9 153h3.8M51.9 142.8h1.8v5.1h-1.8zM52.8 140.3v2.5M52.8 147.9v5.1M58 152.3h.8l.3-.2v-.6l-.3-.3h-.8v1.7M58.5 152.3l.6 .6M59.9 151.8h.5l.3 .3v.8h-.8l-.3-.3 .3-.3h.8M61.1 145.3h3.8M62.3 151.8h-.8l-.3 .3 .3 .2h.6l.2 .3-.2 .3h-.9M62.9 152.9h.8l.3-.3v-.5l-.3-.3h-.8v1.6M63 142.8v2.5"/>
<path d="M64.5 151.2v1.7h.8l.3-.3v-.5l-.3-.3h-.8M65.5 140.3h5.1M66.1 152.3h1.1l-.2-.5h-.6l-.3 .3v.5l.3 .3h.6M67.8 151.8v1.1M68.6 151.8l-.8 .5M69.2 151.8v1.1M70 151.8h-.3l-.5 .5M70.5 151.8v.8l.3 .3h.8M71.6 151.8v1.3l-.5 .3M73.8 152.3h.8l.3-.2v-.6l-.3-.3h-.8v1.7M75.4 151.8h.3v1.1M75.4 152.9h.6"/>
<path d="M75.7 140.3h5.1M75.7 151v.2M78.1 152.3h.9l.2-.2v-.6l-.2-.3h-.9v1.7M79.8 152.9h1.1M79.8 151.8l.5-.6v1.7M81.4 145.3h3.8M83.3 142.8v2.5M84.1 151.8h-.8l-.2 .3v.5l.2 .3h.8M85 151.8h.5l.3 .3v.5l-.3 .3h-.5l-.3-.3v-.5zM86.3 152.9v-1.1h.8l.3 .3v.8M88 152.9v-1.1h.8l.2 .3v.8M89.6 152.3h1.1l-.3-.5h-.5l-.3 .3v.5l.3 .3h.5"/>
<path d="M92.3 151.8h-.8l-.3 .3v.5l.3 .3h.8M92.9 151.8h.5M93.2 151.5v1.1l.2 .3M94.3 151.8h.5l.3 .3v.5l-.3 .3h-.5l-.3-.3v-.5zM95.6 151.8v1.1M96.4 151.8l-.8 .5M113.7 155.5l.8 1.3M113.7 155.5l-.7 1.3M113.7 155.5v2.5M330.8 149l-.3-.3h-.5l-.3 .3v1.1l.3 .2h.5l.3-.2M331.3 150.3v-1.1l.6-.5 .5 .5v1.1M331.3 149.5h1.1"/>
<path d="M332.8 142.8h3.8M334.1 148.7v1.6l-1.1-1.6v1.6M334.7 140.3v2.5M336.3 150.3h.5M336.3 149.2h.2v1.1M336.5 148.4v.3M337.4 150.3v-1.1h.8l.2 .3v.8M339 149.2h.5M339.3 149v1.1l.2 .2M340.1 149.8h1.1l-.3-.6h-.6l-.2 .3v.6l.2 .2h.6M341.7 149.2v1.1M342.5 149.2l-.8 .6"/>
<path d="M343.1 149.5h.5M343.6 148.7l-.3 .3v1.3M344.4 149.2h.6l.2 .3v.8h-.8l-.2-.2 .2-.3h.8M346.9 149.2h-.8l-.3 .3v.6l.3 .2h.8M347.5 149.8h1l-.2-.6h-.6l-.2 .3v.6l.2 .2h.6M350.7 149.5h.6M351.3 148.7l-.3 .3v1.3M351.8 149.5l.3-.3h.5l.3 .3v.6l-.3 .2h-.5l-.3-.2zM353.4 149.2v1.1M354.3 149.2l-.9 .6M356.4 149.8h.9l.2-.3v-.5l-.2-.3h-.9v1.6M357 149.8l.5 .5"/>
<path d="M358.4 149.2h.5l.3 .3v.8h-.8l-.3-.2 .3-.3h.8M360.7 142.8h3.9M360.8 149.2h-.8l-.3 .3 1.1 .6-.3 .2h-.8M361.4 150.3h.8l.2-.2v-.6l-.2-.3h-.8v1.7M362.6 140.3v2.5M363 148.7v1.6h.8l.3-.2v-.6l-.3-.3h-.8M364.6 149.8h1.1l-.3-.6h-.5l-.3 .3v.6l.3 .2h.5M366.3 149.2v1.1M367.1 149.2l-.8 .6M367.6 149.2v1.1M368.4 149.2h-.2l-.6 .6M369 149.2v.9l.3 .2h.8"/>
<path d="M370.1 149.2v1.4l-.6 .3M372.3 149.8h.8l.3-.3v-.5l-.3-.3h-.8v1.6M373.9 149.2h.3v1.1M373.9 150.3h.6M374.2 148.4v.3M22.3 162.3h3.8M55.4 168.2h2.5M55.4 170.7h2.5M55.4 173.3h2.5M55.4 175.8h2.5M55.4 178.4h2.5M73.1 168.2h2.6"/>
<path d="M73.1 170.7h2.6M73.1 173.3h2.6M73.1 175.8h2.6M73.1 178.4h2.6M96 163.1h2.5M98.5 161.8h7.7v2.6h-7.7zM106.2 160.6h-1.3l-5.4 5.1M106.2 163.1h2.5M106.2 167.3h1.1M106.8 166.8v1M108.9 166.5h-1.1v.8l.6-.3 .5 .3v.5l-.2 .3h-.6l-.3-.3M109.5 166.5v1.1l.5 .5 .6-.5v-1.1"/>
<path d="M112.8 167v1.1M113.6 167l-.8 .6M114.1 167.6h1.1l-.3-.6h-.5l-.3 .3v.5l.3 .3h.5M116.8 168.1h-.8l-.2-.3v-.5l.2-.3h.8v1.4l-.5 .3M117.4 167v.8l.3 .3h.8v-1.1M119 166.5h.3v1.6M119 168.1h.6M120.4 167h.5l.3 .3v.8h-.8l-.3-.3 .3-.2h.8M121.8 167h.5M122 166.8v1l.3 .3M122.9 167.6h1.1l-.3-.6h-.6l-.2 .3v.5l.2 .3h.6M125.6 166.5v1.6h-.8l-.3-.3v-.5l.3-.3h.8"/>
<path d="M127.8 167.3h.5M128.3 166.5l-.3 .3v1.3M128.9 167v1.1M129.7 167l-.8 .6M130.5 167h.5l.3 .3v.5l-.3 .3h-.5l-.3-.3v-.5zM132.4 167.3l-.5-.3v1.1M132.4 167.3v.8M132.4 167.3l.3-.3 .2 .3v.8M135.1 166.5v1.6h.9l.2-.3v-.5l-.2-.3h-.9M136.8 167v.8l.3 .3h.8v-1.1M139.5 167h-.8l-.3 .3 .3 .3h.5l.3 .2-.3 .3h-.8M210.3 170.7h5"/>
<path d="M210.3 173.3h5M210.3 175.8h5M210.3 178.4h5M215.3 165.7h35.6v68.5h-35.6zM250.9 168.2h5.1M250.9 170.7h5.1M250.9 173.3h5.1M250.9 175.8h5.1M250.9 178.4h5.1M266.1 160.6l.8 1.2M266.1 160.6l-.7 1.2M266.1 160.6v2.5"/>
<path d="M316.9 175.8v2.6M316.9 175.8l.8 1.3M316.9 175.8l-.7 1.3M405.8 162.3h3.8M23.1 186.4h1.2l.4 .4v1.6l-.4 .4h-1.2zM30 197l1.1 1.6M30.6 199.5l-.6 .5v.6l.6 .5M31.1 197l-1.1 1.6M31.7 197.8h1M34.4 197.2l-.3-.2h-.5l-.3 .2v1.1l.3 .3h.5l.3-.3M34.9 197.8h1.1M34.9 198.6v-1.1l.6-.5 .5 .5v1.1"/>
<path d="M37.7 197v1.6l-1.1-1.6v1.6M40.1 197.5h.6l.2 .3v.8h-.8l-.2-.3 .2-.3h.8M42.6 197v1.6h-.8l-.3-.3v-.5l.3-.3h.8M42.6 199.5h.2v1.6M43.7 199.5h.2v1.6M44.2 197v1.6h-.8l-.3-.3v-.5l.3-.3h.8M44.8 197.5v1.1M45.6 197.5l-.8 .5M46.1 198h1.1l-.3-.5h-.5l-.3 .3v.5l.3 .3h.5M48.3 199.8v1.1l.3 .2M48.9 197.5h-.9l-.2 .3 1.1 .5-.3 .3h-.8M50.5 197.5h-.8l-.3 .3 1.1 .5-.3 .3h-.8"/>
<path d="M52.1 199.5l.6 .5v.6l-.6 .5M55.4 180.9h2.5M55.4 183.4h2.5M55.4 186h2.5M55.4 188.5h2.5M55.4 191.1h2.5M55.4 193.6h2.5M55.4 196.1h2.5M55.4 198.7h2.5M73.1 180.9h2.6M73.1 183.4h2.6M73.1 186h2.6"/>
<path d="M73.1 188.5h2.6M73.1 191.1h2.6M73.1 193.6h2.6M73.1 196.1h2.6M73.1 198.7h2.6M210.3 180.9h5M210.3 183.4h5M210.3 186h5M210.3 188.5h5M210.3 191.1h5M210.3 193.6h5M210.3 196.1h5"/>
<path d="M210.3 198.7h5M250.9 183.4h5.1M250.9 188.5h5.1M250.9 191.1h5.1M250.9 196.1h5.1M305.9 193.6h1.8v5.1h-1.8zM306.8 191.1v2.5M306.8 198.7v5.1M316.9 191.1v3M316.9 195.6v3.1M334.7 183.4h5.1M334.7 188.5h5.1"/>
<path d="M334.7 191.1h5.1M334.7 196.1h5.1M365.2 183.4h5.1M365.2 186h5.1M365.2 191.1h5.1M365.2 193.6h5.1M406.6 186.4h1.2l.4 .4v1.6l-.4 .4h-1.2zM22.3 212.9h3.8M31.1 200.3l.3-.3h.5l.3 .3v.6l-.3 .2h-.5l-.3-.2zM32.7 201.1h.9l.2-.2v-.6l-.2-.3h-.9v1.7M34.4 200.6h1.1l-.3-.6h-.5l-.3 .3v.6l.3 .2h.5M36 201.1v-1.1h.9l.2 .3v.8"/>
<path d="M40.4 200h-.8l-.3 .3v.6l.3 .2h.8M41.2 200h.6l.2 .3v.6l-.2 .2h-.6l-.3-.2v-.6zM42.6 201.1h.5M43.7 201.1h.5M44.8 200.6h1l-.2-.6h-.6l-.2 .3v.6l.2 .2h.6M47.5 200h-.8l-.3 .3v.6l.3 .2h.8M48 200h.6M49.4 200h.5l.3 .3v.6l-.3 .2h-.5l-.3-.2v-.6zM50.8 200v1.1M51.6 200l-.8 .6M55.4 201.2h2.5M55.4 203.8h2.5"/>
<path d="M55.4 206.3h2.5M55.4 208.8h2.5M55.4 211.3h2.5M55.4 213.9h2.5M55.4 216.4h2.5M55.4 219h2.5M73.1 201.2h2.6M73.1 203.8h2.6M73.1 206.3h2.6M73.1 208.8h2.6M73.1 211.3h2.6M73.1 213.9h2.6"/>
<path d="M73.1 216.4h2.6M73.1 219h2.6M210.3 201.2h5M210.3 203.8h5M210.3 206.3h5M210.3 208.8h5M210.3 211.3h5M210.3 213.9h5M210.3 216.4h5M210.3 219h5M250.9 203.8h5.1M250.9 206.3h5.1"/>
<path d="M304.9 203.8h3.8M315 203.8h3.8M316.9 201.2v2.6M325.2 203.8h3.8M327.1 201.2v2.6M338.4 215l-.3-.3h-.5l-.3 .3v1.1l.3 .3h.5l.3-.3M339 216.4v-1.1l.5-.6 .5 .6v1.1M339 215.5h1M341.7 214.7v1.7l-1.1-1.7v1.7M343.9 215.3h.5M344.1 215v1.1l.3 .3M345 215.3v1.1"/>
<path d="M345.8 215.3l-.8 .5M346.6 215.3h.6l.2 .2v.9h-.8l-.3-.3 .3-.3h.8M348 216.4v-1.1h.8l.3 .2v.9M350.7 215.3h-.8l-.3 .2 1.1 .6-.3 .3h-.8M352.3 215.3h-.8l-.3 .2v.6l.3 .3h.8M352.9 215.8h1.1l-.3-.5h-.6l-.2 .2v.6l.2 .3h.6M354.5 216.4h.5M354.5 215.3h.3v1.1M354.8 214.5v.2M355.6 215.3l.6 1.1 .5-1.1M357.3 215.8h1l-.2-.5h-.6l-.2 .2v.6l.2 .3h.6M358.9 215.3v1.1"/>
<path d="M359.7 215.3l-.8 .5M361.9 215.5h.5M362.4 214.7l-.2 .3v1.4M363 215.5l.2-.2h.6l.3 .2v.6l-.3 .3h-.6l-.2-.3zM364.6 215.3v1.1M365.4 215.3l-.8 .5M367.6 214.7h1.1M368.2 214.7v1.7M369.3 215.5h.5M370.3 214.7h-1v1.7h1M370.9 215.5h.5M372 214.7h-1.1v1.7h1.1"/>
<path d="M373.6 214.7v1.7l-1.1-1.7v1.7M375.2 215l-.2-.3h-.6l-.2 .3 .2 .5h.6l.2 .3-.2 .6h-.6l-.2-.3M375.8 214.7v.3l.5 .5M376.3 215.5v.9M376.9 214.7l-.6 .8M405.8 212.9h3.8M23.1 238.1h.8M24.7 236.9h-1.6v2.5h1.6M55.4 239.3h2.5M55.4 221.5h2.5M55.4 224h2.5M55.4 226.6h2.5"/>
<path d="M55.4 229.1h2.5M55.4 231.7h2.5M55.4 234.2h2.5M55.4 236.7h2.5M73.1 239.3h2.6M73.1 221.5h2.6M73.1 224h2.6M73.1 226.6h2.6M73.1 229.1h2.6M73.1 231.7h2.6M73.1 234.2h2.6M73.1 236.7h2.6"/>
<path d="M210.3 221.5h5M210.3 224h5M210.3 226.6h5M210.3 229.1h5M232.4 239.9v.2M406.6 238.1h.8M408.2 236.9h-1.6v2.5h1.6M50.9 252h3.8M52.8 249.4v2.6M55.4 241.8h2.5M55.4 244.4h2.5M55.4 246.9h2.5"/>
<path d="M55.4 255.4h.8l.3 .2v1.1l-.3 .3h-.8zM57.1 257h.5M57.1 255.4h.5M57.3 255.4v1.6M59.2 255.4v1.6l-1.1-1.6v1.6M62.5 256.2h-1.1l.8-.8v1.6M63.1 257h1.1M63.1 255.9l.5-.5v1.6M64.7 256.2h.8l.3 .5-.3 .3h-.5l-.3-.3zM65.8 255.4l-1.1 .8M66.3 257h1.1M66.3 255.9l.6-.5v1.6"/>
<path d="M68 255.6l.2-.2h.6l.3 .2v.3l-1.1 1.1h1.1M71.2 255.4v1.6h.9l.2-.3v-.5l-.2-.3h-.9M73.1 241.8h2.6M73.1 244.4h2.6M73.1 246.9h2.6M73.2 255.9h.5l.3 .3v.8h-.8l-.3-.3 .3-.2h.8M75.6 255.9h-.8l-.3 .3v.5l.3 .3h.8M76.2 255.4v1.6M77 255.9l-.8 .6 .8 .5M77.5 257h.8l.3-.3v-.5l-.3-.3h-.8v1.6M79.2 257h.5M79.2 255.4h.2v1.6"/>
<path d="M80.5 255.9h.6l.2 .3v.8h-.8l-.3-.3 .3-.2h.8M81.9 257v-1.1h.8l.3 .3v.8M83.5 256.5h1.1l-.3-.6h-.5l-.3 .3v.5l.3 .3h.5M89 252h3.8M90.9 249.4v2.6M192.6 240.1h1.1M193.1 240.1v1.7M194.2 240.9h.6M195.3 240.1h-1.1v1.7h1.1M195.8 240.9h.6M196.9 240.1h-1.1v1.7h1.1M198.6 240.1v1.7l-1.1-1.7v1.7"/>
<path d="M200.2 240.4l-.3-.3h-.5l-.3 .6 .3 .2h.5l.3 .6-.3 .3h-.5l-.3-.3M200.7 240.1v.3l.6 .5M201.3 240.9v.9M201.8 240.1v.3l-.5 .5M204 240.4l.3-.3h.5l.3 .3-.3 .5M204.6 240.9h.2M204.8 240.9l.3 .3-.3 .6h-.5l-.3-.3M205.7 241.5h.2v.3h-.2zM206.5 240.4l.3-.3h.5l.3 .3v.3l-1.1 1.1h1.1M209.8 240.9h1M213.6 240.9l-.6-.2v1.1M213.6 240.9v.9"/>
<path d="M213.6 240.9l.2-.2 .3 .2v.9M214.9 240.7h.6l.3 .2v.9h-.9l-.2-.3 .2-.3h.9M216.3 241.8v-1.1h.8l.3 .2v.9M218.2 240.7h.6l.2 .2v.9h-.8l-.3-.3 .3-.3h.8M220.7 241.8h-.8l-.3-.3v-.6l.3-.2h.8v1.3l-.6 .3M221.2 241.2h1.1l-.3-.5h-.5l-.3 .2v.6l.3 .3h.5M223.4 240.9l-.6-.2v1.1M223.4 240.9v.9M223.4 240.9l.3-.2 .2 .2v.9M224.5 241.2h1.1l-.3-.5h-.5l-.3 .2v.6l.3 .3h.5M226.1 241.8v-1.1h.8l.3 .2v.9M227.8 240.7h.5"/>
<path d="M228 240.4v1.1l.3 .3M231 240.9l-.5-.2v1.1M231 240.9v.9M231 240.9l.3-.2 .3 .2v.9M232.1 241.8h.6M232.1 240.7h.3v1.1M234.3 240.7h-.8l-.3 .2v.6l.3 .3h.8M234.9 240.7v1.1M235.7 240.7h-.3l-.5 .5M236.2 240.9l.3-.2h.5l.3 .2v.6l-.3 .3h-.5l-.3-.3zM239 240.7h-.9l-.3 .2v.6l.3 .3h.9M239.8 240.7h.5l.3 .2v.6l-.3 .3h-.5l-.3-.3v-.6z"/>
<path d="M241.1 241.8v-1.1h.8l.3 .2v.9M242.8 240.7h.5M243 240.4v1.1l.3 .3M243.9 240.7v1.1M244.7 240.7h-.3l-.5 .5M245.2 240.9l.3-.2h.5l.3 .2v.6l-.3 .3h-.5l-.3-.3zM246.9 240.1h.2v1.7M246.9 241.8h.5M247.9 240.1h.3v1.7M247.9 241.8h.6M249 241.2h1.1l-.2-.5h-.6l-.3 .2v.6l.3 .3h.6M250.7 240.7v1.1"/>
<path d="M251.5 240.7l-.8 .5M256.6 246.9h3.8M258.5 244.4v2.5M312 248.6h1.1l.4-.4v-.8l-.4-.4h-1.1v2.3M312.7 248.6l.8 .7M313.5 252.5l-.4-.4h-.7l-.4 .4v1.5l.4 .4h.7l.4-.4M314.3 253.3l.4-.4h.8l.3 .4v.7l-.3 .4h-.8l-.4-.4zM314.7 247.8h.8l.3 .4v1.1h-1.1l-.4-.3 .4-.4h1.1M317.4 253.3l-.4-.4h-.4v1.5M317.4 253.3v1.1M317.4 253.3l.4-.4 .4 .4v1.1M318.2 247.8h-1.2l-.4 .4 .4 .4h.8l.4 .4-.4 .3h-1.2"/>
<path d="M319 249.3h1.1l.4-.3v-.8l-.4-.4h-1.1v2.3M319 254.4h1.1l.4-.4v-.7l-.4-.4h-1.1v2.3M321.3 247v2.3h1.2l.4-.3v-.8l-.4-.4h-1.2M321.3 252.9v1.1l.4 .4h1.2v-1.5M323.7 248.6h1.5v-.4l-.4-.4h-.8l-.3 .4v.8l.3 .3h.8M323.7 252.9h.7M324 252.5v1.5l.4 .4M325.2 253.6h1.6v-.3l-.4-.4h-.8l-.4 .4v.7l.4 .4h.8M326 247.8v1.5M327.2 247.8h-.4l-.8 .8M327.9 247.8v1.5M329.1 247.8h-.4l-.8 .8"/>
<path d="M329.9 247.8v1.2l.4 .3h1.1M329.9 252.1h1.1l.4 .4v.4l-.4 .4 .4 .3v.4l-.4 .4h-1.1zM329.9 253.3h1.1M331.4 247.8v1.9l-.4 .4h-.3M332.2 253.3l.4-.4h.8l.4 .4v.7l-.4 .4h-.8l-.4-.4zM334.6 248.6h1.1l.4-.4v-.8l-.4-.4h-1.1v2.3M335 252.9h.7l.4 .4v1.1h-1.1l-.4-.4 .4-.4h1.1M336.9 247.8h.4v1.5M336.9 249.3h.8M336.9 252.9v1.5M337.3 246.6v.4M338.1 252.9h-.4l-.8 .7"/>
<path d="M340.4 252.1v2.3h-1.2l-.3-.4v-.7l.3-.4h1.2M343.5 252.1v1.5l.8 .8 .8-.8v-1.5M345.9 254.4h1.5M345.9 252.9l.7-.8v2.3M364.6 253.3h41.2M364.6 258.3h41.2M364.6 243.1v20.3M364.6 248.2h41.2M366.5 257v-1.4h1.1l.4 .3v1.1M366.6 251.1h1.5v-.4l-.4-.4h-.8l-.3 .4v.8l.3 .4h.8M368.6 259.8v2.4M368.9 250.3v1.2l.4 .4h1.2v-1.6"/>
<path d="M369 255.6h.7l.4 .3v.7l-.4 .4h-.7l-.3-.4v-.7zM370.8 255.6h.7M371.1 255.2v1.4l.4 .4M371.2 250.3v1.6M372.4 250.3h-.4l-.8 .8M373.2 250.7l.4-.4h.8l.4 .4v.8l-.4 .4h-.8l-.4-.4zM375.7 255.6h-1.1l-.3 .3 .3 .4h.7l.4 .3-.4 .4h-1M376.7 255.6h.7l.4 .3v1.1h-1.1l-.3-.4 .3-.3h1.1M377.1 250.3h-1.2l-.4 .4v.8l.4 .4h1.2M378.2 250.3h.8l.4 .4v1.2h-1.2l-.3-.4 .3-.4h1.2M378.5 255.6l.7 1.4 .7-1.4M380.2 250.3v1.6"/>
<path d="M380.6 256.3h1.4v-.4l-.4-.3h-.7l-.3 .3v.7l.3 .4h.7M381.4 250.3h-.4l-.8 .8M383.7 249.6v2.3h-1.2l-.4-.4v-.8l.4-.4h1.2M383.8 259.7l-1.6 2.3M384.1 254.9v2.1h-1.1l-.3-.4v-.7l.3-.3h1.1M384.8 254.5v1.4M384.8 256.6v.4M395.7 258.3v5.1M405.8 243.1h-95.2v20.3M48.8 264.9l.8-.8v2.4M48.8 266.5h1.6M73.6 263.4v3.8"/>
<path d="M96.2 264.5l.4-.4h.8l.4 .4v.4l-1.6 1.6h1.6M121.1 263.4v3.8M143.7 264.5l.4-.4h.8l.4 .4v.4l-.4 .4M144.5 265.3h.4M144.9 265.3l.4 .4v.4l-.4 .4h-.8l-.4-.4M168.5 263.4v3.8M192.8 265.3h-1.6l1.2-1.2v2.4M216 263.4v3.8M240.2 264.1h-1.6v1.2l.8-.4h.4l.4 .4v.8l-.4 .4h-.8l-.4-.4M263.4 263.4v3.8M286.1 265.3h1.2l.4 .4v.4l-.4 .4h-.8l-.4-.4zM287.7 264.1l-.8 .4-.8 .8"/>
<path d="M310.9 263.4v3.8M333.5 264.1h1.6v.4l-1.6 1.6v.4M358.4 263.4v3.8M367.9 260.2l-.4-.4h-.8l-.4 .4v.4l.4 .4h.8l.4 .4v.4l-.4 .4h-.8l-.4-.4M368.6 261l.4-.4h.8l.4 .4v1.2M371 261.4h1.5v-.4l-.3-.4h-.8l-.4 .4v.8l.4 .4h.8M373.3 261.4h1.6v-.4l-.4-.4h-.8l-.4 .4v.8l.4 .4h.8M375.7 260.6h.7M376 260.2v1.6l.4 .4M377.2 260.6h.4v.4h-.4zM377.2 261.8h.4v.4h-.4zM379.9 260.5l.8-.8v2.3"/>
<path d="M379.9 262h1.5M381.4 265.3l-.4 .4v.4l.4 .4h.8l.4-.4v-.4l-.4-.4M381.4 265.3l-.4-.4v-.4l.4-.4h.8l.4 .4v.4l-.4 .4M381.4 265.3h.8M384.6 262h1.5M384.6 260.5l.8-.8v2.3"/>
<circle cx="53.8" cy="46.3" r=".99"/>
<circle cx="53.8" cy="48.8" r=".99"/>
</g>
<path d="M184.9 39.3h10.1v11.4h-10.1zM339.8 28.5h25.4v22.9h-25.4zM332.2 76.8h40.6v43.1h-40.6zM69.3 89.5h7.6v53.3h-7.6zM339.8 178.4h25.4v22.8h-25.4z" fill="none" stroke="#800000" stroke-width=".42"/>
<g fill="none" stroke="#800000" stroke-width=".61">
<path d="M70.6 97.1h1.3M70.6 94.5h1.3M70.6 92h1.3M70.6 99.6h1.3M74.4 97.1h1.3M74.4 94.5h1.3M74.4 92h1.3M74.4 99.6h1.3M70.6 102.2h1.3M70.6 109.8h1.3M70.6 107.2h1.3M70.6 104.7h1.3"/>
<path d="M70.6 114.9h1.3M70.6 112.3h1.3M70.6 119.9h1.3M70.6 117.4h1.3M74.4 102.2h1.3M74.4 109.8h1.3M74.4 107.2h1.3M74.4 104.7h1.3M74.4 114.9h1.3M74.4 112.3h1.3M74.4 119.9h1.3M74.4 117.4h1.3"/>
<path d="M70.6 122.5h1.3M70.6 127.6h1.3M70.6 125h1.3M70.6 132.6h1.3M70.6 130.1h1.3M70.6 135.2h1.3M70.6 137.7h1.3M74.4 122.5h1.3M74.4 127.6h1.3M74.4 125h1.3M74.4 132.6h1.3M74.4 130.1h1.3"/>
<path d="M74.4 135.2h1.3M74.4 137.7h1.3M70.6 140.3h1.3M74.4 140.3h1.3M57.9 168.2h1.3M57.9 170.7h1.3M57.9 173.3h1.3M57.9 175.8h1.3M57.9 178.4h1.3M75.7 168.2h1.2M75.7 170.7h1.2M75.7 173.3h1.2"/>
<path d="M75.7 175.8h1.2M75.7 178.4h1.2M57.9 180.9h1.3M57.9 183.4h1.3M57.9 186h1.3M57.9 188.5h1.3M57.9 191.1h1.3M57.9 193.6h1.3M57.9 196.1h1.3M57.9 198.7h1.3M75.7 180.9h1.2M75.7 183.4h1.2"/>
<path d="M75.7 186h1.2M75.7 188.5h1.2M75.7 191.1h1.2M75.7 193.6h1.2M75.7 196.1h1.2M75.7 198.7h1.2M57.9 201.2h1.3M57.9 203.8h1.3M57.9 206.3h1.3M57.9 208.8h1.3M57.9 211.3h1.3M57.9 213.9h1.3"/>
<path d="M57.9 216.4h1.3M57.9 219h1.3M75.7 201.2h1.2M75.7 203.8h1.2M75.7 206.3h1.2M75.7 208.8h1.2M75.7 211.3h1.2M75.7 213.9h1.2M75.7 216.4h1.2M75.7 219h1.2M57.9 221.5h1.3M57.9 224h1.3"/>
<path d="M57.9 226.6h1.3M57.9 229.1h1.3M57.9 231.7h1.3M57.9 234.2h1.3M57.9 236.7h1.3M57.9 239.3h1.3M75.7 221.5h1.2M75.7 224h1.2M75.7 226.6h1.2M75.7 229.1h1.2M75.7 231.7h1.2M75.7 234.2h1.2"/>
<path d="M75.7 236.7h1.2M75.7 239.3h1.2M57.9 241.8h1.3M57.9 244.4h1.3M57.9 246.9h1.3M75.7 241.8h1.2M75.7 244.4h1.2M75.7 246.9h1.2"/>
</g>
<path d="M22.3 6.9h387.3v260.3h-387.3z" fill="none" stroke="#800000" stroke-width=".32"/>
<g fill="#800000" stroke="#800000" stroke-width=".31">
<path d="M40.6 52.9h4.1v.5h-4.1z"/>
<path d="M40.6 51.9h4.1v.5h-4.1z"/>
<path d="M332.7 134.2h4v.5h-4z"/>
<path d="M332.7 133.1h4v.5h-4z"/>
<path d="M360.6 134.2h4.1v.5h-4.1z"/>
<path d="M360.6 133.1h4.1v.5h-4.1z"/>
<path d="M302.2 78.3h4.1v.5h-4.1z"/>
<path d="M302.2 77.3h4.1v.5h-4.1z"/>
<path d="M302.2 32.6h4.1v.5h-4.1z"/>
<path d="M302.2 31.6h4.1v.5h-4.1z"/>
<path d="M189.9 48.6h2.3v.5h-2.3z"/>
<path d="M189.9 46h2.3v.5h-2.3z"/>
<path d="M189.9 43.5h2.3v.5h-2.3z"/>
<path d="M189.9 41h2.3v.5h-2.3z"/>
<path d="M314.9 195.1h4.1v.5h-4.1z"/>
<path d="M314.9 194.1h4.1v.5h-4.1z"/>
<path d="M172.7 116.4h4v.5h-4z"/>
<path d="M172.7 115.4h4v.5h-4z"/>
<path d="M162.5 116.4h4.1v.5h-4.1z"/>
<path d="M162.5 115.4h4.1v.5h-4.1z"/>
<path d="M152.4 116.4h4v.5h-4z"/>
<path d="M152.4 115.4h4v.5h-4z"/>
<path d="M215.9 116.4h4v.5h-4z"/>
<path d="M215.9 115.4h4v.5h-4z"/>
<path d="M226 116.4h4.1v.5h-4.1z"/>
<path d="M226 115.4h4.1v.5h-4.1z"/>
</g>
<g fill="none" stroke="#008000" stroke-width=".31">
<path d="M60.4 31.1v2.5M85.8 31.1v15.2h-2.5M85.8 36.1h15.3v2.6M90.9 36.1v2.6M217.9 33.6v5.1h10.1M238.2 38.7h2.5M248.4 38.7h5v22.8M304.2 23.4v5.1M304.2 36.1v2.6M327.1 26v7.6h7.6M334.7 38.7h-2.5v30.5h45.7v12.7h-2.6M370.3 33.6h7.6v30.5h-53.4v22.8h2.6"/>
<path d="M42.7 46.3v2.5M42.7 56.5v2.5M55.4 48.8h7.6M55.4 46.3h7.6M60.4 43.8v2.5M60.4 48.8v10.2M60.4 56.5h2.6M60.4 53.9h2.6M60.4 51.4h2.6M83.3 53.9h35.5M83.3 51.4h35.5M90.9 48.8v2.6"/>
<path d="M101.1 46.3v7.6M167.1 48.8h15.2M167.1 41.2h15.2M167.1 43.8h15.2M167.1 46.3h15.2M197.6 48.8h5M197.6 41.2h5v12.7M197.6 43.8h5M197.6 46.3h5M217.9 48.8h10.1M217.9 59h10.1M235.7 48.8h7.6"/>
<path d="M238.2 59h5.1M248.4 48.8h5M248.4 59h5M319.5 41.2h15.2M334.7 46.3h-7.6v5.1M370.3 41.2h25.4M370.3 43.8h25.4M304.2 69.2v5M319.5 76.8v10.1M60.4 86.9v25.4h5.1M60.4 92h5.1M80.8 97.1h2.5v45.7"/>
<path d="M80.8 92h2.5M80.8 99.6h38M83.3 86.9v7.6h-2.5M154.4 84.4v27.9M154.4 92h25.4M174.7 97.1h5.1M174.7 92v20.3M202.6 92h50.8M207.7 92v5.1h-5.1M228 92v20.3M243.3 86.9v5.1M253.4 86.9h5.1"/>
<path d="M258.5 81.9v10.1M304.2 81.9v2.5M319.5 97.1v12.7h7.6M319.5 81.9h7.6M327.1 99.6h-2.6v30.5h22.9M377.9 86.9h2.5v43.2h-27.9M377.9 99.6h22.8M37.6 114.9h27.9M37.6 119.9h27.9M37.6 104.7h27.9M37.6 117.4h27.9M65.5 102.2h-2.5v40.6"/>
<path d="M80.8 102.2h38M80.8 107.2h2.5M80.8 114.9h2.5M80.8 119.9h38M80.8 104.7h38M129 102.2h50.8M144.2 102.2v7.6M144.2 119.9v2.6M154.4 119.9v2.6M164.5 102.2v10.1M164.5 119.9v2.6M174.7 107.2h5.1"/>
<path d="M174.7 119.9v2.6M202.6 102.2h15.3v10.1M202.6 107.2h7.7v15.3M217.9 119.9v2.6M228 119.9v2.6M240.7 109.8v35.5h17.8v28h-2.5M273.8 119.9h22.8M278.8 119.9v2.6M299.1 102.2h28M299.1 107.2h28M299.1 104.7h28M327.1 114.9h-7.6v7.6"/>
<path d="M377.9 102.2h22.8M37.6 127.6h27.9M37.6 132.6h27.9M37.6 125h27.9M37.6 130.1h27.9M37.6 135.2h27.9M37.6 137.7h27.9M52.8 137.7v2.6M63 122.5h2.5M80.8 127.6h2.5M80.8 132.6h2.5M80.8 125h38"/>
<path d="M80.8 130.1h38M80.8 135.2h38M80.8 137.7h38M258.5 130.1v5.1M278.8 132.6v2.6M334.7 137.7v2.6M362.6 137.7v2.6M63 140.3h2.5M80.8 140.3h38M113.7 158v5.1h-5M55.4 168.2h-2.6v81.2M57.9 168.2h33v81.2"/>
<path d="M93.5 163.1v7.6h-35.6M96 163.1h-53.3v7.6h12.7M179.8 178.4h30.5M179.8 170.7h30.5M179.8 173.3h30.5M179.8 175.8h30.5M256 178.4h2.5v66M266.1 163.1v7.6h-10.1M316.9 178.4v12.7M35 193.6h20.4M35 191.1h20.4M35 186h20.4"/>
<path d="M35 188.5h22.9M179.8 193.6h30.5M179.8 191.1h30.5M179.8 186h30.5M179.8 188.5h30.5M179.8 180.9h30.5M301.7 188.5h33M306.8 191.1h27.9M316.9 198.7v2.5M316.9 183.4h17.8M334.7 196.1h-7.6v5.1M370.3 193.6h25.4"/>
<path d="M370.3 191.1h25.4M370.3 183.4h2.5v27.9h-71.1M35 216.4h20.4M35 219h20.4M179.8 216.4h30.5M179.8 219h30.5M179.8 213.9h30.5M179.8 211.3h30.5M179.8 208.8h30.5M179.8 206.3h30.5M179.8 221.5h30.5M179.8 229.1h30.5"/>
<path d="M179.8 226.6h30.5M179.8 224h30.5M52.8 246.9h2.6M57.9 246.9h17.8M78.2 246.9h12.7"/>
</g>
<g fill="#008000" stroke="#008000" stroke-width=".31">
<circle cx="60.4" cy="56.5" r=".51"/>
<circle cx="60.4" cy="53.9" r=".51"/>
<circle cx="60.4" cy="51.4" r=".51"/>
<circle cx="60.4" cy="48.8" r=".51"/>
<circle cx="63" cy="122.5" r=".51"/>
<circle cx="63" cy="140.3" r=".51"/>
<circle cx="83.3" cy="107.2" r=".51"/>
<circle cx="83.3" cy="114.9" r=".51"/>
<circle cx="83.3" cy="127.6" r=".51"/>
<circle cx="83.3" cy="132.6" r=".51"/>
<circle cx="90.9" cy="246.9" r=".51"/>
<circle cx="52.8" cy="246.9" r=".51"/>
<circle cx="202.6" cy="48.8" r=".51"/>
<circle cx="202.6" cy="43.8" r=".51"/>
<circle cx="202.6" cy="46.3" r=".51"/>
<circle cx="253.4" cy="59" r=".51"/>
<circle cx="253.4" cy="48.8" r=".51"/>
<circle cx="85.8" cy="36.1" r=".51"/>
<circle cx="90.9" cy="36.1" r=".51"/>
<circle cx="60.4" cy="92" r=".51"/>
<circle cx="319.5" cy="81.9" r=".51"/>
<circle cx="90.9" cy="51.4" r=".51"/>
<circle cx="60.4" cy="46.3" r=".51"/>
<circle cx="83.3" cy="92" r=".51"/>
<circle cx="258.5" cy="86.9" r=".51"/>
<circle cx="377.9" cy="81.9" r=".51"/>
<circle cx="101.1" cy="53.9" r=".51"/>
<circle cx="52.8" cy="137.7" r=".51"/>
<circle cx="334.7" cy="130.1" r=".51"/>
<circle cx="346.1" cy="130.1" r=".51"/>
<circle cx="362.6" cy="130.1" r=".51"/>
<circle cx="353.8" cy="130.1" r=".51"/>
<circle cx="93.5" cy="163.1" r=".51"/>
<circle cx="240.7" cy="48.8" r=".51"/>
<circle cx="238.2" cy="48.8" r=".51"/>
<circle cx="240.7" cy="59" r=".51"/>
<circle cx="164.5" cy="102.2" r=".51"/>
<circle cx="144.2" cy="102.2" r=".51"/>
<circle cx="316.9" cy="183.4" r=".51"/>
<circle cx="174.7" cy="92" r=".51"/>
<circle cx="174.7" cy="97.1" r=".51"/>
<circle cx="174.7" cy="107.2" r=".51"/>
<circle cx="154.4" cy="92" r=".51"/>
<circle cx="207.7" cy="92" r=".51"/>
<circle cx="228" cy="92" r=".51"/>
<circle cx="243.3" cy="92" r=".51"/>
<circle cx="278.8" cy="119.9" r=".51"/>
</g>
<use href="#words"/>
</svg>
